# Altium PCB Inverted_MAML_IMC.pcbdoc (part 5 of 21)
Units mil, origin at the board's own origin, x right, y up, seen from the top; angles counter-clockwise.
Board outline 7677.1 x 6771.6 mil, 6 copper layers (Top Layer, Inner1, Inner2, Inner3, Inner4, Bottom Layer), stack 60.7 mil thick; 2730 components, 1566 nets, 7761 pads, 3719 vias.

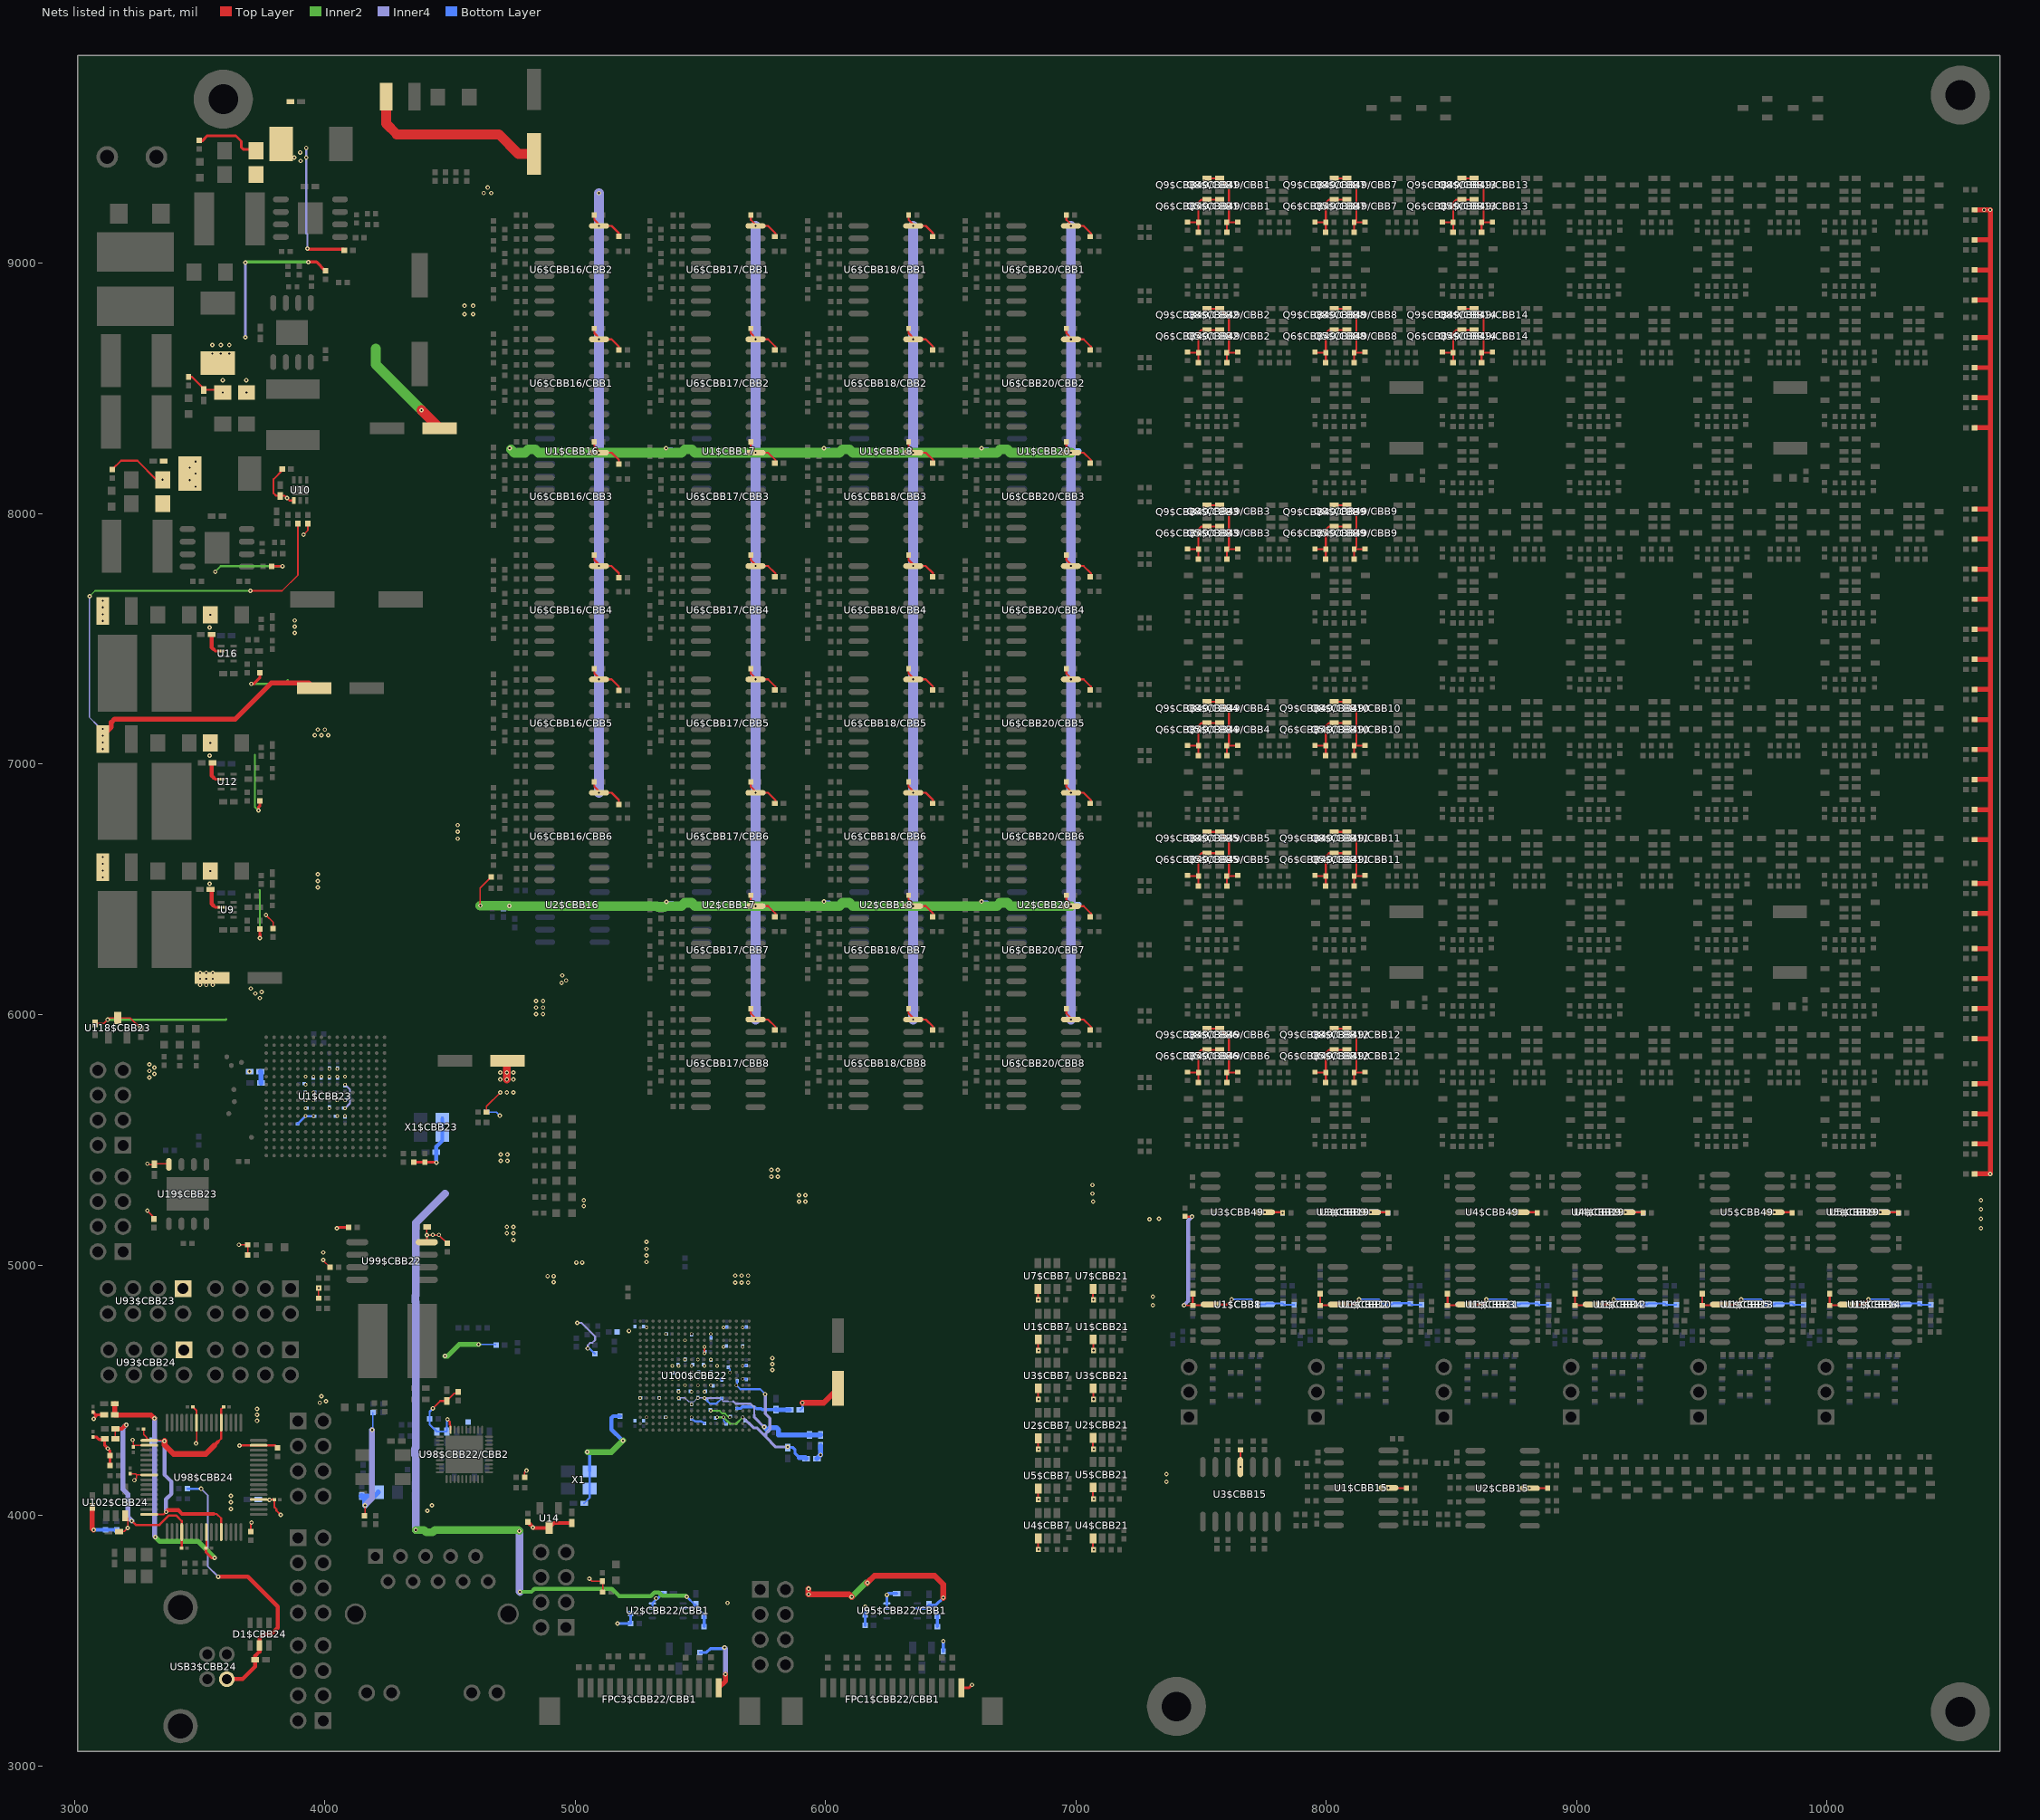
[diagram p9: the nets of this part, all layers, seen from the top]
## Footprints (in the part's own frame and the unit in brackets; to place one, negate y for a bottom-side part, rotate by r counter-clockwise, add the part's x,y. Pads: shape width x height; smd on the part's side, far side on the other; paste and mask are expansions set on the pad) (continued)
USB-B-TH_USB-B10-BRW [mil]
  round 63 hole 39.4: 1(49.2,92.8) 2(-49.2,92.8) 3(-49.2,14) 4(49.2,14)
  round 137.8 hole 98.4: 5(-237,-92.7) 6(237,-92.7)
  silkscreen extent -239,-504 239,138
VSSOP-8_L2.4-W2.1-P0.50-LS3.2-BR#1 [mil]
  oval 29.5x9.8 smd: 1(61,-29.5) 2(61,-9.8) 3(61,9.9) 4(61,29.6) 5(-61,29.6) 6(-61,9.9) 7(-61,-9.8) 8(-61,-29.5)
  silkscreen extent -35,-40 36,39
VSSOP-8_L2.4-W2.1-P0.50-LS3.2-BR#2 [mil]
  oval 29.5x9.8 smd: 1(61,-29.6) 2(61,-9.9) 3(61,9.8) 4(61,29.5) 5(-61,29.5) 6(-61,9.8) 7(-61,-9.9) 8(-61,-29.6)
  silkscreen extent -35,-40 35,39
WQFN-40_L5.0-W5.0-P0.4-BL-EP [mil]
  oval 7.9x31.5 smd paste-3937 mask+2: 1(-70.9,-98.4) 2(-55.1,-98.4) 3(-39.4,-98.4) 4(-23.6,-98.4) 5(-7.9,-98.4) 6(7.9,-98.4) 7(23.6,-98.4) 8(39.4,-98.4) 9(55.1,-98.4) 10(70.9,-98.4) 21(70.9,98.4) 22(55.1,98.4) 23(39.4,98.4) 24(23.6,98.4) 25(7.9,98.4) 26(-7.9,98.4) 27(-23.6,98.4) 28(-39.4,98.4) 29(-55.1,98.4) 30(-70.9,98.4)
  oval 31.5x7.9 smd paste-3937 mask+2: 11(98.4,-70.9) 12(98.4,-55.1) 13(98.4,-39.4) 14(98.4,-23.6) 15(98.4,-7.9) 16(98.4,7.9) 17(98.4,23.6) 18(98.4,39.4) 19(98.4,55.1) 20(98.4,70.9) 31(-98.4,70.9) 32(-98.4,55.1) 33(-98.4,39.4) 34(-98.4,23.6) 35(-98.4,7.9) 36(-98.4,-7.9) 37(-98.4,-23.6) 38(-98.4,-39.4) 39(-98.4,-55.1) 40(-98.4,-70.9)
  rect 149.6x149.6 smd paste-3937 mask+2: 41(0,0)
  silkscreen extent -106,-132 106,106
WSON-8_L6.0-W5.0-P1.27-BL-EP [mil]
  oval 22.9x50.2 smd: 1(-75,-118.6) 2(-25,-118.6) 3(25,-118.6) 4(75,-118.6) 5(75,118.6) 6(25,118.6) 7(-25,118.6) 8(-75,118.6)
  rect 169.3x133.9 smd: 9(0,0)
  silkscreen extent -102,-159 101,121

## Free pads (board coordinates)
  round 236.2 hole 118.1: 1(3595.2,9656.1) 1(7402.1,3236.9) 1(10532.6,3215.7) 1(10532.6,9672.4)

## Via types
v1: diameter 17.7, hole 7.9, Top Layer to Bottom Layer, 3387 vias
v2: diameter 13.8, hole 7.9, Top Layer to Bottom Layer, 287 vias
v3: diameter 23.6, hole 11.8, Top Layer to Bottom Layer, 45 vias

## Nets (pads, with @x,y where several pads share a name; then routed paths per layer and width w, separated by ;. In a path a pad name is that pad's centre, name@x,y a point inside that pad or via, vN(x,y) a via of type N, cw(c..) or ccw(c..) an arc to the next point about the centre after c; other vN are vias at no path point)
1.2V: C3$CBB23.1 C5.1 C8$CBB23.1 C9$CBB23.1 C10$CBB23.1 C11$CBB23.1 C12$CBB23.1 C14.1 C15.1 C16.1 C17.1 C18.1 C19.1 C20.1 C22$CBB22/CBB4.1 C23$CBB22/CBB4.1 C24$CBB22/CBB4.1 C25$CBB22/CBB4.1 C26.1 C28.1 C78.1 C80.1 C248.1 C250.1 C258.1 C313.1 C314.1 L10$CBB22/CBB4.1 L11$CBB22/CBB4.1 L11$CBB23.1 R146.1 U1$CBB23.E9 U1$CBB23.F8 U1$CBB23.F9 U1$CBB23.J6 U1$CBB23.J7 U1$CBB23.K9 U100$CBB22.G8 U100$CBB22.G10 U100$CBB22.G12 U100$CBB22.H7 U100$CBB22.H9 U100$CBB22.H11 U100$CBB22.J2 U100$CBB22.J8 U100$CBB22.J10 U100$CBB22.J12 U100$CBB22.K4 U100$CBB22.K7 U100$CBB22.K9 U100$CBB22.K11 U100$CBB22.L2 U100$CBB22.L6 U100$CBB22.L8 U100$CBB22.L10 U100$CBB22.L12 U100$CBB22.M7 U100$CBB22.M9 U100$CBB22.M11 U100$CBB22.P2 U100$CBB22.P5 U100$CBB22.T7 U100$CBB22.U2 U100$CBB22.U5 | length 154.4
  Bottom Layer w5.5: C18.1@5611.1,4591.4 5618.6,4583.9 v2(5618.6,4571)
  Bottom Layer w5.9: v2(5541.9,4724.5) 5542.8,4723.6 C23$CBB22/CBB4.1@5542.8,4709.4 ; v2(5593,4750.1) 5605.1,4750.1 C26.1@5607,4752.1 ; v2(5669.8,4750.1) 5681.4,4750.1 C25$CBB22/CBB4.1@5683.3,4752.1
  Bottom Layer w7.9: v2(5669.8,4545.4) 5680.7,4545.4 C78.1@5683.3,4542.8 ; v2(5669.8,4596.6) 5680.4,4596.6 C15.1@5683.3,4599.5
  Bottom Layer w19.7: L10$CBB22/CBB4.1@5965.8,4226.8 v1(5980.5,4241.5) L11$CBB22/CBB4.1@5980.5,4277.6
  other v1: 5639.2,4929.5 5665.3,4929.5 5691.4,4929.5 4914.3,4931.5 4890.2,4955.6 4914.3,4955.6 5639.2,4957.6 5665.3,4957.6 5691.4,4957.6 3700.2,5772.8 4844.1,6001.7 4872.2,6001.7 4844.1,6027.8 4872.2,6027.8 4844.1,6053.9 4872.2,6053.9 3502.8,6118.2 3526.9,6118.2 3553,6118.2 3502.8,6142.3 3526.9,6142.3 3553,6142.3 3502.8,6166.4 3526.9,6166.4 3553,6166.4 3113.3,7571.9 3113.3,7598 3113.3,7626.1 3113.3,7652.2
  other v2: 5413.9,4494.2 5465.1,4494.2 5516.3,4494.2 5439.5,4519.8 5490.7,4519.8 5541.9,4519.8 5413.9,4545.4 5465.1,4545.4 5516.3,4545.4 5439.5,4571 5490.7,4571 5541.9,4571 5413.9,4596.6 5465.1,4596.6 5516.3,4596.6 5567.4,4596.6 5439.5,4622.2 5490.7,4622.2 5541.9,4622.2 5593,4673.3 5669.8,4673.3 4018.6,5625.9 3924.1,5657.4 3955.6,5657.4 3987.1,5751.9 4018.6,5751.9 4018.6,5783.4
1.2VA1: C5$CBB23.1 C6$CBB23.1 C7$CBB23.1 C147$CBB23.2 L11$CBB23.2 U1$CBB23.F7 U1$CBB23.G11 U1$CBB23.K11 | length 157.6
  Inner4 w7.9: v2(4081.6,5625.9) 4101.1,5645.5 4101.1,5700.9 v2(4081.6,5720.4)
  Bottom Layer w19.7: L11$CBB23.2@3743.1,5772.8 3745.1,5770.8 C147$CBB23.2@3745.1,5726.7
  other v2: 3955.6,5751.9
1.2VA_MIPI_T1: C10.1 C11.1 C12.1 C13.1 C142$CBB22/CBB4.2 L10$CBB22/CBB4.2 U100$CBB22.C2 U100$CBB22.C5 U100$CBB22.C6 U100$CBB22.H3 | length 836.6
  Inner2 w7.9: v2(5567.4,4391.9) v2(5593,4391.9) 5619.6,4365.3 5643.3,4365.3 v2(5669.8,4391.9)
  Inner4 w11.8: v2(5669.8,4391.9) 5712.4,4349.3 5725.5,4349.3 5761.5,4313.3 ; v1(5759.6,4483.8) 5759.6,4405.5 5777.7,4387.4 5777.7,4343.2 5761.5,4327 5761.5,4313.3 ; v1(5850,4273) 5801.8,4273 5761.5,4313.3
  Bottom Layer w4.7: v2(5593,4391.9) 5593,4376.6 C11.1@5604.3,4365.3 ; v2(5669.8,4391.9) 5679.3,4382.3 C12.1@5679.3,4378.1
  Bottom Layer w7.9: C13.1@5647.2,4537.2 5647.2,4522.8 v2(5644.2,4519.8) 5660.2,4503.9 5739.6,4503.9 v1(5759.6,4483.8)
  Bottom Layer w11.8: C142$CBB22/CBB4.2@5850,4270.3 5850.9,4271.3 5869.8,4271.3 5878.1,4262.9 5878.1,4248.9 5896.2,4230.8
  Bottom Layer w19.7: 5896.2,4230.8 5918.9,4230.8 L10$CBB22/CBB4.2@5922.9,4226.8
1.2VA_PLL_T1: C21.1 C22.1 C23.1 C24.1 C25.1 C27.1 C147$CBB22/CBB4.2 L11$CBB22/CBB4.2 U100$CBB22.F8 U100$CBB22.F9 U100$CBB22.F12 U100$CBB22.N8 U100$CBB22.P8 | length 817.1
  Top Layer w7.9: v2(5516.3,4647.8) v2(5516.3,4673.3)
  Inner4 w3.9: 5452.3,4455.8 5476.7,4455.8 5489.5,4468.6 v2(5490.7,4468.6) ; 5611.9,4455.8 5631,4455.8
  Inner4 w5.5: v2(5413.9,4468.6) 5439.5,4468.6 5452.3,4455.8 ; v2(5490.7,4468.6) v2(5516.3,4468.6)
  Inner4 w5.9: v2(5516.3,4468.6) 5578,4468.6 5590.8,4455.8 5611.9,4455.8
  Inner4 w7.9: 5631,4455.8 5641.2,4445.6 5701.4,4445.6 5716,4431 5716,4400.9
  Inner4 w11.8: 5716,4400.9 5716,4390.9 5753.6,4353.3 v1(5755.7,4353.3)
  Bottom Layer w5.5: v1@5759,4350 5778.8,4350
  Bottom Layer w5.9: v2(5516.3,4468.6) 5521,4468.6 C24.1@5526,4463.7
  Bottom Layer w7.9: C24.1@5526.7,4457.7 5538.8,4445.6 5564.1,4445.6 C21.1@5586.2,4467.7
  Bottom Layer w19.7: v1(5755.7,4353.3) 5759,4350 5770.6,4338.5 5770.6,4341.8 5778.8,4350 5779.2,4350.5 5804.3,4350.5 5813,4341.8 5813,4320.5 C147$CBB22/CBB4.2@5936.3,4320.5 L11$CBB22/CBB4.2@5980.5,4320.5
1.8V: C1.2 C59$CBB22/CBB1.2 C79.1 R60.2 R97$CBB22/CBB1.2 R128$CBB22/CBB1.2 R129$CBB22/CBB1.2 R130$CBB22/CBB1.2 R132.1 U2$CBB22/CBB1.2 U95$CBB22/CBB1.2 | length 6410.3
  Top Layer w5.9: v1(3703.6,7692.4) 3830.1,7692.4 3892.9,7755.2 R60.2@3892.9,7961.1
  Top Layer w19.7: v1(3113.3,7114.3) 3147.4,7148.4 3147.4,7166.3 3161.3,7180.2 3643.2,7180.2 3787.9,7324.9 3935.8,7324.9 C79.1@3957.9,7302.8
  Top Layer w23.6: v1(5932.3,3706.7) v1(5932.3,3684.6) 6095,3684.6 v1(6105,3674.6) ; v1(6167.2,3730.8) 6195.4,3758.9 6436.3,3758.9 6470.4,3724.8 v1(6470.4,3670.6)
  Inner2 w5.9: v1(3061.1,7670.3) 3083.1,7692.4 v1(3703.6,7692.4)
  Inner2 w15.7: v1(4779.8,3694.7) 4826,3694.7 4838,3706.7 4844.8,3706.7 4845.1,3706.4 4883.5,3706.4 4883.9,3706.7 4944.8,3706.7 4945.1,3706.4 4983.5,3706.4 4983.9,3706.7 5147.2,3706.7 5176.4,3677.6 5302.2,3677.6 5316.9,3692.3 5334.9,3692.3 5347.7,3679.6 5441.4,3679.6 v1(5446.4,3674.6)
  Inner2 w23.6: v1(6105,3674.6) 6161.2,3730.8 v1(6167.2,3730.8)
  Inner2 w31.5: v1(4364.2,3941.7) 4396.6,3941.7 4406.1,3932.1 4430.6,3932.1 4440.2,3941.7 4773.8,3941.7 v1(4777.8,3937.6)
  Inner4 w5.9: v1(3061.1,7670.3) 3061.1,7186.4 3093.2,7154.3
  Inner4 w31.5: v1(4364.2,3941.7) 4364.2,4239.1 4360.7,4242.6 4360.7,4267.1 4364.2,4270.6 4364.2,4851.5 4362.7,4853 4362.7,4877.5 4364.2,4879 4364.2,5168.5 4480.6,5284.9 ; v1(4777.8,3937.6) 4777.8,3696.7 v1(4779.8,3694.7)
  Bottom Layer w7.9: U2$CBB22/CBB1.2@5431.4,3629.3 5468.8,3629.3 C1.2@5480.2,3640.8 ; v1(5446.4,3674.6) C1.2@5478.1,3643 ; R128$CBB22/CBB1.2@5515.5,3596.2 5515.5,3605.5 C1.2@5480.2,3640.8 ; C1.2@5478.1,3643 C1.2@5482.4,3643 C1.2@5480.2,3640.8 ; C1.2@5478.1,3643 C1.2@5480.2,3640.8
  Bottom Layer w11.8: R97$CBB22/CBB1.2@5515.5,3556 R128$CBB22/CBB1.2@5515.5,3596.2 ; U95$CBB22/CBB1.2@6367.1,3628.7 6400.3,3628.7 C59$CBB22/CBB1.2@6414.1,3642.5 ; R130$CBB22/CBB1.2@6447.3,3556.1 R129$CBB22/CBB1.2@6447.3,3596.3 6447.3,3609.3 C59$CBB22/CBB1.2@6414.1,3642.5 ; v1(6470.4,3670.6) 6442.3,3642.5 C59$CBB22/CBB1.2@6414.1,3642.5
  other v1: 5609.1,3650.5 4530.8,6702.5 4530.8,6730.6 4530.8,6756.7 3113.3,7060.1 3113.3,7086.2 3113.3,7140.4
1.8V_FT: C217$CBB24.2 C218$CBB24.1 C219$CBB24.1 U98$CBB24.12 U98$CBB24.37 U98$CBB24.49 U98$CBB24.64 | length 1248.5
  Top Layer w4.7: C218$CBB24.1@3276.7,4345.2 3276.7,4322.1 U98$CBB24.49@3299.4,4299.4 3357.9,4299.4 v1(3360.2,4297)
  Top Layer w7.9: U98$CBB24.64@3299.4,4004.1 3356.8,4004.1 v1(3366.4,4013.7) ; 3557,4005.9 3569.1,4005.9 3586.8,3988.2 U98$CBB24.12@3586.8,3933.3 ; 3573.1,4293 3586.8,4306.7 U98$CBB24.37@3586.8,4370.3 3586.8,4424 C219$CBB24.1@3596.4,4433.6
  Top Layer w15.7: v1(3366.4,4013.7) 3373.7,4021 3415.5,4021 3430.5,4005.9 3557,4005.9 ; 3558,4278 3573.1,4293
  Top Layer w23.6: v1(3360.2,4297) 3360.2,4281 3396.4,4244.8 3524.9,4244.8 3558,4278
  Inner4 w15.7: v1(3360.2,4297) 3360.2,4162.5 3388.3,4134.4 3388.3,4086.2 3366.4,4064.3 v1(3366.4,4013.7)
  Bottom Layer w7.9: C217$CBB24.2@3310,4296.4 3359.6,4296.4 v1(3360.2,4297)
2.5V: C77.1 L9$CBB22/CBB4.1 R58.1 | length 198.1
  Top Layer w23.6: v1(5908.2,4449.6) 5993.3,4449.6 C77.1@6050.8,4507.2
  Bottom Layer w7.9: L9$CBB22/CBB4.1@5899.6,4421.5 5908.2,4430.2 v1(5908.2,4449.6)
  other v1: 5034.8,5234.7 5894.2,5252.8 5920.3,5252.8 5034.8,5258.8 5894.2,5278.9 5920.3,5278.9 4946.3,6126.2 4964.5,6136.3 4948.5,6156.3 3113.3,6548.3 3113.3,6574.4 3113.3,6602.5 3113.3,6628.6
2.5VA_MIPI_T1: C8.1 C9.1 C52.1 C138$CBB22/CBB4.2 L9$CBB22/CBB4.2 U100$CBB22.C4 U100$CBB22.D7 | length 306.5
  Inner2 w7.9: v2(5541.9,4417.4) 5577,4417.4 5587.8,4406.6 5599.1,4406.6 5613.9,4391.9 v2(5618.6,4391.9)
  Bottom Layer w11.8: C9.1@5645.2,4426.8 5660.5,4426.8 5667.3,4433.6 5717.5,4433.6 5725.5,4425.6 5743.6,4425.6 5747,4422.2 C138$CBB22/CBB4.2@5801.8,4422.2
  Bottom Layer w19.7: C138$CBB22/CBB4.2@5801.8,4422.2 5802.4,4421.5 L9$CBB22/CBB4.2@5856.6,4421.5
3.3V: C1$CBB7.2 C1$CBB16.2 C1$CBB17.2 C1$CBB18.2 C1$CBB20.2 C1$CBB21.2 C2$CBB7.2 C2$CBB15.2 C2$CBB21.2 C3$CBB7.2 C3$CBB21.2 C4$CBB7.2 C4$CBB21.2 C7$CBB7.2 C7$CBB21.2 C37.2 C67.2 C71.2 C75.1 C145$CBB15.2 C146$CBB15.2 C193$CBB1.2 C193$CBB2.2 C193$CBB3.2 C193$CBB4.2 C193$CBB5.2 C193$CBB6.2 C193$CBB7.2 C193$CBB8.2 C193$CBB10.2 C193$CBB11.2 C193$CBB12.2 C193$CBB13.2 C193$CBB14.2 C193$CBB16.2 C193$CBB16/CBB1.2 C193$CBB16/CBB2.2 C193$CBB16/CBB3.2 C193$CBB16/CBB4.2 C193$CBB16/CBB5.2 C193$CBB16/CBB6.2 C193$CBB17.2 C193$CBB17/CBB1.2 C193$CBB17/CBB2.2 C193$CBB17/CBB3.2 C193$CBB17/CBB4.2 C193$CBB17/CBB5.2 C193$CBB17/CBB6.2 C193$CBB17/CBB7.2 C193$CBB17/CBB8.2 C193$CBB18.2 C193$CBB18/CBB1.2 C193$CBB18/CBB2.2 C193$CBB18/CBB3.2 C193$CBB18/CBB4.2 C193$CBB18/CBB5.2 C193$CBB18/CBB6.2 C193$CBB18/CBB7.2 C193$CBB18/CBB8.2 C193$CBB20.2 C193$CBB20/CBB1.2 C193$CBB20/CBB2.2 C193$CBB20/CBB3.2 C193$CBB20/CBB4.2 C193$CBB20/CBB5.2 C193$CBB20/CBB6.2 C193$CBB20/CBB7.2 C193$CBB20/CBB8.2 C193$CBB21.2 C194$CBB9.2 C194$CBB19.2 C195$CBB9.2 C195$CBB19.2 C195$CBB49.2 C196$CBB9.2 C196$CBB19.2 C196$CBB49.2 C197$CBB9.2 C197$CBB19.2 C197$CBB49.2 L6.2 R2.1 R4$CBB1.2 R4$CBB2.2 R4$CBB3.2 R4$CBB4.2 R4$CBB5.2 R4$CBB6.2 R4$CBB8.2 R4$CBB10.2 R4$CBB11.2 R4$CBB12.2 R4$CBB13.2 R4$CBB14.2 R5.1 R8.1 R11.1 R14.1 R16$CBB17.2 R16$CBB18.2 R16$CBB20.2 R17.1 R20.1 R23.1 R26.1 R29.1 R32$CBB16.2 R32.1 R35.1 R38.1 R41.1 R44.1 R48$CBB17.2 R48$CBB18.2 R48$CBB20.2 R61.2 R64$CBB16.2 R74.1 R80$CBB17.2 R80$CBB18.2 R80$CBB20.2 R81.1 R84.1 R87.1 R90.1 R93.1 R96$CBB16.2 R97.1 R98$CBB16.2 R100$CBB16.2 R100.1 R102$CBB16.2 R103.1 R104$CBB16.2 R106$CBB16.2 R106.1 R109.1 R112$CBB17.2 R112$CBB18.2 R112$CBB20.2 R112.1 R115.1 R118.1 R121.1 R129$CBB17.2 R129$CBB18.2 R129$CBB20.2 R131$CBB17.2 R131$CBB18.2 R131$CBB20.2 R133$CBB17.2 R133$CBB18.2 R133$CBB20.2 R135$CBB17.2 R135$CBB18.2 R135$CBB20.2 R137.1 U1$CBB1.4 U1$CBB2.4 U1$CBB3.4 U1$CBB4.4 U1$CBB5.4 U1$CBB6.4 U1$CBB7.1 U1$CBB8.4 U1$CBB10.4 U1$CBB11.4 U1$CBB12.4 U1$CBB13.4 U1$CBB14.4 U1$CBB15.11 U1$CBB16.4 U1$CBB17.4 U1$CBB18.4 U1$CBB20.4 U1$CBB21.1 U2$CBB7.1 U2$CBB15.11 U2$CBB16.4 U2$CBB17.4 U2$CBB18.4 U2$CBB20.4 U2$CBB21.1 U3$CBB7.1 U3$CBB9.11 U3$CBB15.11 U3$CBB19.11 U3$CBB21.1 U3$CBB49.11 U4$CBB7.1 U4$CBB9.11 U4$CBB19.11 U4$CBB21.1 U4$CBB49.11 U5$CBB7.1 U5$CBB9.11 U5$CBB19.11 U5$CBB21.1 U5$CBB49.11 U6$CBB16/CBB1.16 U6$CBB16/CBB2.16 U6$CBB16/CBB3.16 U6$CBB16/CBB4.16 U6$CBB16/CBB5.16 U6$CBB16/CBB6.16 U6$CBB17/CBB1.16 U6$CBB17/CBB2.16 U6$CBB17/CBB3.16 U6$CBB17/CBB4.16 U6$CBB17/CBB5.16 U6$CBB17/CBB6.16 U6$CBB17/CBB7.16 U6$CBB17/CBB8.16 U6$CBB18/CBB1.16 U6$CBB18/CBB2.16 U6$CBB18/CBB3.16 U6$CBB18/CBB4.16 U6$CBB18/CBB5.16 U6$CBB18/CBB6.16 U6$CBB18/CBB7.16 U6$CBB18/CBB8.16 U6$CBB20/CBB1.16 U6$CBB20/CBB2.16 U6$CBB20/CBB3.16 U6$CBB20/CBB4.16 U6$CBB20/CBB5.16 U6$CBB20/CBB6.16 U6$CBB20/CBB7.16 U6$CBB20/CBB8.16 U7$CBB7.1 U7$CBB21.1 | length 33377.3
  Top Layer w4.7: v1(4621.2,6434.7) 4621.2,6505.3 R96$CBB16.2@4665.1,6549.2
  Top Layer w5.9: v1(7432.2,4839.2) 7432.7,4838.7 C193$CBB1.2@7467.1,4838.7
  Top Layer w7.9: R61.2@3456.6,8546.4 3470,8546.4 3516.8,8499.5 C67.2@3516.8,8494.9 3582,8494.9 C37.2@3592.9,8484 ; C193$CBB16/CBB6.2@5077.2,6929.1 5077.2,6909.8 5095.7,6891.4 v1(5095.7,6885.8) 5146.3,6885.8 5175.1,6857 R106$CBB16.2@5175.1,6845 ; C193$CBB16/CBB5.2@5077.2,7381.8 5077.2,7362.6 5095.7,7344.2 v1(5095.7,7338.6) 5146.3,7338.6 5175.1,7309.8 R104$CBB16.2@5175.1,7297.7 ; C193$CBB16/CBB4.2@5077.2,7834.5 5077.2,7815.3 5095.7,7796.9 v1(5095.7,7791.3) 5146.3,7791.3 5175.1,7762.5 R102$CBB16.2@5175.1,7750.5 ; C193$CBB16/CBB3.2@5077.2,8287.3 5077.2,8268.1 5095.7,8249.7 v1(5095.7,8244.1) 5146.3,8244.1 5175.1,8215.3 R100$CBB16.2@5175.1,8203.2 ; C193$CBB16/CBB1.2@5077.2,8740.1 5077.2,8720.9 5095.7,8702.4 v1(5095.7,8696.8) 5146.3,8696.8 5175.1,8668 R98$CBB16.2@5175.1,8656 ; C193$CBB16/CBB2.2@5077.2,9192.8 5077.2,9173.6 5095.7,9155.2 v1(5095.7,9149.6) 5146.3,9149.6 5175.1,9120.8 R32$CBB16.2@5175.1,9108.7 ; C193$CBB17/CBB8.2@5702.2,6023.5 5702.2,6004.3 5720.7,5985.9 v1(5720.7,5980.3) 5771.3,5980.3 5800.1,5951.5 R135$CBB17.2@5800.1,5939.4 ; C193$CBB17/CBB7.2@5702.2,6476.3 5702.2,6457.1 5720.7,6438.6 v1(5720.7,6433.1) 5771.3,6433.1 5800.1,6404.2 R133$CBB17.2@5800.1,6392.2 ; C193$CBB17/CBB6.2@5702.2,6929 5702.2,6909.8 5720.7,6891.4 v1(5720.7,6885.8) 5771.3,6885.8 5800.1,6857 R131$CBB17.2@5800.1,6845 ; C193$CBB17/CBB5.2@5702.2,7381.8 5702.2,7362.6 5720.7,7344.2 v1(5720.7,7338.6) 5771.3,7338.6 5800.1,7309.8 R129$CBB17.2@5800.1,7297.7 ; C193$CBB17/CBB4.2@5702.2,7834.6 5702.2,7815.3 5720.7,7796.9 v1(5720.7,7791.3) 5771.3,7791.3 5800.1,7762.5 R112$CBB17.2@5800.1,7750.5 ; C193$CBB17/CBB3.2@5702.2,8287.3 5702.2,8268.1 5720.7,8249.7 v1(5720.7,8244.1) 5771.3,8244.1 5800.1,8215.3 R80$CBB17.2@5800.1,8203.2 ; C193$CBB17/CBB2.2@5702.2,8740.1 5702.2,8720.9 5720.7,8702.4 v1(5720.7,8696.8) 5771.3,8696.8 5800.1,8668 R48$CBB17.2@5800.1,8656 ; C193$CBB17/CBB1.2@5702.2,9192.8 5702.2,9173.6 5720.7,9155.2 v1(5720.7,9149.6) 5771.3,9149.6 5800.1,9120.8 R16$CBB17.2@5800.1,9108.7 ; C193$CBB18/CBB8.2@6332.2,6023.5 6332.2,6004.3 6350.6,5985.9 v1(6350.6,5980.3) 6401.2,5980.3 6430,5951.5 R135$CBB18.2@6430,5939.4 ; C193$CBB18/CBB7.2@6332.2,6476.3 6332.2,6457.1 6350.6,6438.6 v1(6350.6,6433.1) 6401.2,6433.1 6430,6404.2 R133$CBB18.2@6430,6392.2 ; C193$CBB18/CBB6.2@6332.2,6929 6332.2,6909.8 6350.6,6891.4 v1(6350.6,6885.8) 6401.2,6885.8 6430,6857 R131$CBB18.2@6430,6845 ; C193$CBB18/CBB5.2@6332.2,7381.8 6332.2,7362.6 6350.6,7344.2 v1(6350.6,7338.6) 6401.2,7338.6 6430,7309.7 R129$CBB18.2@6430,7297.7 ; C193$CBB18/CBB4.2@6332.2,7834.6 6332.2,7815.3 6350.6,7796.9 v1(6350.6,7791.3) 6401.2,7791.3 6430,7762.5 R112$CBB18.2@6430,7750.5 ; C193$CBB18/CBB3.2@6332.2,8287.3 6332.2,8268.1 6350.6,8249.7 v1(6350.6,8244.1) 6401.2,8244.1 6430,8215.3 R80$CBB18.2@6430,8203.2 ; C193$CBB18/CBB2.2@6332.2,8740.1 6332.2,8720.9 6350.6,8702.4 v1(6350.6,8696.8) 6401.2,8696.8 6430,8668 R48$CBB18.2@6430,8656 ; C193$CBB18/CBB1.2@6332.2,9192.8 6332.2,9173.6 6350.6,9155.2 v1(6350.6,9149.6) 6401.2,9149.6 6430,9120.8 R16$CBB18.2@6430,9108.7 ; U7$CBB7.1@6849.2,4904.5 6849.2,4861.5 v1(6850,4860.7) ; U4$CBB7.1@6849.7,3907.5 6849.7,3864.6 v1(6850.6,3863.7) ; U5$CBB7.1@6849.7,4107.5 6849.7,4064.6 v1(6850.6,4063.7) ; U2$CBB7.1@6849.7,4307.5 6849.7,4264.6 v1(6850.6,4263.7) ; U3$CBB7.1@6849.7,4507.5 6849.7,4464.6 v1(6850.6,4463.7) ; U1$CBB7.1@6849.7,4702.5 6849.7,4659.6 v1(6850.6,4658.7) ; C193$CBB20/CBB8.2@6962.1,6023.5 6962.1,6004.3 6980.5,5985.9 v1(6980.5,5980.3) 7031.1,5980.3 7059.9,5951.5 R135$CBB20.2@7059.9,5939.4 ; C193$CBB20/CBB7.2@6962.1,6476.3 6962.1,6457.1 6980.5,6438.6 v1(6980.5,6433.1) 7031.1,6433.1 7059.9,6404.2 R133$CBB20.2@7059.9,6392.2 ; C193$CBB20/CBB6.2@6962.1,6929 6962.1,6909.8 6980.5,6891.4 v1(6980.5,6885.8) 7031.1,6885.8 7059.9,6857 R131$CBB20.2@7059.9,6845 ; C193$CBB20/CBB5.2@6962.1,7381.8 6962.1,7362.6 6980.5,7344.2 v1(6980.5,7338.6) 7031.1,7338.6 7059.9,7309.7 R129$CBB20.2@7059.9,7297.7 ; C193$CBB20/CBB4.2@6962.1,7834.6 6962.1,7815.3 6980.5,7796.9 v1(6980.5,7791.3) 7031.1,7791.3 7059.9,7762.5 R112$CBB20.2@7059.9,7750.5 ; C193$CBB20/CBB3.2@6962.1,8287.3 6962.1,8268.1 6980.5,8249.7 v1(6980.5,8244.1) 7031.1,8244.1 7059.9,8215.3 R80$CBB20.2@7059.9,8203.2 ; C193$CBB20/CBB2.2@6962.1,8740.1 6962.1,8720.9 6980.5,8702.4 v1(6980.5,8696.8) 7031.1,8696.8 7059.9,8668 R48$CBB20.2@7059.9,8656 ; C193$CBB20/CBB1.2@6962.1,9192.8 6962.1,9173.6 6980.5,9155.2 v1(6980.5,9149.6) 7031.1,9149.6 7059.9,9120.8 R16$CBB20.2@7059.9,9108.7 ; U4$CBB21.1@7068.5,3908.3 7068.5,3865.3 v1(7071.4,3862.5) ; U5$CBB21.1@7068.5,4111.5 7068.5,4068.6 v1(7071.4,4065.7) ; U2$CBB21.1@7068.5,4309.8 7068.5,4266.8 v1(7071.4,4263.9) ; U7$CBB21.1@7068.5,4904.5 7068.5,4861.5 v1(7069.4,4860.7) ; U3$CBB21.1@7069.7,4507.5 7069.7,4464.6 v1(7070.6,4463.7) ; U1$CBB21.1@7069.7,4702.5 7069.7,4659.6 v1(7070.6,4658.7) ; C195$CBB9.2@7434,5194.2 7435.3,5192.9 v1(7464.1,5192.9) ; R4$CBB1.2@7467.1,4885.1 C193$CBB1.2@7467.1,4838.7 7534.6,4838.7 U1$CBB1.4@7538.1,4842.2 7602.1,4842.2 v1(7622.1,4862.2) ; U3$CBB15.11@7657,4192.9 v1(7657.4,4193.3) C146$CBB15.2@7657.4,4261.9 ; v1(7755.6,5210.6) 7823.4,5210.6 v1(7825.6,5208.4) ; R4$CBB2.2@7975.8,4885.1 C193$CBB2.2@7975.8,4838.7 8043.3,4838.7 U1$CBB2.4@8046.8,4842.2 8110.8,4842.2 v1(8130.8,4862.2) ; v1(8178.6,5210.6) 8246.4,5210.6 C194$CBB9.2@8248.6,5208.4 ; v1(8248.4,4109.7) 8248.8,4109.2 C145$CBB15.2@8319.5,4109.2 ; R4$CBB3.2@8484.5,4885.1 C193$CBB3.2@8484.5,4838.7 8552,4838.7 U1$CBB3.4@8555.5,4842.2 8619.5,4842.2 v1(8639.5,4862.2) ; U4$CBB49.11@8773,5210.6 8840.8,5210.6 C196$CBB49.2@8843,5208.4 ; v1(8813.4,4108.3) 8883.6,4108.3 C2$CBB15.2@8884.5,4109.2 ; R4$CBB4.2@8993.2,4885.1 C193$CBB4.2@8993.2,4838.7 9060.8,4838.7 U1$CBB4.4@9064.2,4842.2 9128.2,4842.2 v1(9148.2,4862.2) ; v1(9196,5210.6) 9263.8,5210.6 C197$CBB9.2@9266,5208.4 ; R4$CBB5.2@9501.9,4885.1 C193$CBB5.2@9501.9,4838.7 9569.5,4838.7 U1$CBB5.4@9572.9,4842.2 9636.9,4842.2 v1(9656.9,4862.2) ; v1(9790.4,5210.6) 9858.2,5210.6 C197$CBB49.2@9860.4,5208.4 ; R4$CBB6.2@10010.6,4885.1 C193$CBB6.2@10010.6,4838.7 10078.2,4838.7 U1$CBB6.4@10081.6,4842.2 10145.6,4842.2 v1(10165.6,4862.2) ; v1(10213.4,5210.6) 10281.2,5210.6 C196$CBB9.2@10283.4,5208.4
  Top Layer w11.8: v1(3934.5,9005.5) 3967.6,9005.5 R137.1@4002.8,8970.3
  Top Layer w19.7: R112.1@10589.2,5363.7 v1(10652.1,5363.7) 10652.1,5483.7 ; R29.1@10589.2,6523.7 10651.8,6523.7 ; R20.1@10589.2,6938.7 10651.8,6938.7 ; R74.1@10589.2,7298.7 10651.8,7298.7 ; R14.1@10589.2,7658.7 10651.8,7658.7 ; R118.1@10589.2,7898.7 10651.8,7898.7 ; R11.1@10589.2,8703.7 10651.8,8703.7 ; R81.1@10589.2,8853.7 10651.8,8853.7 ; R84.1@10589.2,8973.7 10651.8,8973.7 ; R5.1@10589.2,9213.7 v1(10627.2,9213.7) v1(10652.1,9213.7) 10652.1,9093.7 ; R115.1@10589.5,5483.7 10652.1,5483.7 ; R32.1@10589.5,5603.7 10652.1,5603.7 ; R35.1@10589.5,5723.7 10652.1,5723.7 ; R38.1@10589.5,5903.7 10652.1,5903.7 ; R41.1@10589.5,6023.7 10652.1,6023.7 ; R106.1@10589.5,6143.7 10652.1,6143.7 ; R109.1@10589.5,6263.7 10652.1,6263.7 ; R26.1@10589.5,6403.7 10652.1,6403.7 ; R100.1@10589.5,6698.7 10652.1,6698.7 ; R103.1@10589.5,6818.7 10652.1,6818.7 ; R23.1@10589.5,7058.7 10652.1,7058.7 ; R44.1@10589.5,7178.7 10652.1,7178.7 ; R93.1@10589.5,7418.7 10652.1,7418.7 ; R97.1@10589.5,7538.7 10652.1,7538.7 ; R17.1@10589.5,7778.7 10652.1,7778.7 ; R121.1@10589.5,8018.7 10652.1,8018.7 ; R87.1@10589.5,8343.7 10652.1,8343.7 ; R90.1@10589.5,8463.7 10652.1,8463.7 ; R8.1@10589.5,8583.7 10652.1,8583.7 ; R2.1@10589.5,9093.7 10652.1,9093.7 ; 10652.1,5483.7 10652.1,5603.7 ; 10652.1,5603.7 10652.1,5723.7 ; 10652.1,5723.7 10652.1,5903.7 ; 10652.1,5903.7 10652.1,6023.7 ; 10652.1,6023.7 10652.1,6143.7 ; 10652.1,6143.7 10652.1,6263.7 ; 10652.1,6263.7 10652.1,6403.7 ; 10652.1,6403.7 10652.1,6698.7 ; 10652.1,6698.7 10652.1,6818.7 ; 10652.1,6818.7 10652.1,7058.7 ; 10652.1,7058.7 10652.1,7178.7 ; 10652.1,7178.7 10652.1,7418.7 ; 10652.1,7418.7 10652.1,7538.7 ; 10652.1,7538.7 10652.1,7778.7 ; 10652.1,7778.7 10652.1,8018.7 ; 10652.1,8018.7 10652.1,8343.7 ; 10652.1,8343.7 10652.1,8463.7 ; 10652.1,8463.7 10652.1,8583.7 ; 10652.1,8583.7 10652.1,9093.7
  Top Layer w39.4: v1(4386.3,8413.2) 4387,8413.2 C75.1@4459.3,8340.9
  Inner2 w7.9: v3(5032.1,6433.7) v3@5032.8,6433.1
  Inner2 w11.8: v1(3683.5,9003.5) 3685.5,9005.5 v1(3934.5,9005.5)
  Inner2 w39.4: 4203.5,8660.2 4203.5,8595.9 v1(4386.3,8413.2) ; v1(4621.2,6434.7) 4737.3,6434.7 v1(4738,6434) 4739,6433.1 5032.8,6433.1 5327,6433.1 5330.5,6429.6 5358.3,6429.6 5361.8,6433.1 5425,6433.1 5438.2,6446.3 5466,6446.3 5479.2,6433.1 v1(5720.7,6433.1) 6055,6433.1 6068.2,6446.3 6095.9,6446.3 6109.1,6433.1 v1(6350.6,6433.1) 6684.9,6433.1 6698.1,6446.2 6725.9,6446.2 6739,6433.1 v1(6980.5,6433.1) ; v1@4743.7,8257.4 4757,8244.1 4800,8244.1 4813.2,8257.3 4841,8257.3 4854.2,8244.1 v1(5095.7,8244.1) 5425,8244.1 5438.2,8257.3 5466,8257.3 5479.2,8244.1 v1(5720.7,8244.1) 6055,8244.1 6068.2,8257.3 6095.9,8257.3 6109.1,8244.1 v1(6350.6,8244.1) 6684.9,8244.1 6698.1,8257.3 6725.9,8257.3 6739,8244.1 v1(6980.5,8244.1)
  Inner4 w11.8: v1(3683.4,8705.2) 3683.5,8705.4 v1(3683.5,9003.5)
  Inner4 w15.7: v1(7432.2,4839.2) 7448.3,4855.2 7448.3,5177.1 v1(7464.1,5192.9)
  Inner4 w39.4: v1(5095.7,6885.8) v1(5095.7,7338.6) v1(5095.7,7791.3) v1(5095.7,8244.1) v1(5095.7,8696.8) 5095.3,8697.2 5095.3,9149.3 v1(5095.7,9149.6) v1(5095.7,9280.6) ; v1(5720.7,5980.3) v1(5720.7,6433.1) v1(5720.7,6885.8) v1(5720.7,7338.6) v1(5720.7,7791.3) v1(5720.7,8244.1) v1(5720.7,8696.8) v1(5720.7,9149.6) ; v1(6350.6,5980.3) v1(6350.6,6433.1) v1(6350.6,6885.8) v1(6350.6,7338.6) v1(6350.6,7791.3) v1(6350.6,8244.1) v1(6350.6,8696.8) v1(6350.6,9149.6) ; v1(6980.5,5980.3) v1(6980.5,6433.1) v1(6980.5,6885.8) v1(6980.5,7338.6) v1(6980.5,7791.3) v1(6980.5,8244.1) v1(6980.5,8696.8) v1(6980.5,9149.6)
  Bottom Layer w4.7: R64$CBB16.2@4714.6,6423.7 4724.9,6434 v1(4738,6434)
  Bottom Layer w7.9: v1(4738,6434) 4772.4,6434 C1$CBB16.2@4772.9,6434.4 ; v1(4738.7,8262.3) 4762,8262.3 C193$CBB16.2@4775.6,8248.7 ; v3(5032.1,6433.7) 5037.5,6439.1 U2$CBB16.4@5098.4,6439.1 ; v1(5363.7,8262.3) 5387,8262.3 C193$CBB17.2@5400.6,8248.7 ; v1(5364.9,6450.1) 5388.2,6450.1 C1$CBB17.2@5400.6,6437.7 ; v1(5993.7,6451.3) 6016.9,6451.3 C1$CBB18.2@6030.5,6437.7 ; v1(5993.7,8262.3) 6016.9,8262.3 C193$CBB18.2@6030.5,8248.7 ; v1(6623.6,6451.3) 6646.8,6451.3 C1$CBB20.2@6660.4,6437.7 ; v1(6623.6,8262.3) 6646.8,8262.3 C193$CBB20.2@6660.4,8248.7 ; v1(7622.1,4862.2) 7702.1,4862.2 7721.7,4842.6 U1$CBB8.4@7756,4842.6 ; U1$CBB8.4@7755.9,4842.6 7759.4,4846.1 C193$CBB8.2@7826.9,4846.1 7832.4,4840.6 R4$CBB8.2@7871.9,4840.6 ; v1(8130.8,4862.2) 8210.8,4862.2 8230.4,4842.6 U1$CBB10.4@8264.7,4842.6 ; v1(8178.6,5210.6) 8242.2,5210.6 C194$CBB19.2@8245.6,5207.2 ; U1$CBB10.4@8264.6,4842.6 8269.2,4847.2 8334.6,4847.2 8341.1,4840.6 R4$CBB10.2@8380.6,4840.6 ; v1(8639.5,4862.2) 8719.5,4862.2 8739.1,4842.6 U1$CBB11.4@8773.4,4842.6 ; U1$CBB11.4@8773.3,4842.6 8776.8,4846.1 C193$CBB11.2@8844.3,4846.1 8849.8,4840.6 R4$CBB11.2@8889.3,4840.6 ; v1(9148.2,4862.2) 9228.2,4862.2 9247.8,4842.6 U1$CBB12.4@9282.1,4842.6 ; v1(9196,5210.6) 9259.5,5210.6 C195$CBB19.2@9263,5207.2 ; U1$CBB12.4@9282,4842.6 9285.5,4846.1 C193$CBB12.2@9353,4846.1 9358.5,4840.6 R4$CBB12.2@9398,4840.6 ; v1(9656.9,4862.2) 9736.9,4862.2 9756.5,4842.6 U1$CBB13.4@9790.8,4842.6 9794.2,4846.1 C193$CBB13.2@9861.7,4846.1 9867.2,4840.6 R4$CBB13.2@9906.7,4840.6 ; v1(10165.6,4862.2) 10245.6,4862.2 10265.2,4842.6 U1$CBB14.4@10299.5,4842.6 10302.9,4846.1 C193$CBB14.2@10370.4,4846.1 10375.9,4840.6 R4$CBB14.2@10415.4,4840.6 ; v1(10213.4,5210.6) 10276.9,5210.6 C196$CBB19.2@10280.4,5207.2
  other v1: 7361.9,4134.4 7361.9,4164.5 7307.7,4839.2 7307.7,4873.3 10614.7,5146.4 7293.7,5182.5 7331.8,5184.5 10614.7,5184.5 8759.3,5210.6 10614.7,5222.7 7068.8,5252.8 10614.7,5258.8 7066.8,5284.9 7066.8,5319.1 3592.8,8483.9 3687.8,8483.9 3593.1,8533.7 3687.5,8533.7 3551,8640.1 3585.1,8640.1 3619.3,8640.1 3551,8674.2 3585.1,8674.2 3619.3,8674.2 4558.9,8796.7 4593.1,8796.7 4558.9,8830.8 4593.1,8830.8 4635.2,9280.6 4665.4,9280.6 4651.3,9302.7
3.3V_PHY_JTAG: C214$CBB24.1 C215$CBB24.2 U98$CBB24.4 U104$CBB24.2 | length 844.1
  Top Layer w4.7: U104$CBB24.2@3164.3,4305.1 3164.3,4345.5 C215$CBB24.2@3164.3,4345.6
  Top Layer w7.9: C214$CBB24.1@3427.7,3869.4 3429.3,3870.9 U98$CBB24.4@3429.3,3933.3
  Top Layer w8.7: v1(3229.7,3977.8) 3245.8,3961.7 3340.2,3961.7 3378.3,3999.9 3406.4,3999.9 3429.3,3977 U98$CBB24.4@3429.3,3933.3
  Top Layer w15.7: C215$CBB24.2@3164.3,4345.6 3189.9,4345.6 3205.5,4361.2 v1(3207.6,4361.2)
  Inner2 w4.7: 3207.6,4351.3 v1(3207.6,4361.2)
  Inner4 w19.7: v1(3207.6,4361.2) 3193.7,4347.2 3193.7,4104.2 3213.4,4084.5 3213.4,3994.1 v1(3229.7,3977.8)
3.3V_PLL_JTAG: C188$CBB24.1 C212$CBB24.2 U98$CBB24.9 U103$CBB24.2 | length 1078.9
  Top Layer w7.9: C188$CBB24.1@3526.1,3869.4 3527.7,3871 U98$CBB24.9@3527.7,3933.3
  Top Layer w11.8: C188$CBB24.1@3526.1,3869.4 3526.1,3852.1 3548,3830.2 v1(3560,3830.2)
  Top Layer w19.7: C212$CBB24.2@3162.3,4445.9 3162.3,4401.6 U103$CBB24.2@3162.2,4401.5 3306,4401.5 v1(3320.1,4387.4)
  Inner2 w19.7: v1(3324.1,3913.5) 3342.2,3895.5 3494.8,3895.5 v1(3560,3830.2)
  Inner4 w19.7: v1(3320.1,4387.4) 3320.1,3917.6 v1(3324.1,3913.5)
3.3VD: C1$CBB23.1 C2$CBB23.1 C4$CBB23.1 C13$CBB23.1 C14$CBB23.1 C15$CBB23.1 C16$CBB23.1 C17$CBB23.1 C18$CBB23.1 C19$CBB23.1 C20$CBB23.1 C21$CBB23.1 C22$CBB23.1 C23$CBB23.1 C38.2 C42.1 C43$CBB22/CBB1.2 C50.2 C51.2 C57$CBB22.1 C58$CBB22/CBB1.2 C63.1 C76.1 C122$CBB22/CBB2.1 C123$CBB22/CBB2.1 C125$CBB22/CBB2.1 C136$CBB22/CBB2.1 C168.2 C169.2 C170.2 C171.2 C172.2 C173.2 C174.2 C175.2 C176.2 C177.2 C178.2 C179.2 C180.2 C181.2 C183$CBB24.2 C186$CBB24.1 C213$CBB24.1 C220$CBB24.2 C221$CBB24.1 C222$CBB24.1 C223$CBB24.1 C224$CBB24.1 C225$CBB23.1 C227$CBB22.1 FPC1$CBB22/CBB1.15 FPC3$CBB22/CBB1.15 L3.2 L13.1 R1$CBB23.2 R2$CBB23.2 R3$CBB23.2 R4$CBB23.2 R5$CBB23.2 R6$CBB23.2 R7$CBB23.2 R11$CBB23.2 R19$CBB23.2 R49.2 R50.2 R54.2 R66.2 R67.2 R68.2 R69.2 R70.2 R71.2 R74$CBB22/CBB1.1 R75.1 R76.1 R84$CBB22/CBB1.1 R130.1 R131$CBB22/CBB1.2 R132$CBB22/CBB1.2 R133$CBB22/CBB1.2 R134$CBB22/CBB1.2 R139.2 R174$CBB22/CBB2.2 R176$CBB22/CBB2.1 R179$CBB22/CBB2.1 R180$CBB22/CBB2.1 R211$CBB24.2 R213$CBB24.2 R214$CBB24.2 R218$CBB24.1 R220$CBB24.1 R222$CBB24.1 R252$CBB22.2 R253$CBB22.2 R260$CBB22.2 U1$CBB23.E10 U1$CBB23.F6 U1$CBB23.F10 U1$CBB23.F11 U1$CBB23.G6 U1$CBB23.H6 U1$CBB23.H7 U1$CBB23.J10 U1$CBB23.J11 U1$CBB23.K6 U1$CBB23.L6 U1$CBB23.L7 U1$CBB23.L10 U1$CBB23.L11 U2$CBB22/CBB1.7 U2$CBB22/CBB1.8 U14.3 U19$CBB23.8 U93$CBB23.1 U93$CBB24.1 U95$CBB22/CBB1.7 U95$CBB22/CBB1.8 U98$CBB22/CBB2.29 U98$CBB24.20 U98$CBB24.31 U98$CBB24.42 U98$CBB24.50 U98$CBB24.56 U99$CBB22.8 U100$CBB22.C10 U100$CBB22.C14 U100$CBB22.C17 U100$CBB22.E10 U100$CBB22.F15 U100$CBB22.F18 U100$CBB22.J6 U100$CBB22.J13 U100$CBB22.K13 U100$CBB22.L13 U100$CBB22.R11 U100$CBB22.T10 U100$CBB22.T14 U100$CBB22.U17 U102$CBB24.6 U103$CBB24.1 U104$CBB24.1 U118$CBB23.3 X1$CBB23.1 X1$CBB23.4 X1.1 X1.4 | length 6620.8
  Top Layer w4.7: C225$CBB23.1@3083.1,5965 3118.7,5965 v1(3133.1,5979.4) 3140.6,5986.9 U118$CBB23.3@3173.5,5986.9 3223.5,5986.9 R1$CBB23.2@3265.9,5944.5 ; C42.1@3178.9,3935.6 3199.6,3935.6 v1(3213.7,3949.7) 3213.7,3970.9 3213.5,3971.1 3213.5,3984.5 3213.7,3984.7 3213.7,3988.6 U102$CBB24.6@3203.1,3999.2 ; C223$CBB24.1@3223.7,4165.8 3244.5,4165.8 3248.7,4161.6 ; v1(3233.7,4301.1) 3235.7,4299.1 C221$CBB24.1@3235.7,4273.7 3241.8,4279.7 U98$CBB24.50@3299.4,4279.7 ; v1(3239.8,4140.4) 3248.7,4149.4 3248.7,4161.6 ; v1(3292.1,5216.7) 3318.1,5190.7 R5$CBB23.2@3318.1,5183.5 ; v1(3292.1,5404.1) 3294.8,5401.4 3318.7,5401.4 C2$CBB23.1@3320.1,5402.8 3320.6,5403.3 3376.2,5403.5 U19$CBB23.8@3377.9,5401.8 ; U98$CBB24.56@3299.4,4161.6 3248.7,4161.6 ; v1(3486.7,4287) 3488.3,4288.6 U98$CBB24.42@3488.3,4370.3 ; v1(3657.4,5080.6) R11$CBB23.2@3692.7,5080.6 R19$CBB23.2@3692.7,5040.5 ; R49.2@4159.4,3998.9 4161.4,4000.9 v1(4161.4,4040) ; C227$CBB22.1@4409.2,5151.6 4407.9,5150.4 v1(4407.9,5119.3) 4457.2,5119.3 R66.2@4490.1,5086.4 ; C125$CBB22/CBB2.1@4487.9,4456.7 4487.9,4456.9 4517.7,4486.8 R71.2@4528.8,4486.8 ; R180$CBB22/CBB2.1@4798.9,4152.5 4798.9,4171.5 v1(4805.9,4178.6) ; v1(5056.9,3746.9) 5066.7,3737.1 R253$CBB22.2@5109,3737.1 5110.1,3736 R260$CBB22.2@5110.1,3693.9
  Top Layer w5.9: v1(3765.8,6397.3) 3793.9,6369.2 R2$CBB23.2@3793.9,6344 ; R76.1@3975.7,4867.3 v1(3975.7,4907.4) ; v1(3994.7,5019.9) 3994.7,5017.6 R67.2@4021.3,4991 ; R6$CBB23.2@4646.3,5610.2 4646.3,5633.3 v1(4701.5,5688.5)
  Top Layer w7.9: R54.2@3151.4,8176.9 3186.8,8212.4 3251.8,8212.4 3328.6,8135.6 C50.2@3351.4,8135.6 ; C222$CBB24.1@3473.4,4433.6 3488.3,4418.7 U98$CBB24.42@3488.3,4370.3 ; v1(3659.4,4279) 3660.2,4279.7 U98$CBB24.31@3736.4,4279.7 3802.2,4279.7 R222$CBB24.1@3812,4269.9 ; R218$CBB24.1@3705.6,3934.6 3705.6,3969.8 v1(3707.6,3971.8) ; U98$CBB24.20@3736.4,4063.2 3798.1,4063.2 C224$CBB24.1@3799.2,4062.1 3799.2,4032.7 3807.2,4024.6 3807.2,4018.7 v1(3824.1,4001.9) ; R130.1@3787.8,7790.6 v1(3832.1,7790.6) ; U99$CBB22.8@4407.9,5090.8 v1(4407.9,5119.3) ; v1(4432.4,4427.6) 4461.6,4456.7 C125$CBB22/CBB2.1@4487.9,4456.7 ; v1(4490.7,4383) 4499.7,4374 4499.7,4362.4 4502.8,4359.2 U98$CBB22/CBB2.29@4502.8,4341.6
  Top Layer w11.8: C213$CBB24.1@3074.6,4312.7 3089.6,4312.7 3099.2,4303.1 3119.3,4303.1 U104$CBB24.1@3121.3,4305.1 3121.3,4278.9 v1(3133.3,4266.9) 3142.4,4257.9 R220$CBB24.1@3142.4,4238.8 R211$CBB24.2@3142.4,4198.7 ; C186$CBB24.1@3074.6,4413.1 3086.2,4401.5 ; v1(3077.1,4385.4) 3086.2,4394.5 3086.2,4401.5 ; U103$CBB24.1@3119.3,4401.5 3086.2,4401.5 ; v1(4049.1,5146.4) 4053.1,5150.4 R68.2@4096.1,5150.4 ; R3$CBB23.2@4356.1,5410.4 R4$CBB23.2@4400.3,5410.4 4444.8,5410.4 v1(4445.9,5409.4) ; FPC1$CBB22/CBB1.15@6543.2,3311.3 6572.9,3311.3 v1(6584.9,3323.2)
  Top Layer w15.7: R139.2@4810.9,3973.8 4834.9,3949.8 U14.3@4896.7,3949.8 4916.4,3969.4 C63.1@4987.6,3969.4
  Top Layer w19.7: C183$CBB24.2@3071.7,4034.1 3071.7,3947.1 v1(3077.1,3941.7) ; FPC3$CBB22/CBB1.15@5573.4,3311.3 5601,3338.8 v1(5601,3365.4)
  Top Layer w31.5: v1(4727.6,5740.7) v1(4727.6,5768.8) 4727.6,5812.3 C76.1@4730.3,5815
  Inner2 w7.9: v1(3133.1,5979.4) 3604.9,5979.4 3607.2,5981.7 ; v1(3563,7768.7) 3584.9,7790.6 v1(3832.1,7790.6)
  Inner2 w19.7: v1(4480.6,4636.4) 4490.7,4636.4 4536.9,4682.6 v1(4615,4682.6)
  Inner2 w23.6: v1(5048.9,4252.9) 5145.2,4252.9 v1(5191.4,4299.1)
  Inner4 w7.9: v1(5008.7,4768.9) 5025.8,4768.9 5080,4714.7 5080,4700 5069.6,4689.6 5060.9,4689.6 5050.9,4679.5 v1(5050.9,4666.5)
  Inner4 w19.7: v1(5597,3471.8) 5601,3467.8 v1(5601,3365.4)
  Inner4 w23.6: v1(4161.4,4040) 4189.5,4068.1 v1(4189.5,4341.2)
  Bottom Layer w4.7: v1(4189.5,4341.2) 4192.6,4344.4 R50.2@4192.6,4411.1 ; v1(4615,4682.6) 4682.4,4682.6 R252$CBB22.2@4684.5,4680.6
  Bottom Layer w5.9: C220$CBB24.2@3735.1,4064.1 3777.9,4064.1 v1(3779.9,4062.1) ; R7$CBB23.2@4646.3,5610.2 4685.4,5610.2 v1(4699.5,5596.1)
  Bottom Layer w7.9: v1(4432.4,4427.6) 4419.4,4414.5 R179$CBB22/CBB2.1@4419.4,4385.4 4419.4,4363.1 C123$CBB22/CBB2.1@4447.9,4334.6 C122$CBB22/CBB2.1@4487.9,4334.6 4487.9,4380.2 v1(4490.7,4383) ; C57$CBB22.1@5036.2,4048.1 5058.5,4070.4 X1.1@5058.5,4107.5 X1.4@5058.5,4176.4 ; v1@5044.8,4666.5 5057.6,4666.5 5064.6,4659.4 5065,4659.4 R69.2@5079,4645.4 ; C173.2@5464.5,4386.2 5470.8,4379.9 5474.2,4379.9 5478.7,4375.4 5504.5,4375.4 5507,4372.8 5510.4,4372.8 C168.2@5516.7,4366.6 ; v2(5567.4,4545.4) 5582.3,4545.4 C172.2@5587,4540.8
  Bottom Layer w9.8: C17$CBB23.1@3891.1,5564 3893.7,5564 v2(3924.1,5594.5) v2(3955.6,5594.5) ; U2$CBB22/CBB1.7@5309.4,3629.3 U2$CBB22/CBB1.8@5309.4,3649 5323.9,3663.5 v1(5323.9,3668.6)
  Bottom Layer w11.8: v1(5048.9,4252.9) 5058.5,4243.3 X1.4@5058.5,4176.4 ; v1(5169.3,3568) R132$CBB22/CBB1.2@5222.4,3568 R131$CBB22/CBB1.2@5222.4,3608.2 ; v1(5323.9,3668.6) 5330.6,3668.6 C43$CBB22/CBB1.2@5350.5,3688.5 ; R74$CBB22/CBB1.1@5498.6,3452.7 5525.7,3452.7 5540.8,3467.8 5593,3467.8 v1(5597,3471.8) ; R134$CBB22/CBB1.2@6158.2,3560.2 R133$CBB22/CBB1.2@6158.2,3602.3 6158.2,3633.5 v1(6159.2,3634.4) ; U95$CBB22/CBB1.7@6245.1,3628.7 U95$CBB22/CBB1.8@6245.1,3648.4 6245.1,3682.2 v1(6245.6,3682.6) 6251,3688 C58$CBB22/CBB1.2@6284.2,3688 ; R84$CBB22/CBB1.1@6470.4,3456.7 v1(6470.4,3497.9)
  Bottom Layer w15.7: v1(3077.1,3941.7) 3077.7,3942.2 R214$CBB24.2@3124.2,3942.2 R213$CBB24.2@3169.2,3942.2 ; v1(4445.9,5409.4) C1$CBB23.1@4445.9,5449.6 4445.9,5473 4469.6,5496.7 X1$CBB23.1@4469.6,5515.8 X1$CBB23.4@4469.6,5584.7 ; R176$CBB22/CBB2.1@5179.4,4396.4 5152.2,4396.4 5145.2,4389.4 5145.2,4343.2 5189.4,4299.1 v1(5191.4,4299.1)
  Bottom Layer w19.7: C136$CBB22/CBB2.1@4147.9,4076.7 4198.4,4076.7 L13.1@4214.8,4093.2
  Bottom Layer w23.6: C136$CBB22/CBB2.1@4147.9,4076.7 4161.4,4063.2 v1(4161.4,4040)
  other v1: 4832,3951.7 4410.4,4018 3625.3,4026 4428.4,4040 3625.3,4052.1 3625.3,4078.2 3729.7,4377.4 3729.7,4401.5 3729.7,4425.6 3980.7,4449.6 4004.8,4455.7 3986.7,4475.7 5787.8,4580.2 5787.8,4604.3 5787.8,4628.3 5215.5,4736.8 5004.7,5009.8 5028.8,5009.8 5285.8,5011.9 5285.8,5038 3994.7,5050 5285.8,5064.1 5285.8,5092.2 4753.7,5100.2 4432.4,5120.3 4456.5,5120.3 4727.6,5126.3 4753.7,5126.3 4727.6,5152.4 4753.7,5152.4 5783.7,5353.2 5809.8,5353.2 5783.7,5379.3 5809.8,5379.3 4703.5,5415.4 4729.6,5415.4 4703.5,5441.5 4729.6,5441.5 4727.6,5688.5 4753.7,5688.5 4701.5,5740.7 4753.7,5740.7 3300,5748.7 3320.1,5762.8 4701.5,5768.8 4753.7,5768.8 3300,5774.8 3320.1,5788.9 3300,5800.9 3741.7,6066 3723.7,6084.1 3747.8,6090.1 3705.6,6104.1 3484.7,8108 3460.6,8134.1 3352.2,8136.1 3484.7,8160.2 3461.2,8184.4 3484.7,8208.4
  other v2: 5285.9,4391.9 5362.7,4391.9 5465.1,4391.9 5465.1,4443 5260.4,4468.6 5337.1,4468.6 5388.3,4545.4 5388.3,4571 5388.3,4596.6 5439.5,4698.9 5362.7,4724.5 5465.1,4724.5 5285.9,4750.1 4050.1,5594.5 4081.6,5594.5 3924.1,5625.9 4050.1,5657.4 4081.6,5657.4 3924.1,5688.9 3955.6,5688.9 3924.1,5720.4 3924.1,5751.9 4050.1,5751.9 4081.6,5751.9 4050.1,5783.4
5.0V: C6.2 C29.2 C30.2 C31.2 C32.2 C43.1 C44.2 C47.1 C60.1 C61.2 C82.1 L2.2 R51.2 R53.2 R58$CBB23.1 R124.2 R125.1 R126.2 R128.2 R140.2 U9.2 U10.1 U12.2 U16.2 | length 2831.9
  Top Layer w5.9: v1(3915.6,7916) 3932.9,7933.3 R126.2@3932.9,7961.1
  Top Layer w7.9: R124.2@3830.8,8178.2 3830.8,8173 3795.9,8138.1 3795.9,8081.9 3806.1,8071.7 C47.1@3822.9,8071.7 3840.2,8071.7 v1(3849.4,8062.6) 3859.2,8052.8 U10.1@3877.1,8052.8
  Top Layer w11: 3555.7,6435.1 3562.6,6428.2 U9.2@3585.9,6428.2 ; 3555.7,6947 3562.6,6940 U12.2@3585.9,6940 ; 3555.7,7458.8 3562.6,7451.8 U16.2@3585.9,7451.8
  Top Layer w11.8: R51.2@3498.6,9490.8 3512.2,9490.8 3530.9,9509.5 3645.4,9509.5 3667.1,9487.7 3667.1,9463.6 3675.5,9455.3 3720.4,9455.3 C29.2@3725.7,9449.9 ; v1(3707.3,7320.9) 3717.6,7320.9 3741.1,7344.4 R140.2@3741.1,7364.9 ; v1(3735.7,6815.1) 3735.7,6827.2 3741.1,6832.6 R128.2@3741.1,6853.1 ; R53.2@3741.1,6341.3 3741.1,6320.8 3741.7,6320.2 v1(3741.7,6305.3) ; v1(3930.5,9059.3) 3933.4,9056.4 4074.6,9056.4 R125.1@4078.5,9052.4
  Top Layer w15.7: C31.2@3548.3,6494.1 3548.3,6442.5 3555.7,6435.1 ; C43.1@3548.3,7005.9 3548.3,6954.3 3555.7,6947 ; C60.1@3548.3,7517.7 3548.3,7466.1 3555.7,7458.8
  Top Layer w39.4: R58$CBB23.1@4245.2,9666.1 4245.2,9558.2 4287.9,9515.5 4695.5,9515.5 4773.9,9437.1 C82.1@4836,9437.1
  Inner2 w7.9: v1(3707.3,7320.9) 3838.1,7320.9 3852.2,7335 ; 3721.5,7038 3721.5,6829.4 v1(3735.7,6815.1) ; 3739.7,6497.7 3741.7,6495.7 v1(3741.7,6305.3)
  Inner4 w7.9: v1(3926.5,9461.3) v1(3926.5,9422.9) 3926.5,9120 3930.5,9115.9 v1(3930.5,9059.3)
  other v1: 3972.6,6507.7 3540.4,6522.5 3972.6,6533.8 3972.6,6559.9 3543.4,6573.3 3540.4,7034.3 3543.4,7085.2 3960.6,7116.1 3986.7,7116.1 4014.8,7116.1 3972.6,7138.2 4000.8,7138.2 3880.3,7523.7 3540.4,7546.1 3880.3,7549.8 3880.3,7573.9 3543.4,7597 3904.4,9409.1 3878.3,9423.1 3902.4,9443.2
5_VBUS: C226$CBB24.2 D1$CBB24.5 R179$CBB24.2 USB3$CBB24.1 | length 1149.7
  Top Layer w15.7: v1(3575.1,3754.9) 3693.5,3754.9 3812.5,3636 3812.5,3550.6 3787.9,3526 3757.8,3526 3739.7,3508 D1$CBB24.5@3739.7,3480.8 3739.7,3455.7 3722.3,3438.3 C226$CBB24.2@3722.3,3423.6 3722.3,3396.1 3672.4,3346.3 USB3$CBB24.1@3609.6,3346.3
  Inner4 w7.9: v1(3506.8,4106.3) 3532.9,4080.2 3532.9,3797.1 v1(3575.1,3754.9)
  Bottom Layer w7.9: R179$CBB24.2@3451.6,4106.2 v1@3506.8,4106.2
$1I15\$1I2\$2N1: C1$CBB49/CBB1.2 C2$CBB49/CBB1.2 Q5$CBB49/CBB1.1 Q6$CBB49/CBB1.2 R1$CBB49/CBB1.2 | length 252
  Top Layer w7.9: C2$CBB49/CBB1.2@7446.2,9165.3 7447.7,9163.7 C1$CBB49/CBB1.2@7489.6,9163.7 ; R1$CBB49/CBB1.2@7489.1,9123.7 7489.6,9124.2 C1$CBB49/CBB1.2@7489.6,9163.7 ; Q5$CBB49/CBB1.1@7573.8,9254.3 Q6$CBB49/CBB1.2@7523.6,9254.3 7501.8,9254.3 7489.6,9242.2 C1$CBB49/CBB1.2@7489.6,9163.7
$1I15\$1I2\$2N14: C3$CBB49/CBB1.2 C4$CBB49/CBB1.2 Q8$CBB49/CBB1.1 Q9$CBB49/CBB1.2 R2$CBB49/CBB1.2 | length 329.2
  Top Layer w7.9: Q9$CBB49/CBB1.2@7523.6,9339.3 Q8$CBB49/CBB1.1@7573.8,9339.3 7611.2,9301.9 7611.2,9172.2 C3$CBB49/CBB1.2@7602.7,9163.7 ; R2$CBB49/CBB1.2@7603.2,9123.7 7603.2,9163.2 C3$CBB49/CBB1.2@7602.7,9163.7 ; C4$CBB49/CBB1.2@7646.2,9165.3 7644.6,9163.7 C3$CBB49/CBB1.2@7602.7,9163.7
$1I15\$1I3\$2N1: C1$CBB49/CBB2.2 C2$CBB49/CBB2.2 Q5$CBB49/CBB2.1 Q6$CBB49/CBB2.2 R1$CBB49/CBB2.2 | length 252
  Top Layer w7.9: C2$CBB49/CBB2.2@7446.2,8645.3 7447.7,8643.7 C1$CBB49/CBB2.2@7489.6,8643.7 ; R1$CBB49/CBB2.2@7489.1,8603.7 7489.6,8604.2 C1$CBB49/CBB2.2@7489.6,8643.7 ; Q5$CBB49/CBB2.1@7573.8,8734.3 Q6$CBB49/CBB2.2@7523.6,8734.3 7501.8,8734.3 7489.6,8722.2 C1$CBB49/CBB2.2@7489.6,8643.7
$1I15\$1I3\$2N14: C3$CBB49/CBB2.2 C4$CBB49/CBB2.2 Q8$CBB49/CBB2.1 Q9$CBB49/CBB2.2 R2$CBB49/CBB2.2 | length 329.2
  Top Layer w7.9: Q9$CBB49/CBB2.2@7523.6,8819.3 Q8$CBB49/CBB2.1@7573.8,8819.3 7611.2,8781.9 7611.2,8652.2 C3$CBB49/CBB2.2@7602.7,8643.7 ; R2$CBB49/CBB2.2@7603.2,8603.7 7603.2,8643.2 C3$CBB49/CBB2.2@7602.7,8643.7 ; C4$CBB49/CBB2.2@7646.2,8645.3 7644.6,8643.7 C3$CBB49/CBB2.2@7602.7,8643.7
$1I15\$1I4\$2N1: C1$CBB49/CBB3.2 C2$CBB49/CBB3.2 Q5$CBB49/CBB3.1 Q6$CBB49/CBB3.2 R1$CBB49/CBB3.2 | length 252
  Top Layer w7.9: C2$CBB49/CBB3.2@7446.2,7860.3 7447.7,7858.7 C1$CBB49/CBB3.2@7489.6,7858.7 ; R1$CBB49/CBB3.2@7489.1,7818.7 7489.6,7819.2 C1$CBB49/CBB3.2@7489.6,7858.7 ; Q5$CBB49/CBB3.1@7573.8,7949.3 Q6$CBB49/CBB3.2@7523.6,7949.3 7501.8,7949.3 7489.6,7937.2 C1$CBB49/CBB3.2@7489.6,7858.7
$1I15\$1I4\$2N14: C3$CBB49/CBB3.2 C4$CBB49/CBB3.2 Q8$CBB49/CBB3.1 Q9$CBB49/CBB3.2 R2$CBB49/CBB3.2 | length 329.2
  Top Layer w7.9: Q9$CBB49/CBB3.2@7523.6,8034.3 Q8$CBB49/CBB3.1@7573.8,8034.3 7611.2,7996.9 7611.2,7867.2 C3$CBB49/CBB3.2@7602.7,7858.7 ; R2$CBB49/CBB3.2@7603.2,7818.7 7603.2,7858.2 C3$CBB49/CBB3.2@7602.7,7858.7 ; C4$CBB49/CBB3.2@7646.2,7860.3 7644.6,7858.7 C3$CBB49/CBB3.2@7602.7,7858.7
$1I15\$1I5\$2N1: C1$CBB49/CBB4.2 C2$CBB49/CBB4.2 Q5$CBB49/CBB4.1 Q6$CBB49/CBB4.2 R1$CBB49/CBB4.2 | length 252
  Top Layer w7.9: C2$CBB49/CBB4.2@7446.2,7075.3 7447.7,7073.7 C1$CBB49/CBB4.2@7489.6,7073.7 ; R1$CBB49/CBB4.2@7489.1,7033.7 7489.6,7034.2 C1$CBB49/CBB4.2@7489.6,7073.7 ; Q5$CBB49/CBB4.1@7573.8,7164.3 Q6$CBB49/CBB4.2@7523.6,7164.3 7501.8,7164.3 7489.6,7152.2 C1$CBB49/CBB4.2@7489.6,7073.7
$1I15\$1I5\$2N14: C3$CBB49/CBB4.2 C4$CBB49/CBB4.2 Q8$CBB49/CBB4.1 Q9$CBB49/CBB4.2 R2$CBB49/CBB4.2 | length 329.2
  Top Layer w7.9: Q9$CBB49/CBB4.2@7523.6,7249.3 Q8$CBB49/CBB4.1@7573.8,7249.3 7611.2,7211.9 7611.2,7082.2 C3$CBB49/CBB4.2@7602.7,7073.7 ; R2$CBB49/CBB4.2@7603.2,7033.7 7603.2,7073.2 C3$CBB49/CBB4.2@7602.7,7073.7 ; C4$CBB49/CBB4.2@7646.2,7075.3 7644.6,7073.7 C3$CBB49/CBB4.2@7602.7,7073.7
$1I15\$1I6\$2N1: C1$CBB49/CBB5.2 C2$CBB49/CBB5.2 Q5$CBB49/CBB5.1 Q6$CBB49/CBB5.2 R1$CBB49/CBB5.2 | length 252
  Top Layer w7.9: C2$CBB49/CBB5.2@7446.2,6555.3 7447.7,6553.7 C1$CBB49/CBB5.2@7489.6,6553.7 ; R1$CBB49/CBB5.2@7489.1,6513.7 7489.6,6514.2 C1$CBB49/CBB5.2@7489.6,6553.7 ; Q5$CBB49/CBB5.1@7573.8,6644.3 Q6$CBB49/CBB5.2@7523.6,6644.3 7501.8,6644.3 7489.6,6632.2 C1$CBB49/CBB5.2@7489.6,6553.7
$1I15\$1I6\$2N14: C3$CBB49/CBB5.2 C4$CBB49/CBB5.2 Q8$CBB49/CBB5.1 Q9$CBB49/CBB5.2 R2$CBB49/CBB5.2 | length 329.2
  Top Layer w7.9: Q9$CBB49/CBB5.2@7523.6,6729.3 Q8$CBB49/CBB5.1@7573.8,6729.3 7611.2,6691.9 7611.2,6562.2 C3$CBB49/CBB5.2@7602.7,6553.7 ; R2$CBB49/CBB5.2@7603.2,6513.7 7603.2,6553.2 C3$CBB49/CBB5.2@7602.7,6553.7 ; C4$CBB49/CBB5.2@7646.2,6555.3 7644.6,6553.7 C3$CBB49/CBB5.2@7602.7,6553.7
$1I15\$1I7\$2N1: C1$CBB49/CBB6.2 C2$CBB49/CBB6.2 Q5$CBB49/CBB6.1 Q6$CBB49/CBB6.2 R1$CBB49/CBB6.2 | length 252
  Top Layer w7.9: C2$CBB49/CBB6.2@7446.2,5770.3 7447.7,5768.7 C1$CBB49/CBB6.2@7489.6,5768.7 ; R1$CBB49/CBB6.2@7489.1,5728.7 7489.6,5729.2 C1$CBB49/CBB6.2@7489.6,5768.7 ; Q5$CBB49/CBB6.1@7573.8,5859.3 Q6$CBB49/CBB6.2@7523.6,5859.3 7501.8,5859.3 7489.6,5847.2 C1$CBB49/CBB6.2@7489.6,5768.7
$1I15\$1I7\$2N14: C3$CBB49/CBB6.2 C4$CBB49/CBB6.2 Q8$CBB49/CBB6.1 Q9$CBB49/CBB6.2 R2$CBB49/CBB6.2 | length 329.2
  Top Layer w7.9: Q9$CBB49/CBB6.2@7523.6,5944.3 Q8$CBB49/CBB6.1@7573.8,5944.3 7611.2,5906.9 7611.2,5777.2 C3$CBB49/CBB6.2@7602.7,5768.7 ; R2$CBB49/CBB6.2@7603.2,5728.7 7603.2,5768.2 C3$CBB49/CBB6.2@7602.7,5768.7 ; C4$CBB49/CBB6.2@7646.2,5770.3 7644.6,5768.7 C3$CBB49/CBB6.2@7602.7,5768.7
$1I15\$1I8\$2N1: C1$CBB49/CBB7.2 C2$CBB49/CBB7.2 Q5$CBB49/CBB7.1 Q6$CBB49/CBB7.2 R1$CBB49/CBB7.2 | length 252
  Top Layer w7.9: C2$CBB49/CBB7.2@7954.9,9165.3 7956.4,9163.7 C1$CBB49/CBB7.2@7998.3,9163.7 ; R1$CBB49/CBB7.2@7997.8,9123.7 7998.3,9124.2 C1$CBB49/CBB7.2@7998.3,9163.7 ; Q5$CBB49/CBB7.1@8082.5,9254.3 Q6$CBB49/CBB7.2@8032.3,9254.3 8010.5,9254.3 7998.3,9242.2 C1$CBB49/CBB7.2@7998.3,9163.7
$1I15\$1I8\$2N14: C3$CBB49/CBB7.2 C4$CBB49/CBB7.2 Q8$CBB49/CBB7.1 Q9$CBB49/CBB7.2 R2$CBB49/CBB7.2 | length 329.2
  Top Layer w7.9: Q9$CBB49/CBB7.2@8032.3,9339.3 Q8$CBB49/CBB7.1@8082.5,9339.3 8119.9,9301.9 8119.9,9172.2 C3$CBB49/CBB7.2@8111.4,9163.7 ; R2$CBB49/CBB7.2@8111.9,9123.7 8111.9,9163.2 C3$CBB49/CBB7.2@8111.4,9163.7 ; C4$CBB49/CBB7.2@8154.9,9165.3 8153.3,9163.7 C3$CBB49/CBB7.2@8111.4,9163.7
$1I15\$1I9\$2N1: C1$CBB49/CBB8.2 C2$CBB49/CBB8.2 Q5$CBB49/CBB8.1 Q6$CBB49/CBB8.2 R1$CBB49/CBB8.2 | length 252
  Top Layer w7.9: C2$CBB49/CBB8.2@7954.9,8645.3 7956.4,8643.7 C1$CBB49/CBB8.2@7998.3,8643.7 ; R1$CBB49/CBB8.2@7997.8,8603.7 7998.3,8604.2 C1$CBB49/CBB8.2@7998.3,8643.7 ; Q5$CBB49/CBB8.1@8082.5,8734.3 Q6$CBB49/CBB8.2@8032.3,8734.3 8010.5,8734.3 7998.3,8722.2 C1$CBB49/CBB8.2@7998.3,8643.7
$1I15\$1I9\$2N14: C3$CBB49/CBB8.2 C4$CBB49/CBB8.2 Q8$CBB49/CBB8.1 Q9$CBB49/CBB8.2 R2$CBB49/CBB8.2 | length 329.2
  Top Layer w7.9: Q9$CBB49/CBB8.2@8032.3,8819.3 Q8$CBB49/CBB8.1@8082.5,8819.3 8119.9,8781.9 8119.9,8652.2 C3$CBB49/CBB8.2@8111.4,8643.7 ; R2$CBB49/CBB8.2@8111.9,8603.7 8111.9,8643.2 C3$CBB49/CBB8.2@8111.4,8643.7 ; C4$CBB49/CBB8.2@8154.9,8645.3 8153.3,8643.7 C3$CBB49/CBB8.2@8111.4,8643.7
$1I15\$1I10\$2N1: C1$CBB49/CBB9.2 C2$CBB49/CBB9.2 Q5$CBB49/CBB9.1 Q6$CBB49/CBB9.2 R1$CBB49/CBB9.2 | length 252
  Top Layer w7.9: C2$CBB49/CBB9.2@7954.9,7860.3 7956.4,7858.7 C1$CBB49/CBB9.2@7998.3,7858.7 ; R1$CBB49/CBB9.2@7997.8,7818.7 7998.3,7819.2 C1$CBB49/CBB9.2@7998.3,7858.7 ; Q5$CBB49/CBB9.1@8082.5,7949.3 Q6$CBB49/CBB9.2@8032.3,7949.3 8010.5,7949.3 7998.3,7937.2 C1$CBB49/CBB9.2@7998.3,7858.7
$1I15\$1I10\$2N14: C3$CBB49/CBB9.2 C4$CBB49/CBB9.2 Q8$CBB49/CBB9.1 Q9$CBB49/CBB9.2 R2$CBB49/CBB9.2 | length 329.2
  Top Layer w7.9: Q9$CBB49/CBB9.2@8032.3,8034.3 Q8$CBB49/CBB9.1@8082.5,8034.3 8119.9,7996.9 8119.9,7867.2 C3$CBB49/CBB9.2@8111.4,7858.7 ; R2$CBB49/CBB9.2@8111.9,7818.7 8111.9,7858.2 C3$CBB49/CBB9.2@8111.4,7858.7 ; C4$CBB49/CBB9.2@8154.9,7860.3 8153.3,7858.7 C3$CBB49/CBB9.2@8111.4,7858.7
$1I15\$1I11\$2N1: C1$CBB49/CBB10.2 C2$CBB49/CBB10.2 Q5$CBB49/CBB10.1 Q6$CBB49/CBB10.2 R1$CBB49/CBB10.2 | length 252
  Top Layer w7.9: C2$CBB49/CBB10.2@7954.9,7075.3 7956.4,7073.7 C1$CBB49/CBB10.2@7998.3,7073.7 ; R1$CBB49/CBB10.2@7997.8,7033.7 7998.3,7034.2 C1$CBB49/CBB10.2@7998.3,7073.7 ; Q5$CBB49/CBB10.1@8082.5,7164.3 Q6$CBB49/CBB10.2@8032.3,7164.3 8010.5,7164.3 7998.3,7152.2 C1$CBB49/CBB10.2@7998.3,7073.7
$1I15\$1I11\$2N14: C3$CBB49/CBB10.2 C4$CBB49/CBB10.2 Q8$CBB49/CBB10.1 Q9$CBB49/CBB10.2 R2$CBB49/CBB10.2 | length 329.2
  Top Layer w7.9: Q9$CBB49/CBB10.2@8032.3,7249.3 Q8$CBB49/CBB10.1@8082.5,7249.3 8119.9,7211.9 8119.9,7082.2 C3$CBB49/CBB10.2@8111.4,7073.7 ; R2$CBB49/CBB10.2@8111.9,7033.7 8111.9,7073.2 C3$CBB49/CBB10.2@8111.4,7073.7 ; C4$CBB49/CBB10.2@8154.9,7075.3 8153.3,7073.7 C3$CBB49/CBB10.2@8111.4,7073.7
$1I15\$1I12\$2N1: C1$CBB49/CBB11.2 C2$CBB49/CBB11.2 Q5$CBB49/CBB11.1 Q6$CBB49/CBB11.2 R1$CBB49/CBB11.2 | length 252
  Top Layer w7.9: C2$CBB49/CBB11.2@7954.9,6555.3 7956.4,6553.7 C1$CBB49/CBB11.2@7998.3,6553.7 ; R1$CBB49/CBB11.2@7997.8,6513.7 7998.3,6514.2 C1$CBB49/CBB11.2@7998.3,6553.7 ; Q5$CBB49/CBB11.1@8082.5,6644.3 Q6$CBB49/CBB11.2@8032.3,6644.3 8010.5,6644.3 7998.3,6632.2 C1$CBB49/CBB11.2@7998.3,6553.7
$1I15\$1I12\$2N14: C3$CBB49/CBB11.2 C4$CBB49/CBB11.2 Q8$CBB49/CBB11.1 Q9$CBB49/CBB11.2 R2$CBB49/CBB11.2 | length 329.2
  Top Layer w7.9: Q9$CBB49/CBB11.2@8032.3,6729.3 Q8$CBB49/CBB11.1@8082.5,6729.3 8119.9,6691.9 8119.9,6562.2 C3$CBB49/CBB11.2@8111.4,6553.7 ; R2$CBB49/CBB11.2@8111.9,6513.7 8111.9,6553.2 C3$CBB49/CBB11.2@8111.4,6553.7 ; C4$CBB49/CBB11.2@8154.9,6555.3 8153.3,6553.7 C3$CBB49/CBB11.2@8111.4,6553.7
$1I15\$1I13\$2N1: C1$CBB49/CBB12.2 C2$CBB49/CBB12.2 Q5$CBB49/CBB12.1 Q6$CBB49/CBB12.2 R1$CBB49/CBB12.2 | length 252
  Top Layer w7.9: C2$CBB49/CBB12.2@7954.9,5770.3 7956.4,5768.7 C1$CBB49/CBB12.2@7998.3,5768.7 ; R1$CBB49/CBB12.2@7997.8,5728.7 7998.3,5729.2 C1$CBB49/CBB12.2@7998.3,5768.7 ; Q5$CBB49/CBB12.1@8082.5,5859.3 Q6$CBB49/CBB12.2@8032.3,5859.3 8010.5,5859.3 7998.3,5847.2 C1$CBB49/CBB12.2@7998.3,5768.7
$1I15\$1I13\$2N14: C3$CBB49/CBB12.2 C4$CBB49/CBB12.2 Q8$CBB49/CBB12.1 Q9$CBB49/CBB12.2 R2$CBB49/CBB12.2 | length 329.2
  Top Layer w7.9: Q9$CBB49/CBB12.2@8032.3,5944.3 Q8$CBB49/CBB12.1@8082.5,5944.3 8119.9,5906.9 8119.9,5777.2 C3$CBB49/CBB12.2@8111.4,5768.7 ; R2$CBB49/CBB12.2@8111.9,5728.7 8111.9,5768.2 C3$CBB49/CBB12.2@8111.4,5768.7 ; C4$CBB49/CBB12.2@8154.9,5770.3 8153.3,5768.7 C3$CBB49/CBB12.2@8111.4,5768.7
$1I15\$1I14\$2N1: C1$CBB49/CBB13.2 C2$CBB49/CBB13.2 Q5$CBB49/CBB13.1 Q6$CBB49/CBB13.2 R1$CBB49/CBB13.2 | length 251.9
  Top Layer w7.9: C2$CBB49/CBB13.2@8463.6,9165.2 8465.1,9163.7 C1$CBB49/CBB13.2@8507,9163.7 ; R1$CBB49/CBB13.2@8506.5,9123.7 8507,9124.2 C1$CBB49/CBB13.2@8507,9163.7 ; Q5$CBB49/CBB13.1@8591.2,9254.3 Q6$CBB49/CBB13.2@8541,9254.3 8519.2,9254.3 8507,9242.2 C1$CBB49/CBB13.2@8507,9163.7
$1I15\$1I14\$2N14: C3$CBB49/CBB13.2 C4$CBB49/CBB13.2 Q8$CBB49/CBB13.1 Q9$CBB49/CBB13.2 R2$CBB49/CBB13.2 | length 329.1
  Top Layer w7.9: Q9$CBB49/CBB13.2@8541,9339.3 Q8$CBB49/CBB13.1@8591.2,9339.3 8628.6,9301.9 8628.6,9172.2 C3$CBB49/CBB13.2@8620.1,9163.7 ; R2$CBB49/CBB13.2@8620.6,9123.7 8620.6,9163.2 C3$CBB49/CBB13.2@8620.1,9163.7 ; C4$CBB49/CBB13.2@8663.6,9165.2 8662,9163.7 C3$CBB49/CBB13.2@8620.1,9163.7
$1I15\$1I15\$2N1: C1$CBB49/CBB14.2 C2$CBB49/CBB14.2 Q5$CBB49/CBB14.1 Q6$CBB49/CBB14.2 R1$CBB49/CBB14.2 | length 251.9
  Top Layer w7.9: C2$CBB49/CBB14.2@8463.6,8645.2 8465.1,8643.7 C1$CBB49/CBB14.2@8507,8643.7 ; R1$CBB49/CBB14.2@8506.5,8603.7 8507,8604.2 C1$CBB49/CBB14.2@8507,8643.7 ; Q5$CBB49/CBB14.1@8591.2,8734.3 Q6$CBB49/CBB14.2@8541,8734.3 8519.2,8734.3 8507,8722.2 C1$CBB49/CBB14.2@8507,8643.7
$1I15\$1I15\$2N14: C3$CBB49/CBB14.2 C4$CBB49/CBB14.2 Q8$CBB49/CBB14.1 Q9$CBB49/CBB14.2 R2$CBB49/CBB14.2 | length 329.1
  Top Layer w7.9: Q9$CBB49/CBB14.2@8541,8819.3 Q8$CBB49/CBB14.1@8591.2,8819.3 8628.6,8781.9 8628.6,8652.2 C3$CBB49/CBB14.2@8620.1,8643.7 ; R2$CBB49/CBB14.2@8620.6,8603.7 8620.6,8643.2 C3$CBB49/CBB14.2@8620.1,8643.7 ; C4$CBB49/CBB14.2@8663.6,8645.2 8662,8643.7 C3$CBB49/CBB14.2@8620.1,8643.7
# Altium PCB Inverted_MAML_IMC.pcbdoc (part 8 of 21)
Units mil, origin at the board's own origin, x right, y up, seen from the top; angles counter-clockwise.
Board outline 7677.1 x 6771.6 mil, 6 copper layers (Top Layer, Inner1, Inner2, Inner3, Inner4, Bottom Layer), stack 60.7 mil thick; 2730 components, 1566 nets, 7761 pads, 3719 vias.

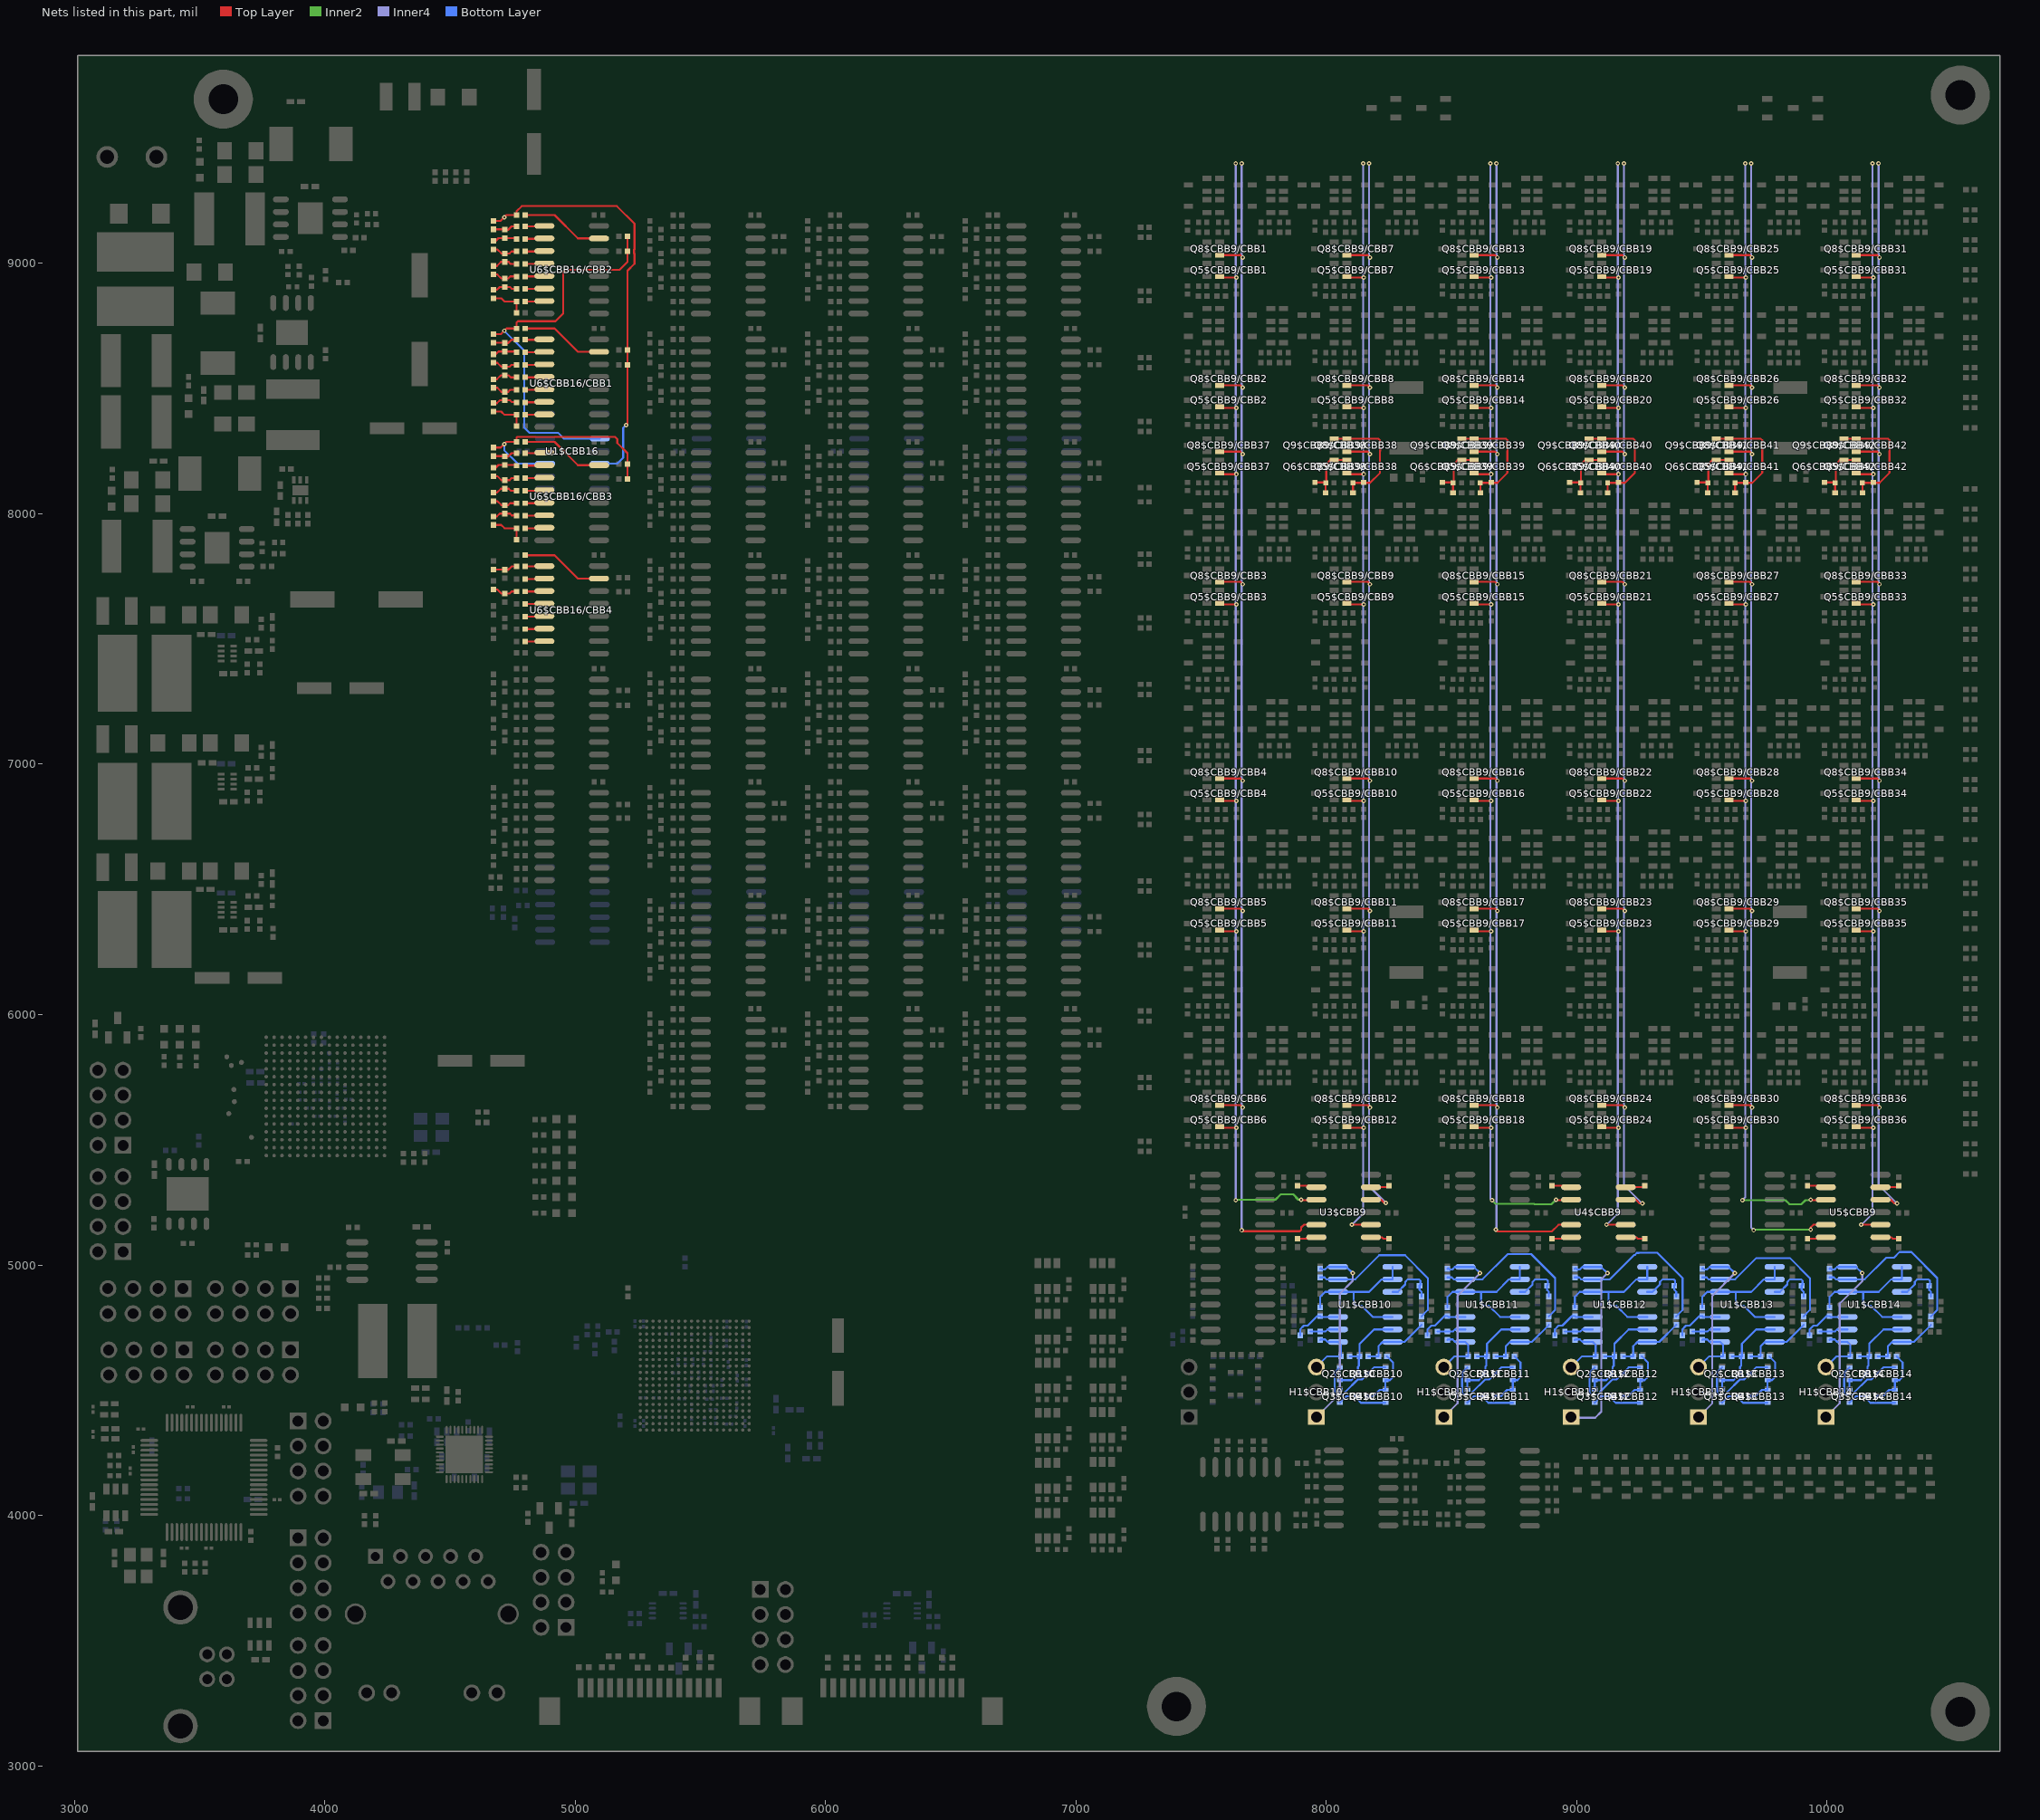
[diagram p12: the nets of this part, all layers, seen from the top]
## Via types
v1: diameter 17.7, hole 7.9, Top Layer to Bottom Layer, 3387 vias
v2: diameter 13.8, hole 7.9, Top Layer to Bottom Layer, 287 vias
v3: diameter 23.6, hole 11.8, Top Layer to Bottom Layer, 45 vias

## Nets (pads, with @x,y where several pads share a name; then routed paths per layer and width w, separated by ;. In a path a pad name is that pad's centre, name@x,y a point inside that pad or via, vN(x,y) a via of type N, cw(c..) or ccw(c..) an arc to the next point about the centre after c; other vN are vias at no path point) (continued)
$1I25\$1I39\$2N1: C1$CBB9/CBB38.2 C2$CBB9/CBB38.2 Q5$CBB9/CBB38.1 Q6$CBB9/CBB38.2 R1$CBB9/CBB38.2 | length 249
  Top Layer w7.9: C2$CBB9/CBB38.2@7954.9,8125.3 7996.8,8125.3 C1$CBB9/CBB38.2@7998.3,8123.7 ; R1$CBB9/CBB38.2@7997.8,8083.7 7997.8,8123.2 C1$CBB9/CBB38.2@7998.3,8123.7 ; Q5$CBB9/CBB38.1@8082.5,8214.3 Q6$CBB9/CBB38.2@8032.3,8214.3 8015.5,8214.3 7999.9,8198.7 7999.9,8125.3 C1$CBB9/CBB38.2@7998.3,8123.7
$1I25\$1I39\$2N14: C3$CBB9/CBB38.2 C4$CBB9/CBB38.2 Q8$CBB9/CBB38.1 Q9$CBB9/CBB38.2 R2$CBB9/CBB38.2 | length 481.8
  Top Layer w7.9: Q9$CBB9/CBB38.2@8032.3,8299.3 Q8$CBB9/CBB38.1@8082.5,8299.3 8209.3,8299.3 8214.9,8293.7 8214.9,8266.4 8215.2,8266.1 8215.2,8251.4 8214.9,8251.1 8214.9,8163.7 8174.9,8123.7 8151.4,8123.7 C4$CBB9/CBB38.2@8149.9,8125.3 8148.3,8123.7 C3$CBB9/CBB38.2@8106.4,8123.7 8106.9,8123.2 R2$CBB9/CBB38.2@8106.9,8083.7
$1I25\$1I40\$2N1: C1$CBB9/CBB39.2 C2$CBB9/CBB39.2 Q5$CBB9/CBB39.1 Q6$CBB9/CBB39.2 R1$CBB9/CBB39.2 | length 249
  Top Layer w7.9: C2$CBB9/CBB39.2@8463.6,8125.2 8505.5,8125.2 C1$CBB9/CBB39.2@8507,8123.7 ; R1$CBB9/CBB39.2@8506.5,8083.7 8506.5,8123.2 C1$CBB9/CBB39.2@8507,8123.7 ; Q5$CBB9/CBB39.1@8591.2,8214.3 Q6$CBB9/CBB39.2@8541,8214.3 8524.2,8214.3 8508.6,8198.7 8508.6,8125.2 C1$CBB9/CBB39.2@8507,8123.7
$1I25\$1I40\$2N14: C3$CBB9/CBB39.2 C4$CBB9/CBB39.2 Q8$CBB9/CBB39.1 Q9$CBB9/CBB39.2 R2$CBB9/CBB39.2 | length 481.7
  Top Layer w7.9: Q9$CBB9/CBB39.2@8541,8299.3 Q8$CBB9/CBB39.1@8591.2,8299.3 8718,8299.3 8723.6,8293.7 8723.6,8266.3 8723.9,8266.1 8723.9,8251.3 8723.6,8251 8723.6,8163.7 8683.6,8123.7 8660.1,8123.7 8658.6,8125.2 8657,8123.7 C3$CBB9/CBB39.2@8615.1,8123.7 8615.6,8123.2 R2$CBB9/CBB39.2@8615.6,8083.7
$1I25\$1I41\$2N1: C1$CBB9/CBB40.2 C2$CBB9/CBB40.2 Q5$CBB9/CBB40.1 Q6$CBB9/CBB40.2 R1$CBB9/CBB40.2 | length 249
  Top Layer w7.9: C2$CBB9/CBB40.2@8972.3,8125.3 9014.2,8125.3 C1$CBB9/CBB40.2@9015.7,8123.7 ; R1$CBB9/CBB40.2@9015.2,8083.7 9015.2,8123.2 C1$CBB9/CBB40.2@9015.7,8123.7 ; Q5$CBB9/CBB40.1@9099.9,8214.3 Q6$CBB9/CBB40.2@9049.7,8214.3 9032.9,8214.3 9017.3,8198.7 9017.3,8125.3 C1$CBB9/CBB40.2@9015.7,8123.7
$1I25\$1I41\$2N14: C3$CBB9/CBB40.2 C4$CBB9/CBB40.2 Q8$CBB9/CBB40.1 Q9$CBB9/CBB40.2 R2$CBB9/CBB40.2 | length 481.8
  Top Layer w7.9: Q9$CBB9/CBB40.2@9049.7,8299.3 Q8$CBB9/CBB40.1@9099.9,8299.3 9226.7,8299.3 9232.3,8293.7 9232.3,8266.4 9232.6,8266.1 9232.6,8251.4 9232.3,8251.1 9232.3,8163.7 9192.3,8123.7 9168.8,8123.7 C4$CBB9/CBB40.2@9167.3,8125.3 9165.7,8123.7 C3$CBB9/CBB40.2@9123.8,8123.7 9124.3,8123.2 R2$CBB9/CBB40.2@9124.3,8083.7
$1I25\$1I42\$2N1: C1$CBB9/CBB41.2 C2$CBB9/CBB41.2 Q5$CBB9/CBB41.1 Q6$CBB9/CBB41.2 R1$CBB9/CBB41.2 | length 249
  Top Layer w7.9: C2$CBB9/CBB41.2@9481,8125.3 9522.9,8125.3 C1$CBB9/CBB41.2@9524.4,8123.7 ; R1$CBB9/CBB41.2@9523.9,8083.7 9523.9,8123.2 C1$CBB9/CBB41.2@9524.4,8123.7 ; Q5$CBB9/CBB41.1@9608.6,8214.3 Q6$CBB9/CBB41.2@9558.4,8214.3 9541.6,8214.3 9526,8198.7 9526,8125.3 C1$CBB9/CBB41.2@9524.4,8123.7
$1I25\$1I42\$2N14: C3$CBB9/CBB41.2 C4$CBB9/CBB41.2 Q8$CBB9/CBB41.1 Q9$CBB9/CBB41.2 R2$CBB9/CBB41.2 | length 481.8
  Top Layer w7.9: Q9$CBB9/CBB41.2@9558.4,8299.3 Q8$CBB9/CBB41.1@9608.6,8299.3 9735.4,8299.3 9741,8293.7 9741,8266.4 9741.3,8266.1 9741.3,8251.4 9741,8251.1 9741,8163.7 9701,8123.7 9677.5,8123.7 C4$CBB9/CBB41.2@9676,8125.3 9674.4,8123.7 C3$CBB9/CBB41.2@9632.5,8123.7 9633,8123.2 R2$CBB9/CBB41.2@9633,8083.7
$1I25\$1I43\$2N1: C1$CBB9/CBB42.2 C2$CBB9/CBB42.2 Q5$CBB9/CBB42.1 Q6$CBB9/CBB42.2 R1$CBB9/CBB42.2 | length 249
  Top Layer w7.9: C2$CBB9/CBB42.2@9989.7,8125.3 10031.6,8125.3 C1$CBB9/CBB42.2@10033.1,8123.7 ; R1$CBB9/CBB42.2@10032.6,8083.7 10032.6,8123.2 C1$CBB9/CBB42.2@10033.1,8123.7 ; Q5$CBB9/CBB42.1@10117.3,8214.3 Q6$CBB9/CBB42.2@10067.1,8214.3 10050.3,8214.3 10034.7,8198.7 10034.7,8125.3 C1$CBB9/CBB42.2@10033.1,8123.7
$1I25\$1I43\$2N14: C3$CBB9/CBB42.2 C4$CBB9/CBB42.2 Q8$CBB9/CBB42.1 Q9$CBB9/CBB42.2 R2$CBB9/CBB42.2 | length 481.8
  Top Layer w7.9: Q9$CBB9/CBB42.2@10067.1,8299.3 Q8$CBB9/CBB42.1@10117.3,8299.3 10244.1,8299.3 10249.7,8293.7 10249.7,8266.4 10250,8266.1 10250,8251.4 10249.7,8251.1 10249.7,8163.7 10209.7,8123.7 10186.2,8123.7 C4$CBB9/CBB42.2@10184.7,8125.3 10183.1,8123.7 C3$CBB9/CBB42.2@10141.2,8123.7 10141.7,8123.2 R2$CBB9/CBB42.2@10141.7,8083.7
$1I25\$1N247: R3$CBB9.2 U3$CBB9.2 | length 74.6
  Top Layer w7.9: R3$CBB9.2@7888.3,5316.3 7954.8,5316.3 U3$CBB9.2@7960.6,5310.6
$1I25\$1N248: R4$CBB9.2 U3$CBB9.6 | length 74.5
  Top Layer w7.9: R4$CBB9.2@7888.3,5105.4 7955.4,5105.4 U3$CBB9.6@7960.6,5110.6
$1I25\$1N249: R5$CBB9.2 U3$CBB9.9 | length 76.9
  Top Layer w7.9: U3$CBB9.9@8178.6,5110.6 8221.7,5110.6 8226.9,5105.4 R5$CBB9.2@8253.3,5105.4
$1I25\$1N250: R6$CBB9.2 U3$CBB9.13 | length 80
  Top Layer w7.9: U3$CBB9.13@8178.6,5310.6 8247.5,5310.6 8253.3,5316.3 R6$CBB9.2@8250.3,5316.3
$1I25\$1N251: R9$CBB9.2 U4$CBB9.9 | length 76.9
  Top Layer w7.9: U4$CBB9.9@9196,5110.6 9239.1,5110.6 9244.3,5105.4 R9$CBB9.2@9270.7,5105.4
$1I25\$1N252: R8$CBB9.2 U4$CBB9.6 | length 74.5
  Top Layer w7.9: R8$CBB9.2@8905.7,5105.4 8972.8,5105.4 U4$CBB9.6@8978,5110.6
$1I25\$1N253: R7$CBB9.2 U4$CBB9.2 | length 74.6
  Top Layer w7.9: R7$CBB9.2@8905.7,5316.3 8972.2,5316.3 U4$CBB9.2@8978,5310.6
$1I25\$1N254: R10$CBB9.2 U4$CBB9.13 | length 80
  Top Layer w7.9: U4$CBB9.13@9196,5310.6 9264.9,5310.6 9270.7,5316.3 R10$CBB9.2@9267.7,5316.3
$1I25\$1N255: R13$CBB9.2 U5$CBB9.9 | length 76.9
  Top Layer w7.9: U5$CBB9.9@10213.4,5110.6 10256.5,5110.6 10261.7,5105.4 R13$CBB9.2@10288.1,5105.4
$1I25\$1N256: R12$CBB9.2 U5$CBB9.6 | length 74.5
  Top Layer w7.9: R12$CBB9.2@9923.1,5105.4 9990.2,5105.4 U5$CBB9.6@9995.4,5110.6
$1I25\$1N257: R11$CBB9.2 U5$CBB9.2 | length 74.6
  Top Layer w7.9: R11$CBB9.2@9923.1,5316.3 9989.6,5316.3 U5$CBB9.2@9995.4,5310.6
$1I25\$1N258: R14$CBB9.2 U5$CBB9.13 | length 80
  Top Layer w7.9: U5$CBB9.13@10213.4,5310.6 10282.3,5310.6 10288.1,5316.3 R14$CBB9.2@10285.1,5316.3
$1I25\M8_COL+1: Q5$CBB9/CBB1.2 Q5$CBB9/CBB2.2 Q5$CBB9/CBB3.2 Q5$CBB9/CBB4.2 Q5$CBB9/CBB5.2 Q5$CBB9/CBB6.2 Q5$CBB9/CBB37.2 U3$CBB9.3 | length 5007.7
  Top Layer w7.9: Q5$CBB9/CBB6.2@7573.8,5553.2 7578.8,5548.2 v1(7641.2,5548.2) ; Q5$CBB9/CBB5.2@7573.8,6338.2 7578.8,6333.2 v1(7641.2,6333.2) ; Q5$CBB9/CBB4.2@7573.8,6858.2 7578.8,6853.2 v1(7641.2,6853.2) ; Q5$CBB9/CBB3.2@7573.8,7643.2 7578.8,7638.2 v1(7641.2,7638.2) ; Q5$CBB9/CBB37.2@7573.8,8163.2 7578.8,8158.2 v1(7641.2,8158.2) ; Q5$CBB9/CBB2.2@7573.8,8428.2 7578.8,8423.2 v1(7641.2,8423.2) ; Q5$CBB9/CBB1.2@7573.8,8948.2 7578.8,8943.2 v1(7641.2,8943.2) ; v1(7900.1,5260.6) 7901.7,5259 7959,5259 U3$CBB9.3@7960.6,5260.6
  Inner2 w7.9: v1(7638.6,5258.7) 7640.4,5260.6 7797,5260.6 7818.8,5282.5 7867,5282.5 7888.9,5260.6 v1(7900.1,5260.6)
  Inner4 w7.9: v1(7638.6,5258.7) v1@7638.6,5552.7 ; v1(7638.6,9398.7) v1@7638.6,8947.7 ; v1(7641.2,5548.2) 7641.2,5550.1 v1@7638.6,5552.7 ; v1(7641.2,6333.2) 7641.2,6335.1 v1@7638.6,6337.7 ; v1(7641.2,6853.2) 7641.2,6855.1 v1@7638.6,6857.7 ; v1(7641.2,7638.2) 7641.2,7640.1 v1@7638.6,7642.7 ; v1(7641.2,8158.2) 7641.2,8160.1 v1@7638.6,8162.7 ; v1(7641.2,8423.2) 7641.2,8425.1 v1@7638.6,8427.7 ; v1(7641.2,8943.2) 7641.2,8945.1 v1@7638.6,8947.7 ; v1@7638.6,5552.7 v1@7638.6,6337.7 ; v1@7638.6,6337.7 v1@7638.6,6857.7 ; v1@7638.6,6857.7 v1@7638.6,7642.7 ; v1@7638.6,7642.7 v1@7638.6,8162.7 ; v1@7638.6,8162.7 v1@7638.6,8427.7 ; v1@7638.6,8427.7 v1@7638.6,8947.7
$1I25\M8_COL+2: Q5$CBB9/CBB7.2 Q5$CBB9/CBB8.2 Q5$CBB9/CBB9.2 Q5$CBB9/CBB10.2 Q5$CBB9/CBB11.2 Q5$CBB9/CBB12.2 Q5$CBB9/CBB38.2 U3$CBB9.10 | length 4858.7
  Top Layer w7.9: Q5$CBB9/CBB12.2@8082.5,5553.2 8087.5,5548.2 v1(8149.9,5548.2) ; Q5$CBB9/CBB11.2@8082.5,6338.2 8087.5,6333.2 v1(8149.9,6333.2) ; Q5$CBB9/CBB10.2@8082.5,6858.2 8087.5,6853.2 v1(8149.9,6853.2) ; Q5$CBB9/CBB9.2@8082.5,7643.2 8087.5,7638.2 v1(8149.9,7638.2) ; Q5$CBB9/CBB38.2@8082.5,8163.2 8087.5,8158.2 v1(8149.9,8158.2) ; Q5$CBB9/CBB8.2@8082.5,8428.2 8087.5,8423.2 v1(8149.9,8423.2) ; Q5$CBB9/CBB7.2@8082.5,8948.2 8087.5,8943.2 v1(8149.9,8943.2) ; v1(8102.1,5160.6) U3$CBB9.10@8178.6,5160.6
  Inner4 w7.9: v1(8102.1,5160.6) 8147.3,5205.7 v1@8147.3,5552.7 ; v1(8147.3,9398.7) v1@8147.3,8947.7 ; v1(8149.9,5548.2) 8149.9,5550.1 v1@8147.3,5552.7 ; v1(8149.9,6333.2) 8149.9,6335.1 v1@8147.3,6337.7 ; v1(8149.9,6853.2) 8149.9,6855.1 v1@8147.3,6857.7 ; v1(8149.9,7638.2) 8149.9,7640.1 v1@8147.3,7642.7 ; v1(8149.9,8158.2) 8149.9,8160.1 v1@8147.3,8162.7 ; v1(8149.9,8423.2) 8149.9,8425.1 v1@8147.3,8427.7 ; v1(8149.9,8943.2) 8149.9,8945.1 v1@8147.3,8947.7 ; v1@8147.3,5552.7 v1@8147.3,6337.7 ; v1@8147.3,6337.7 v1@8147.3,6857.7 ; v1@8147.3,6857.7 v1@8147.3,7642.7 ; v1@8147.3,7642.7 v1@8147.3,8162.7 ; v1@8147.3,8162.7 v1@8147.3,8427.7 ; v1@8147.3,8427.7 v1@8147.3,8947.7
$1I25\M8_COL+3: Q5$CBB9/CBB13.2 Q5$CBB9/CBB14.2 Q5$CBB9/CBB15.2 Q5$CBB9/CBB16.2 Q5$CBB9/CBB17.2 Q5$CBB9/CBB18.2 Q5$CBB9/CBB39.2 U4$CBB9.3 | length 4999
  Top Layer w7.9: Q5$CBB9/CBB18.2@8591.2,5553.1 8596.2,5548.1 v1(8658.6,5548.1) ; Q5$CBB9/CBB17.2@8591.2,6338.1 8596.2,6333.1 v1(8658.6,6333.1) ; Q5$CBB9/CBB16.2@8591.2,6858.1 8596.2,6853.1 v1(8658.6,6853.1) ; Q5$CBB9/CBB15.2@8591.2,7643.1 8596.2,7638.1 v1(8658.6,7638.1) ; Q5$CBB9/CBB39.2@8591.2,8163.1 8596.2,8158.1 v1(8658.6,8158.1) ; Q5$CBB9/CBB14.2@8591.2,8428.1 8596.2,8423.1 v1(8658.6,8423.1) ; Q5$CBB9/CBB13.2@8591.2,8948.1 8596.2,8943.1 v1(8658.6,8943.1) ; v1(8917.5,5260.6) 8919.1,5259 8976.4,5259 U4$CBB9.3@8978,5260.6
  Inner2 w7.9: v1(8662.1,5258.7) 8677.1,5243.7 8831.2,5243.7 8832.1,5242.8 8899.7,5242.8 v1(8917.5,5260.6)
  Inner4 w7.9: v1(8656,9398.7) v1@8656,8947.6 ; v1(8658.6,5548.1) 8658.6,5550 v1@8656,5552.6 ; v1(8658.6,6333.1) 8658.6,6335 v1@8656,6337.6 ; v1(8658.6,6853.1) 8658.6,6855 v1@8656,6857.6 ; v1(8658.6,7638.1) 8658.6,7640 v1@8656,7642.6 ; v1(8658.6,8158.1) 8658.6,8160 v1@8656,8162.6 ; v1(8658.6,8423.1) 8658.6,8425 v1@8656,8427.6 ; v1(8658.6,8943.1) 8658.6,8945 v1@8656,8947.6 ; v1(8662.1,5258.7) 8656,5264.9 v1@8656,5552.6 ; v1@8656,5552.6 v1@8656,6337.6 ; v1@8656,6337.6 v1@8656,6857.6 ; v1@8656,6857.6 v1@8656,7642.6 ; v1@8656,7642.6 v1@8656,8162.6 ; v1@8656,8162.6 v1@8656,8427.6 ; v1@8656,8427.6 v1@8656,8947.6
$1I25\M8_COL+4: Q5$CBB9/CBB19.2 Q5$CBB9/CBB20.2 Q5$CBB9/CBB21.2 Q5$CBB9/CBB22.2 Q5$CBB9/CBB23.2 Q5$CBB9/CBB24.2 Q5$CBB9/CBB40.2 U4$CBB9.10 | length 4858.7
  Top Layer w7.9: Q5$CBB9/CBB24.2@9099.9,5553.2 9104.9,5548.2 v1(9167.3,5548.2) ; Q5$CBB9/CBB23.2@9099.9,6338.2 9104.9,6333.2 v1(9167.3,6333.2) ; Q5$CBB9/CBB22.2@9099.9,6858.2 9104.9,6853.2 v1(9167.3,6853.2) ; Q5$CBB9/CBB21.2@9099.9,7643.2 9104.9,7638.2 v1(9167.3,7638.2) ; Q5$CBB9/CBB40.2@9099.9,8163.2 9104.9,8158.2 v1(9167.3,8158.2) ; Q5$CBB9/CBB20.2@9099.9,8428.2 9104.9,8423.2 v1(9167.3,8423.2) ; Q5$CBB9/CBB19.2@9099.9,8948.2 9104.9,8943.2 v1(9167.3,8943.2) ; v1(9119.5,5160.6) U4$CBB9.10@9196,5160.6
  Inner4 w7.9: v1(9119.5,5160.6) 9164.7,5205.8 v1@9164.7,5552.7 ; v1(9164.7,9398.7) v1@9164.7,8947.7 ; v1(9167.3,5548.2) 9167.3,5550.1 v1@9164.7,5552.7 ; v1(9167.3,6333.2) 9167.3,6335.1 v1@9164.7,6337.7 ; v1(9167.3,6853.2) 9167.3,6855.1 v1@9164.7,6857.7 ; v1(9167.3,7638.2) 9167.3,7640.1 v1@9164.7,7642.7 ; v1(9167.3,8158.2) 9167.3,8160.1 v1@9164.7,8162.7 ; v1(9167.3,8423.2) 9167.3,8425.1 v1@9164.7,8427.7 ; v1(9167.3,8943.2) 9167.3,8945.1 v1@9164.7,8947.7 ; v1@9164.7,5552.7 v1@9164.7,6337.7 ; v1@9164.7,6337.7 v1@9164.7,6857.7 ; v1@9164.7,6857.7 v1@9164.7,7642.7 ; v1@9164.7,7642.7 v1@9164.7,8162.7 ; v1@9164.7,8162.7 v1@9164.7,8427.7 ; v1@9164.7,8427.7 v1@9164.7,8947.7
$1I25\M8_COL+5: Q5$CBB9/CBB25.2 Q5$CBB9/CBB26.2 Q5$CBB9/CBB27.2 Q5$CBB9/CBB28.2 Q5$CBB9/CBB29.2 Q5$CBB9/CBB30.2 Q5$CBB9/CBB41.2 U5$CBB9.3 | length 5018.6
  Top Layer w7.9: Q5$CBB9/CBB30.2@9608.6,5553.2 9613.6,5548.2 v1(9676,5548.2) ; Q5$CBB9/CBB29.2@9608.6,6338.2 9613.6,6333.2 v1(9676,6333.2) ; Q5$CBB9/CBB28.2@9608.6,6858.2 9613.6,6853.2 v1(9676,6853.2) ; Q5$CBB9/CBB27.2@9608.6,7643.2 9613.6,7638.2 v1(9676,7638.2) ; Q5$CBB9/CBB41.2@9608.6,8163.2 9613.6,8158.2 v1(9676,8158.2) ; Q5$CBB9/CBB26.2@9608.6,8428.2 9613.6,8423.2 v1(9676,8423.2) ; Q5$CBB9/CBB25.2@9608.6,8948.2 9613.6,8943.2 v1(9676,8943.2) ; v1(9934.9,5260.6) 9936.5,5259 9993.8,5259 U5$CBB9.3@9995.4,5260.6
  Inner2 w7.9: v1(9662.1,5258.7) 9833.6,5258.7 9849.5,5242.8 9897.7,5242.8 9913.7,5258.7 9933.1,5258.7 v1(9934.9,5260.6)
  Inner4 w7.9: v1(9662.1,5258.7) 9673.4,5270 v1@9673.4,5552.7 ; v1(9673.4,9398.7) v1@9673.4,8947.7 ; v1(9676,5548.2) 9676,5550.1 v1@9673.4,5552.7 ; v1(9676,6333.2) 9676,6335.1 v1@9673.4,6337.7 ; v1(9676,6853.2) 9676,6855.1 v1@9673.4,6857.7 ; v1(9676,7638.2) 9676,7640.1 v1@9673.4,7642.7 ; v1(9676,8158.2) 9676,8160.1 v1@9673.4,8162.7 ; v1(9676,8423.2) 9676,8425.1 v1@9673.4,8427.7 ; v1(9676,8943.2) 9676,8945.1 v1@9673.4,8947.7 ; v1@9673.4,5552.7 v1@9673.4,6337.7 ; v1@9673.4,6337.7 v1@9673.4,6857.7 ; v1@9673.4,6857.7 v1@9673.4,7642.7 ; v1@9673.4,7642.7 v1@9673.4,8162.7 ; v1@9673.4,8162.7 v1@9673.4,8427.7 ; v1@9673.4,8427.7 v1@9673.4,8947.7
$1I25\M8_COL+6: Q5$CBB9/CBB31.2 Q5$CBB9/CBB32.2 Q5$CBB9/CBB33.2 Q5$CBB9/CBB34.2 Q5$CBB9/CBB35.2 Q5$CBB9/CBB36.2 Q5$CBB9/CBB42.2 U5$CBB9.10 | length 4858.7
  Top Layer w7.9: Q5$CBB9/CBB36.2@10117.3,5553.2 10122.3,5548.2 v1(10184.7,5548.2) ; Q5$CBB9/CBB35.2@10117.3,6338.2 10122.3,6333.2 v1(10184.7,6333.2) ; Q5$CBB9/CBB34.2@10117.3,6858.2 10122.3,6853.2 v1(10184.7,6853.2) ; Q5$CBB9/CBB33.2@10117.3,7643.2 10122.3,7638.2 v1(10184.7,7638.2) ; Q5$CBB9/CBB42.2@10117.3,8163.2 10122.3,8158.2 v1(10184.7,8158.2) ; Q5$CBB9/CBB32.2@10117.3,8428.2 10122.3,8423.2 v1(10184.7,8423.2) ; Q5$CBB9/CBB31.2@10117.3,8948.2 10122.3,8943.2 v1(10184.7,8943.2) ; v1(10136.9,5160.6) U5$CBB9.10@10213.4,5160.6
  Inner4 w7.9: v1(10136.9,5160.6) 10182.1,5205.8 v1@10182.1,5552.7 ; v1(10182.1,9398.7) v1@10182.1,8947.7 ; v1(10184.7,5548.2) 10184.7,5550.1 v1@10182.1,5552.7 ; v1(10184.7,6333.2) 10184.7,6335.1 v1@10182.1,6337.7 ; v1(10184.7,6853.2) 10184.7,6855.1 v1@10182.1,6857.7 ; v1(10184.7,7638.2) 10184.7,7640.1 v1@10182.1,7642.7 ; v1(10184.7,8158.2) 10184.7,8160.1 v1@10182.1,8162.7 ; v1(10184.7,8423.2) 10184.7,8425.1 v1@10182.1,8427.7 ; v1(10184.7,8943.2) 10184.7,8945.1 v1@10182.1,8947.7 ; v1@10182.1,5552.7 v1@10182.1,6337.7 ; v1@10182.1,6337.7 v1@10182.1,6857.7 ; v1@10182.1,6857.7 v1@10182.1,7642.7 ; v1@10182.1,7642.7 v1@10182.1,8162.7 ; v1@10182.1,8162.7 v1@10182.1,8427.7 ; v1@10182.1,8427.7 v1@10182.1,8947.7
$1I25\M8_COL-1: Q8$CBB9/CBB1.2 Q8$CBB9/CBB2.2 Q8$CBB9/CBB3.2 Q8$CBB9/CBB4.2 Q8$CBB9/CBB5.2 Q8$CBB9/CBB6.2 Q8$CBB9/CBB37.2 U3$CBB9.5 | length 5250.6
  Top Layer w7.9: Q8$CBB9/CBB6.2@7573.8,5638.2 7656.8,5638.2 v1(7666.2,5628.7) ; Q8$CBB9/CBB5.2@7573.8,6423.2 7656.8,6423.2 v1(7666.2,6413.7) ; Q8$CBB9/CBB4.2@7573.8,6943.2 7656.8,6943.2 v1(7666.2,6933.7) ; Q8$CBB9/CBB3.2@7573.8,7728.2 7656.8,7728.2 v1(7666.2,7718.7) ; Q8$CBB9/CBB37.2@7573.8,8248.2 7656.8,8248.2 v1(7666.2,8238.7) ; Q8$CBB9/CBB2.2@7573.8,8513.2 7656.8,8513.2 v1(7666.2,8503.7) ; Q8$CBB9/CBB1.2@7573.8,9033.2 7656.8,9033.2 v1(7666.2,9023.7) ; v1(7662.3,5138.7) 7666,5135 7894.6,5135 7900.1,5140.6 7900.1,5150.2 7910.6,5160.6 U3$CBB9.5@7960.6,5160.6
  Inner4 w7.9: v1(7662.3,5138.7) v1(7662.3,9398.7)
$1I25\M8_COL-2: Q8$CBB9/CBB7.2 Q8$CBB9/CBB8.2 Q8$CBB9/CBB9.2 Q8$CBB9/CBB10.2 Q8$CBB9/CBB11.2 Q8$CBB9/CBB12.2 Q8$CBB9/CBB38.2 U3$CBB9.12 | length 4917.8
  Top Layer w7.9: Q8$CBB9/CBB12.2@8082.5,5638.2 8165.5,5638.2 v1(8174.9,5628.7) ; Q8$CBB9/CBB11.2@8082.5,6423.2 8165.5,6423.2 v1(8174.9,6413.7) ; Q8$CBB9/CBB10.2@8082.5,6943.2 8165.5,6943.2 v1(8174.9,6933.7) ; Q8$CBB9/CBB9.2@8082.5,7728.2 8165.5,7728.2 v1(8174.9,7718.7) ; Q8$CBB9/CBB38.2@8082.5,8248.2 8165.5,8248.2 v1(8174.9,8238.7) ; Q8$CBB9/CBB8.2@8082.5,8513.2 8165.5,8513.2 v1(8174.9,8503.7) ; Q8$CBB9/CBB7.2@8082.5,9033.2 8165.5,9033.2 v1(8174.9,9023.7) ; U3$CBB9.12@8178.6,5260.6 8219,5260.6 8231.8,5247.8 v1(8237.9,5247.8)
  Inner4 w7.9: v1(8171,9398.7) 8171,5314.7 v1(8237.9,5247.8)
$1I25\M8_COL-3: Q8$CBB9/CBB13.2 Q8$CBB9/CBB14.2 Q8$CBB9/CBB15.2 Q8$CBB9/CBB16.2 Q8$CBB9/CBB17.2 Q8$CBB9/CBB18.2 Q8$CBB9/CBB39.2 U4$CBB9.5 | length 5248.7
  Top Layer w7.9: Q8$CBB9/CBB18.2@8591.2,5638.1 8674.2,5638.1 v1(8683.6,5628.7) ; Q8$CBB9/CBB17.2@8591.2,6423.1 8674.2,6423.1 v1(8683.6,6413.7) ; Q8$CBB9/CBB16.2@8591.2,6943.1 8674.2,6943.1 v1(8683.6,6933.7) ; Q8$CBB9/CBB15.2@8591.2,7728.1 8674.2,7728.1 v1(8683.6,7718.7) ; Q8$CBB9/CBB39.2@8591.2,8248.1 8674.2,8248.1 v1(8683.6,8238.7) ; Q8$CBB9/CBB14.2@8591.2,8513.1 8674.2,8513.1 v1(8683.6,8503.7) ; Q8$CBB9/CBB13.2@8591.2,9033.1 8674.2,9033.1 v1(8683.6,9023.7) ; v1(8677.5,5140.6) 8684.4,5133.7 8901.1,5133.7 8927.9,5160.6 U4$CBB9.5@8978,5160.6
  Inner4 w7.9: v1@8679.7,5138.7 8679.7,5251.1 8679.9,5251.4 8679.9,5266.1 8679.7,5266.3 v1(8679.7,9398.7)
$1I25\M8_COL-4: Q8$CBB9/CBB19.2 Q8$CBB9/CBB20.2 Q8$CBB9/CBB21.2 Q8$CBB9/CBB22.2 Q8$CBB9/CBB23.2 Q8$CBB9/CBB24.2 Q8$CBB9/CBB40.2 U4$CBB9.12 | length 4931.1
  Top Layer w7.9: Q8$CBB9/CBB24.2@9099.9,5638.2 9182.9,5638.2 v1(9192.3,5628.7) ; Q8$CBB9/CBB23.2@9099.9,6423.2 9182.9,6423.2 v1(9192.3,6413.7) ; Q8$CBB9/CBB22.2@9099.9,6943.2 9182.9,6943.2 v1(9192.3,6933.7) ; Q8$CBB9/CBB21.2@9099.9,7728.2 9182.9,7728.2 v1(9192.3,7718.7) ; Q8$CBB9/CBB40.2@9099.9,8248.2 9182.9,8248.2 v1(9192.3,8238.7) ; Q8$CBB9/CBB20.2@9099.9,8513.2 9182.9,8513.2 v1(9192.3,8503.7) ; Q8$CBB9/CBB19.2@9099.9,9033.2 9182.9,9033.2 v1(9192.3,9023.7) ; U4$CBB9.12@9196,5260.6 9236.4,5260.6 9251.4,5245.6 v1(9262.5,5245.6)
  Inner4 w7.9: v1(9188.4,9398.7) 9188.4,5319.7 v1(9262.5,5245.6)
$1I25\M8_COL-5: Q8$CBB9/CBB25.2 Q8$CBB9/CBB26.2 Q8$CBB9/CBB27.2 Q8$CBB9/CBB28.2 Q8$CBB9/CBB29.2 Q8$CBB9/CBB30.2 Q8$CBB9/CBB41.2 U5$CBB9.5 | length 5241.7
  Top Layer w7.9: Q8$CBB9/CBB30.2@9608.6,5638.2 9691.6,5638.2 v1(9701,5628.7) ; Q8$CBB9/CBB29.2@9608.6,6423.2 9691.6,6423.2 v1(9701,6413.7) ; Q8$CBB9/CBB28.2@9608.6,6943.2 9691.6,6943.2 v1(9701,6933.7) ; Q8$CBB9/CBB27.2@9608.6,7728.2 9691.6,7728.2 v1(9701,7718.7) ; Q8$CBB9/CBB41.2@9608.6,8248.2 9691.6,8248.2 v1(9701,8238.7) ; Q8$CBB9/CBB26.2@9608.6,8513.2 9691.6,8513.2 v1(9701,8503.7) ; Q8$CBB9/CBB25.2@9608.6,9033.2 9691.6,9033.2 v1(9701,9023.7) ; v1(9934.9,5140.6) 9934.9,5150.2 9945.3,5160.6 U5$CBB9.5@9995.4,5160.6
  Inner2 w7.9: v1(9707.1,5138.7) 9709,5140.6 v1(9934.9,5140.6)
  Inner4 w7.9: v1(9697.1,9398.7) 9697.1,5148.8 v1(9707.1,5138.7)
$1I25\M8_COL-6: Q8$CBB9/CBB31.2 Q8$CBB9/CBB32.2 Q8$CBB9/CBB33.2 Q8$CBB9/CBB34.2 Q8$CBB9/CBB35.2 Q8$CBB9/CBB36.2 Q8$CBB9/CBB42.2 U5$CBB9.12 | length 4931.1
  Top Layer w7.9: Q8$CBB9/CBB36.2@10117.3,5638.2 10200.3,5638.2 v1(10209.7,5628.7) ; Q8$CBB9/CBB35.2@10117.3,6423.2 10200.3,6423.2 v1(10209.7,6413.7) ; Q8$CBB9/CBB34.2@10117.3,6943.2 10200.3,6943.2 v1(10209.7,6933.7) ; Q8$CBB9/CBB33.2@10117.3,7728.2 10200.3,7728.2 v1(10209.7,7718.7) ; Q8$CBB9/CBB42.2@10117.3,8248.2 10200.3,8248.2 v1(10209.7,8238.7) ; Q8$CBB9/CBB32.2@10117.3,8513.2 10200.3,8513.2 v1(10209.7,8503.7) ; Q8$CBB9/CBB31.2@10117.3,9033.2 10200.3,9033.2 v1(10209.7,9023.7) ; U5$CBB9.12@10213.4,5260.6 10253.8,5260.6 10268.8,5245.6 v1(10279.9,5245.6)
  Inner4 w7.9: v1(10205.8,9398.7) 10205.8,5319.7 v1(10279.9,5245.6)
$1I26\$1N1: Q3$CBB10.1 Q3$CBB10.3 Q4$CBB10.2 | length 210.9
  Bottom Layer w7.9: Q3$CBB10.1@8054.8,4449.8 8080.4,4475.4 Q3$CBB10.3@8126.5,4475.4 8126.5,4461.8 8138.5,4449.8 Q4$CBB10.2@8236.5,4449.8
$1I26\$1N2: Q1$CBB10.2 Q4$CBB10.1 Q4$CBB10.3 R10$CBB10.2 | length 249.9
  Bottom Layer w7.9: Q4$CBB10.3@8164.8,4475.4 8188.4,4475.4 8214,4501 Q4$CBB10.1@8236.5,4501 Q1$CBB10.2@8236.5,4539.8 8254.3,4539.8 8267.1,4552.6 8267.1,4610.9 R10$CBB10.2@8242.7,4635.4
$1I26\$1N3: Q2$CBB10.1 Q2$CBB10.3 Q3$CBB10.2 R2$CBB10.1 R9$CBB10.1 U1$CBB10.6 | length 439.8
  Bottom Layer w7.9: Q3$CBB10.2@8054.8,4501 Q2$CBB10.1@8054.8,4539.8 8100.9,4539.8 Q2$CBB10.3@8126.5,4565.4 8126.5,4593.5 8130.6,4597.6 8130.6,4632.4 R2$CBB10.1@8133.6,4635.4 ; R9$CBB10.1@8092.7,4635.4 R2$CBB10.1@8133.6,4635.4 ; U1$CBB10.6@8264.6,4742.6 8190.6,4742.6 8133.6,4685.6 R2$CBB10.1@8133.6,4635.4
$1I26\$1N4: Q1$CBB10.1 Q1$CBB10.3 Q2$CBB10.2 | length 362.2
  Bottom Layer w7.9: Q2$CBB10.2@8054.8,4591 8035.6,4571.8 8035.6,4552.9 8034.1,4551.4 8034.1,4489.4 8039.3,4484.2 8049.1,4484.2 8050.6,4482.6 8068.8,4482.6 8075.6,4489.4 8075.6,4492.6 8125.6,4542.6 8142.1,4542.6 Q1$CBB10.3@8164.8,4565.4 8190.4,4591 Q1$CBB10.1@8236.5,4591
$1I26\$1N9: R8$CBB10.2 U1$CBB10.1 U1$CBB10.2 U1$CBB10.5 U1$CBB10.12 | length 633.7
  Bottom Layer w7.9: R8$CBB10.2@7975.6,4829.7 7975.6,4872.6 7995.6,4892.6 U1$CBB10.12@8046.6,4892.6 8110.8,4892.6 ; U1$CBB10.2@8264.6,4942.6 U1$CBB10.1@8264.6,4992.6 ; U1$CBB10.5@8264.7,4792.6 8185.4,4792.6 8140.8,4837.2 8120.8,4837.2 8109.9,4848.1 8109.9,4891.7 8110.8,4892.6 ; U1$CBB10.2@8264.7,4942.6 8221.3,4942.6 8171.3,4892.6 8110.8,4892.6
$1I26\$1N10: R2$CBB10.2 R10$CBB10.1 R15$CBB10.1 U1$CBB10.7 | length 288.3
  Bottom Layer w7.9: R2$CBB10.2@8167.7,4635.4 R10$CBB10.1@8208.6,4635.4 8208.6,4675.6 8225.6,4692.6 8264.6,4692.6 8312.7,4692.6 R15$CBB10.1@8380.6,4760.6
$1I26\$1N13: R4$CBB10.1 R5$CBB10.2 U1$CBB10.3 | length 207.5
  Bottom Layer w7.9: U1$CBB10.3@8264.6,4892.6 8285.6,4892.6 8315.6,4922.6 8315.6,4932.6 8325.6,4942.6 8370.6,4942.6 8376.2,4937.1 8376.2,4921.2 R5$CBB10.2@8372.7,4917.6 8372.7,4900.6 8380.6,4892.6 R4$CBB10.1@8380.6,4874.7
$1I26\$1N15: R3$CBB10.1 R6$CBB10.1 U1$CBB10.9 | length 114.3
  Bottom Layer w7.9: R6$CBB10.1@7935.6,4734.7 R3$CBB10.1@7975.6,4734.7 7997.7,4734.7 8005.6,4742.6 U1$CBB10.9@8046.6,4742.6
$1I26\$1N16: R7$CBB10.1 R8$CBB10.1 U1$CBB10.10 | length 197.4
  Bottom Layer w7.9: R7$CBB10.1@7895.8,4719.2 7895.8,4742.6 7910.8,4757.6 7925.6,4757.6 7963.6,4795.6 R8$CBB10.1@7975.6,4795.6 7978.6,4792.6 U1$CBB10.10@8046.6,4792.6
$1I26\$1N22: R13$CBB10.1 R15$CBB10.2 U1$CBB10.13 | length 674.1
  Bottom Layer w7.9: R13$CBB10.1@7975.6,4950.6 7992.7,4950.6 8000.6,4942.6 U1$CBB10.13@8046.6,4942.6 8115.6,4942.6 8211.7,5038.7 8314.5,5038.7 8405.6,4947.6 8405.6,4819.7 R15$CBB10.2@8380.6,4794.7
$1I26\SIGM: H1$CBB10.1 R13$CBB10.2 U1$CBB10.14 | length 829
  Inner4 w7.9: H1$CBB10.1@7960.8,4392.2 8054.6,4486 8054.6,4885.4 8105.8,4936.5 v1(8105.8,4967.2)
  Bottom Layer w7.9: U1$CBB10.14@8046.6,4992.6 8005.6,4992.6 8005.1,4992.2 ; v1(8105.8,4967.2) 8080.8,4992.2 8005.1,4992.2 ; R13$CBB10.2@7978.6,4987.6 R13$CBB10.2@7975.6,4984.7 R13$CBB10.2@7978.6,4987.6 ; R13$CBB10.2@7978.6,4987.6 7984.1,4982.2 7995.1,4982.2 8005.1,4992.2
$1I26\SIGM_BYPAS: H1$CBB10.3 R3$CBB10.2 R9$CBB10.2 U1$CBB10.8 | length 253.8
  Bottom Layer w7.9: H1$CBB10.3@7960.8,4592.2 8004.1,4635.4 R9$CBB10.2@8058.6,4635.4 8058.6,4680.7 U1$CBB10.8@8046.6,4692.6 8005.6,4692.6 7995.6,4702.6 7977.7,4702.6 R3$CBB10.2@7975.6,4700.6
$1I27\$1N1: Q3$CBB11.1 Q3$CBB11.3 Q4$CBB11.2 | length 210.9
  Bottom Layer w7.9: Q3$CBB11.1@8563.5,4449.8 8589.1,4475.4 Q3$CBB11.3@8635.2,4475.4 8635.2,4461.8 8647.2,4449.8 Q4$CBB11.2@8745.2,4449.8
$1I27\$1N2: Q1$CBB11.2 Q4$CBB11.1 Q4$CBB11.3 R10$CBB11.2 | length 249.9
  Bottom Layer w7.9: Q4$CBB11.3@8673.5,4475.4 8697.1,4475.4 8722.7,4501 Q4$CBB11.1@8745.2,4501 Q1$CBB11.2@8745.2,4539.8 8763,4539.8 8775.8,4552.6 8775.8,4610.9 R10$CBB11.2@8751.4,4635.4
$1I27\$1N3: Q2$CBB11.1 Q2$CBB11.3 Q3$CBB11.2 R2$CBB11.1 R9$CBB11.1 U1$CBB11.6 | length 439.8
  Bottom Layer w7.9: Q3$CBB11.2@8563.5,4501 Q2$CBB11.1@8563.5,4539.8 8609.6,4539.8 Q2$CBB11.3@8635.2,4565.4 8635.2,4593.5 8639.3,4597.6 8639.3,4632.4 R2$CBB11.1@8642.3,4635.4 ; R9$CBB11.1@8601.4,4635.4 R2$CBB11.1@8642.3,4635.4 ; U1$CBB11.6@8773.3,4742.6 8699.3,4742.6 8642.3,4685.6 R2$CBB11.1@8642.3,4635.4
$1I27\$1N4: Q1$CBB11.1 Q1$CBB11.3 Q2$CBB11.2 | length 362.2
  Bottom Layer w7.9: Q2$CBB11.2@8563.5,4591 8544.3,4571.8 8544.3,4552.9 8542.8,4551.4 8542.8,4489.4 8548,4484.2 8557.8,4484.2 8559.3,4482.6 8577.5,4482.6 8584.3,4489.4 8584.3,4492.6 8634.3,4542.6 8650.8,4542.6 Q1$CBB11.3@8673.5,4565.4 8699.1,4591 Q1$CBB11.1@8745.2,4591
$1I27\$1N9: R8$CBB11.2 U1$CBB11.1 U1$CBB11.2 U1$CBB11.5 U1$CBB11.12 | length 633.7
  Bottom Layer w7.9: R8$CBB11.2@8484.3,4829.7 8484.3,4872.6 8504.3,4892.6 U1$CBB11.12@8555.3,4892.6 8619.5,4892.6 ; U1$CBB11.2@8773.3,4942.6 U1$CBB11.1@8773.3,4992.6 ; U1$CBB11.5@8773.4,4792.6 8694.1,4792.6 8649.5,4837.2 8629.5,4837.2 8618.6,4848.1 8618.6,4891.7 8619.5,4892.6 ; U1$CBB11.2@8773.4,4942.6 8730,4942.6 8680,4892.6 8619.5,4892.6
$1I27\$1N10: R2$CBB11.2 R10$CBB11.1 R15$CBB11.1 U1$CBB11.7 | length 288.3
  Bottom Layer w7.9: R2$CBB11.2@8676.4,4635.4 R10$CBB11.1@8717.3,4635.4 8717.3,4675.6 8734.3,4692.6 8773.3,4692.6 8821.4,4692.6 R15$CBB11.1@8889.3,4760.6
$1I27\$1N13: R4$CBB11.1 R5$CBB11.2 U1$CBB11.3 | length 207.5
  Bottom Layer w7.9: U1$CBB11.3@8773.3,4892.6 8794.3,4892.6 8824.3,4922.6 8824.3,4932.6 8834.3,4942.6 8879.3,4942.6 8884.9,4937.1 8884.9,4921.2 R5$CBB11.2@8881.4,4917.6 8881.4,4900.6 8889.3,4892.6 R4$CBB11.1@8889.3,4874.7
$1I27\$1N15: R3$CBB11.1 R6$CBB11.1 U1$CBB11.9 | length 114.3
  Bottom Layer w7.9: R6$CBB11.1@8444.3,4734.7 R3$CBB11.1@8484.3,4734.7 8506.4,4734.7 8514.3,4742.6 U1$CBB11.9@8555.3,4742.6
$1I27\$1N16: R7$CBB11.1 R8$CBB11.1 U1$CBB11.10 | length 197.4
  Bottom Layer w7.9: R7$CBB11.1@8404.5,4719.2 8404.5,4742.6 8419.5,4757.6 8434.3,4757.6 8472.3,4795.6 R8$CBB11.1@8484.3,4795.6 8487.3,4792.6 U1$CBB11.10@8555.3,4792.6
$1I27\$1N22: R13$CBB11.1 R15$CBB11.2 U1$CBB11.13 | length 678.3
  Bottom Layer w7.9: R13$CBB11.1@8484.3,4950.6 8501.4,4950.6 8509.3,4942.6 U1$CBB11.13@8555.3,4942.6 8624.3,4942.6 8725.4,5043.7 8818.2,5043.7 8914.3,4947.6 8914.3,4819.7 R15$CBB11.2@8889.3,4794.7
$1I27\SIGM: H1$CBB11.1 R13$CBB11.2 U1$CBB11.14 | length 829
  Inner4 w7.9: H1$CBB11.1@8469.5,4392.2 8524.5,4447.2 8524.5,4877.2 v1(8614.5,4967.2)
  Bottom Layer w7.9: U1$CBB11.14@8555.3,4992.6 8514.3,4992.6 8513.8,4992.2 ; v1(8614.5,4967.2) 8589.5,4992.2 8513.8,4992.2 ; R13$CBB11.2@8487.3,4987.6 R13$CBB11.2@8484.3,4984.7 R13$CBB11.2@8487.3,4987.6 ; R13$CBB11.2@8487.3,4987.6 8492.8,4982.2 8503.8,4982.2 8513.8,4992.2
$1I27\SIGM_BYPAS: H1$CBB11.3 R3$CBB11.2 R9$CBB11.2 U1$CBB11.8 | length 253.8
  Bottom Layer w7.9: H1$CBB11.3@8469.5,4592.2 8512.8,4635.4 R9$CBB11.2@8567.3,4635.4 8567.3,4680.7 U1$CBB11.8@8555.3,4692.6 8514.3,4692.6 8504.3,4702.6 8486.4,4702.6 R3$CBB11.2@8484.3,4700.6
$1I28\$1N1: Q3$CBB12.1 Q3$CBB12.3 Q4$CBB12.2 | length 210.9
  Bottom Layer w7.9: Q3$CBB12.1@9072.2,4449.8 9097.8,4475.4 Q3$CBB12.3@9143.9,4475.4 9143.9,4461.8 9155.9,4449.8 Q4$CBB12.2@9253.9,4449.8
$1I28\$1N2: Q1$CBB12.2 Q4$CBB12.1 Q4$CBB12.3 R10$CBB12.2 | length 249.9
  Bottom Layer w7.9: Q4$CBB12.3@9182.2,4475.4 9205.8,4475.4 9231.4,4501 Q4$CBB12.1@9253.9,4501 Q1$CBB12.2@9253.9,4539.8 9271.7,4539.8 9284.5,4552.6 9284.5,4610.9 R10$CBB12.2@9260.1,4635.4
$1I28\$1N3: Q2$CBB12.1 Q2$CBB12.3 Q3$CBB12.2 R2$CBB12.1 R9$CBB12.1 U1$CBB12.6 | length 439.8
  Bottom Layer w7.9: Q3$CBB12.2@9072.2,4501 Q2$CBB12.1@9072.2,4539.8 9118.3,4539.8 Q2$CBB12.3@9143.9,4565.4 9143.9,4593.5 9148,4597.6 9148,4632.4 R2$CBB12.1@9151,4635.4 ; R9$CBB12.1@9110.1,4635.4 R2$CBB12.1@9151,4635.4 ; U1$CBB12.6@9282,4742.6 9208,4742.6 9151,4685.6 R2$CBB12.1@9151,4635.4
$1I28\$1N4: Q1$CBB12.1 Q1$CBB12.3 Q2$CBB12.2 | length 362.2
  Bottom Layer w7.9: Q2$CBB12.2@9072.2,4591 9053,4571.8 9053,4552.9 9051.5,4551.4 9051.5,4489.4 9056.7,4484.2 9066.5,4484.2 9068,4482.6 9086.2,4482.6 9093,4489.4 9093,4492.6 9143,4542.6 9159.5,4542.6 Q1$CBB12.3@9182.2,4565.4 9207.8,4591 Q1$CBB12.1@9253.9,4591
$1I28\$1N9: R8$CBB12.2 U1$CBB12.1 U1$CBB12.2 U1$CBB12.5 U1$CBB12.12 | length 633.7
  Bottom Layer w7.9: R8$CBB12.2@8993,4829.7 8993,4872.6 9013,4892.6 U1$CBB12.12@9064,4892.6 9128.2,4892.6 ; U1$CBB12.2@9282,4942.6 U1$CBB12.1@9282,4992.6 ; U1$CBB12.5@9282.1,4792.6 9202.8,4792.6 9158.2,4837.2 9138.2,4837.2 9127.3,4848.1 9127.3,4891.7 9128.2,4892.6 ; U1$CBB12.2@9282.1,4942.6 9238.7,4942.6 9188.7,4892.6 9128.2,4892.6
$1I28\$1N10: R2$CBB12.2 R10$CBB12.1 R15$CBB12.1 U1$CBB12.7 | length 288.3
  Bottom Layer w7.9: R2$CBB12.2@9185.1,4635.4 R10$CBB12.1@9226,4635.4 9226,4675.6 9243,4692.6 9282,4692.6 9330.1,4692.6 R15$CBB12.1@9398,4760.6
$1I28\$1N13: R4$CBB12.1 R5$CBB12.2 U1$CBB12.3 | length 207.5
  Bottom Layer w7.9: U1$CBB12.3@9282,4892.6 9303,4892.6 9333,4922.6 9333,4932.6 9343,4942.6 9388,4942.6 9393.6,4937.1 9393.6,4921.2 R5$CBB12.2@9390.1,4917.6 9390.1,4900.6 9398,4892.6 R4$CBB12.1@9398,4874.7
$1I28\$1N15: R3$CBB12.1 R6$CBB12.1 U1$CBB12.9 | length 114.3
  Bottom Layer w7.9: R6$CBB12.1@8953,4734.7 R3$CBB12.1@8993,4734.7 9015.1,4734.7 9023,4742.6 U1$CBB12.9@9064,4742.6
$1I28\$1N16: R7$CBB12.1 R8$CBB12.1 U1$CBB12.10 | length 197.4
  Bottom Layer w7.9: R7$CBB12.1@8913.2,4719.2 8913.2,4742.6 8928.2,4757.6 8943,4757.6 8981,4795.6 R8$CBB12.1@8993,4795.6 8996,4792.6 U1$CBB12.10@9064,4792.6
$1I28\$1N22: R13$CBB12.1 R15$CBB12.2 U1$CBB12.13 | length 682.4
  Bottom Layer w7.9: R13$CBB12.1@8993,4950.6 9010.1,4950.6 9018,4942.6 U1$CBB12.13@9064,4942.6 9133,4942.6 9230.7,5040.4 9233.3,5040.4 9240.7,5047.7 9248.3,5047.7 9249.3,5048.7 9321.9,5048.7 9423,4947.6 9423,4819.7 R15$CBB12.2@9398,4794.7
$1I28\SIGM: H1$CBB12.1 R13$CBB12.2 U1$CBB12.14 | length 889
  Inner4 w7.9: H1$CBB12.1@8978.2,4392.2 8978.2,4391.5 8980,4389.7 9074,4389.7 9098.7,4414.4 9098.7,4942.7 v1(9123.2,4967.2)
  Bottom Layer w7.9: U1$CBB12.14@9064,4992.6 9023,4992.6 9022.5,4992.2 ; v1(9123.2,4967.2) 9098.2,4992.2 9022.5,4992.2 ; R13$CBB12.2@8996,4987.6 R13$CBB12.2@8993,4984.7 R13$CBB12.2@8996,4987.6 ; R13$CBB12.2@8996,4987.6 9001.5,4982.2 9012.5,4982.2 9022.5,4992.2
$1I28\SIGM_BYPAS: H1$CBB12.3 R3$CBB12.2 R9$CBB12.2 U1$CBB12.8 | length 253.8
  Bottom Layer w7.9: H1$CBB12.3@8978.2,4592.2 9021.5,4635.4 R9$CBB12.2@9076,4635.4 9076,4680.7 U1$CBB12.8@9064,4692.6 9023,4692.6 9013,4702.6 8995.1,4702.6 R3$CBB12.2@8993,4700.6
$1I29\$1N1: Q3$CBB13.1 Q3$CBB13.3 Q4$CBB13.2 | length 210.9
  Bottom Layer w7.9: Q3$CBB13.1@9580.9,4449.8 9606.5,4475.4 Q3$CBB13.3@9652.6,4475.4 9652.6,4461.8 9664.6,4449.8 Q4$CBB13.2@9762.6,4449.8
$1I29\$1N2: Q1$CBB13.2 Q4$CBB13.1 Q4$CBB13.3 R10$CBB13.2 | length 250
  Bottom Layer w7.9: Q4$CBB13.3@9690.9,4475.4 9714.5,4475.4 9740.1,4501 Q4$CBB13.1@9762.6,4501 Q1$CBB13.2@9762.6,4539.8 9780.4,4539.8 9793.3,4552.6 9793.3,4610.9 R10$CBB13.2@9768.8,4635.4
$1I29\$1N3: Q2$CBB13.1 Q2$CBB13.3 Q3$CBB13.2 R2$CBB13.1 R9$CBB13.1 U1$CBB13.6 | length 439.9
  Bottom Layer w7.9: Q3$CBB13.2@9580.9,4501 Q2$CBB13.1@9580.9,4539.8 9627,4539.8 Q2$CBB13.3@9652.6,4565.4 9652.6,4593.5 9656.7,4597.6 9656.7,4632.4 R2$CBB13.1@9659.7,4635.4 ; R9$CBB13.1@9618.8,4635.4 R2$CBB13.1@9659.7,4635.4 ; U1$CBB13.6@9790.8,4742.6 9716.7,4742.6 9659.7,4685.6 R2$CBB13.1@9659.7,4635.4
$1I29\$1N4: Q1$CBB13.1 Q1$CBB13.3 Q2$CBB13.2 | length 362.2
  Bottom Layer w7.9: Q2$CBB13.2@9580.9,4591 9561.7,4571.8 9561.7,4552.9 9560.2,4551.4 9560.2,4489.4 9565.4,4484.2 9575.2,4484.2 9576.7,4482.6 9594.9,4482.6 9601.7,4489.4 9601.7,4492.6 9651.7,4542.6 9668.2,4542.6 Q1$CBB13.3@9690.9,4565.4 9716.5,4591 Q1$CBB13.1@9762.6,4591
$1I29\$1N9: R8$CBB13.2 U1$CBB13.1 U1$CBB13.2 U1$CBB13.5 U1$CBB13.12 | length 633.7
  Bottom Layer w7.9: R8$CBB13.2@9501.7,4829.7 9501.7,4872.6 9521.7,4892.6 U1$CBB13.12@9572.7,4892.6 9636.9,4892.6 ; U1$CBB13.5@9790.8,4792.6 9711.5,4792.6 9666.9,4837.2 9646.9,4837.2 9636,4848.1 9636,4891.7 9636.9,4892.6 ; U1$CBB13.1@9790.8,4992.6 U1$CBB13.2@9790.8,4942.6 9747.4,4942.6 9697.4,4892.6 9636.9,4892.6
$1I29\$1N10: R2$CBB13.2 R10$CBB13.1 R15$CBB13.1 U1$CBB13.7 | length 288.3
  Bottom Layer w7.9: R2$CBB13.2@9693.8,4635.4 R10$CBB13.1@9734.7,4635.4 9734.7,4675.6 9751.7,4692.6 U1$CBB13.7@9790.8,4692.6 9838.8,4692.6 R15$CBB13.1@9906.7,4760.6
$1I29\$1N13: R4$CBB13.1 R5$CBB13.2 U1$CBB13.3 | length 207.4
  Bottom Layer w7.9: U1$CBB13.3@9790.8,4892.6 9811.7,4892.6 9841.7,4922.6 9841.7,4932.6 9851.7,4942.6 9896.7,4942.6 9902.3,4937.1 9902.3,4921.2 R5$CBB13.2@9898.8,4917.6 9898.8,4900.6 9906.7,4892.6 R4$CBB13.1@9906.7,4874.7
$1I29\$1N15: R3$CBB13.1 R6$CBB13.1 U1$CBB13.9 | length 114.3
  Bottom Layer w7.9: R6$CBB13.1@9461.7,4734.7 R3$CBB13.1@9501.7,4734.7 9523.8,4734.7 9531.7,4742.6 U1$CBB13.9@9572.7,4742.6
$1I29\$1N16: R7$CBB13.1 R8$CBB13.1 U1$CBB13.10 | length 197.4
  Bottom Layer w7.9: R7$CBB13.1@9421.9,4719.2 9421.9,4742.6 9436.9,4757.6 9451.7,4757.6 9489.7,4795.6 R8$CBB13.1@9501.7,4795.6 9504.7,4792.6 U1$CBB13.10@9572.7,4792.6
$1I29\$1N22: R13$CBB13.1 R15$CBB13.2 U1$CBB13.13 | length 664.9
  Bottom Layer w7.9: R13$CBB13.1@9501.7,4950.6 9518.8,4950.6 9526.7,4942.6 U1$CBB13.13@9572.7,4942.6 9632.6,4942.6 9717.6,5027.6 9851.7,5027.6 9931.7,4947.6 9931.7,4819.7 R15$CBB13.2@9906.7,4794.7
$1I29\SIGM: H1$CBB13.1 R13$CBB13.2 U1$CBB13.14 | length 828.9
  Inner4 w7.9: H1$CBB13.1@9486.9,4392.2 9541.9,4447.2 9541.9,4877.2 v1(9631.9,4967.2)
  Bottom Layer w7.9: U1$CBB13.14@9572.7,4992.6 9531.7,4992.6 9531.3,4992.2 ; v1(9631.9,4967.2) 9606.9,4992.2 9531.3,4992.2 ; R13$CBB13.2@9504.7,4987.6 R13$CBB13.2@9501.7,4984.7 R13$CBB13.2@9504.7,4987.6 ; R13$CBB13.2@9504.7,4987.6 9510.2,4982.2 9521.3,4982.2 9531.3,4992.2
$1I29\SIGM_BYPAS: H1$CBB13.3 R3$CBB13.2 R9$CBB13.2 U1$CBB13.8 | length 253.8
  Bottom Layer w7.9: H1$CBB13.3@9486.9,4592.2 9530.2,4635.4 R9$CBB13.2@9584.7,4635.4 9584.7,4680.7 U1$CBB13.8@9572.7,4692.6 9531.7,4692.6 9521.7,4702.6 9503.8,4702.6 R3$CBB13.2@9501.7,4700.6
$1I30\$1N1: Q3$CBB14.1 Q3$CBB14.3 Q4$CBB14.2 | length 210.9
  Bottom Layer w7.9: Q3$CBB14.1@10089.6,4449.8 10115.2,4475.4 Q3$CBB14.3@10161.3,4475.4 10161.3,4461.8 10173.3,4449.8 Q4$CBB14.2@10271.3,4449.8
$1I30\$1N2: Q1$CBB14.2 Q4$CBB14.1 Q4$CBB14.3 R10$CBB14.2 | length 250
  Bottom Layer w7.9: Q4$CBB14.3@10199.6,4475.4 10223.2,4475.4 10248.8,4501 Q4$CBB14.1@10271.3,4501 Q1$CBB14.2@10271.3,4539.8 10289.1,4539.8 10302,4552.6 10302,4610.9 R10$CBB14.2@10277.5,4635.4
$1I30\$1N3: Q2$CBB14.1 Q2$CBB14.3 Q3$CBB14.2 R2$CBB14.1 R9$CBB14.1 U1$CBB14.6 | length 439.9
  Bottom Layer w7.9: Q3$CBB14.2@10089.6,4501 Q2$CBB14.1@10089.6,4539.8 10135.7,4539.8 Q2$CBB14.3@10161.3,4565.4 10161.3,4593.5 10165.4,4597.6 10165.4,4632.4 R2$CBB14.1@10168.4,4635.4 ; R9$CBB14.1@10127.5,4635.4 R2$CBB14.1@10168.4,4635.4 ; U1$CBB14.6@10299.5,4742.6 10225.4,4742.6 10168.4,4685.6 R2$CBB14.1@10168.4,4635.4
$1I30\$1N4: Q1$CBB14.1 Q1$CBB14.3 Q2$CBB14.2 | length 362.2
  Bottom Layer w7.9: Q2$CBB14.2@10089.6,4591 10070.4,4571.8 10070.4,4552.9 10068.9,4551.4 10068.9,4489.4 10074.1,4484.2 10083.9,4484.2 10085.4,4482.6 10103.6,4482.6 10110.4,4489.4 10110.4,4492.6 10160.4,4542.6 10176.9,4542.6 Q1$CBB14.3@10199.6,4565.4 10225.2,4591 Q1$CBB14.1@10271.3,4591
$1I30\$1N9: R8$CBB14.2 U1$CBB14.1 U1$CBB14.2 U1$CBB14.5 U1$CBB14.12 | length 633.7
  Bottom Layer w7.9: R8$CBB14.2@10010.4,4829.7 10010.4,4872.6 10030.4,4892.6 U1$CBB14.12@10081.4,4892.6 10145.6,4892.6 ; U1$CBB14.5@10299.5,4792.6 10220.2,4792.6 10175.6,4837.2 10155.6,4837.2 10144.7,4848.1 10144.7,4891.7 10145.6,4892.6 ; U1$CBB14.1@10299.5,4992.6 U1$CBB14.2@10299.5,4942.6 10256.1,4942.6 10206.1,4892.6 10145.6,4892.6
$1I30\$1N10: R2$CBB14.2 R10$CBB14.1 R15$CBB14.1 U1$CBB14.7 | length 288.3
  Bottom Layer w7.9: R2$CBB14.2@10202.5,4635.4 R10$CBB14.1@10243.4,4635.4 10243.4,4675.6 10260.4,4692.6 U1$CBB14.7@10299.5,4692.6 10347.5,4692.6 R15$CBB14.1@10415.4,4760.6
$1I30\$1N13: R4$CBB14.1 R5$CBB14.2 U1$CBB14.3 | length 207.4
  Bottom Layer w7.9: U1$CBB14.3@10299.5,4892.6 10320.4,4892.6 10350.4,4922.6 10350.4,4932.6 10360.4,4942.6 10405.4,4942.6 10411,4937.1 10411,4921.2 R5$CBB14.2@10407.5,4917.6 10407.5,4900.6 10415.4,4892.6 R4$CBB14.1@10415.4,4874.7
$1I30\$1N15: R3$CBB14.1 R6$CBB14.1 U1$CBB14.9 | length 114.3
  Bottom Layer w7.9: R6$CBB14.1@9970.4,4734.7 R3$CBB14.1@10010.4,4734.7 10032.5,4734.7 10040.4,4742.6 U1$CBB14.9@10081.4,4742.6
$1I30\$1N16: R7$CBB14.1 R8$CBB14.1 U1$CBB14.10 | length 197.4
  Bottom Layer w7.9: R7$CBB14.1@9930.6,4719.2 9930.6,4742.6 9945.6,4757.6 9960.4,4757.6 9998.4,4795.6 R8$CBB14.1@10010.4,4795.6 10013.4,4792.6 U1$CBB14.10@10081.4,4792.6
$1I30\$1N22: R13$CBB14.1 R15$CBB14.2 U1$CBB14.13 | length 684.6
  Bottom Layer w7.9: R13$CBB14.1@10010.4,4950.6 10027.5,4950.6 10035.4,4942.6 U1$CBB14.13@10081.4,4942.6 10150.4,4942.6 10236.5,5028.7 10267.1,5028.7 10289.7,5051.3 10336.8,5051.3 10440.4,4947.6 10440.4,4819.7 R15$CBB14.2@10415.4,4794.7
$1I30\SIGM: H1$CBB14.1 R13$CBB14.2 U1$CBB14.14 | length 828.9
  Inner4 w7.9: H1$CBB14.1@9995.6,4392.2 10050.6,4447.2 10050.6,4845.2 10140.6,4935.2 v1(10140.6,4967.2)
  Bottom Layer w7.9: U1$CBB14.14@10081.4,4992.6 10040.4,4992.6 10040,4992.2 ; v1(10140.6,4967.2) 10115.6,4992.2 10040,4992.2 ; R13$CBB14.2@10013.4,4987.6 R13$CBB14.2@10010.4,4984.7 R13$CBB14.2@10013.4,4987.6 ; R13$CBB14.2@10013.4,4987.6 10018.9,4982.2 10030,4982.2 10040,4992.2
$1I30\SIGM_BYPAS: H1$CBB14.3 R3$CBB14.2 R9$CBB14.2 U1$CBB14.8 | length 253.8
  Bottom Layer w7.9: H1$CBB14.3@9995.6,4592.2 10038.9,4635.4 R9$CBB14.2@10093.4,4635.4 10093.4,4680.7 U1$CBB14.8@10081.4,4692.6 10040.4,4692.6 10030.4,4702.6 10012.5,4702.6 R3$CBB14.2@10010.4,4700.6
$1I33\$1I15\$1N1: R9$CBB16/CBB1.1 U6$CBB16/CBB1.15 | length 333.5
  Top Layer w7.9: R9$CBB16/CBB1.1@4800.8,8740.1 4918,8740.1 5011.3,8646.8 U6$CBB16/CBB1.15@5095.7,8646.8
$1I33\$1I15\$1N2: R8$CBB16/CBB1.1 U6$CBB16/CBB1.1 | length 77.5
  Top Layer w7.9: R8$CBB16/CBB1.1@4800.8,8695.1 4875.9,8695.1 U6$CBB16/CBB1.1@4877.6,8696.8
$1I33\$1I15\$1N3: R7$CBB16/CBB1.1 U6$CBB16/CBB1.2 | length 77.5
  Top Layer w7.9: R7$CBB16/CBB1.1@4800.8,8645.1 4875.9,8645.1 U6$CBB16/CBB1.2@4877.6,8646.8
$1I33\$1I15\$1N4: R6$CBB16/CBB1.1 U6$CBB16/CBB1.3 | length 77.5
  Top Layer w7.9: R6$CBB16/CBB1.1@4800.8,8595.1 4875.9,8595.1 U6$CBB16/CBB1.3@4877.6,8596.8
$1I33\$1I15\$1N5: R5$CBB16/CBB1.1 U6$CBB16/CBB1.4 | length 77.5
  Top Layer w7.9: R5$CBB16/CBB1.1@4800.8,8545.1 4875.9,8545.1 U6$CBB16/CBB1.4@4877.6,8546.8
$1I33\$1I15\$1N6: R4$CBB16/CBB1.1 U6$CBB16/CBB1.5 | length 77.5
  Top Layer w7.9: R4$CBB16/CBB1.1@4800.8,8495.1 4875.9,8495.1 U6$CBB16/CBB1.5@4877.6,8496.8
$1I33\$1I15\$1N7: R3$CBB16/CBB1.1 U6$CBB16/CBB1.6 | length 77.5
  Top Layer w7.9: R3$CBB16/CBB1.1@4800.8,8445.1 4875.9,8445.1 U6$CBB16/CBB1.6@4877.6,8446.8
$1I33\$1I15\$1N8: R1$CBB16/CBB1.1 U6$CBB16/CBB1.7 | length 77.5
  Top Layer w7.9: R1$CBB16/CBB1.1@4800.8,8395.1 4875.9,8395.1 U6$CBB16/CBB1.7@4877.6,8396.8
$1I33\$1I15\$1N11: R2$CBB16/CBB1.1 R8$CBB16/CBB1.2 R10$CBB16/CBB1.2 | length 99.6
  Top Layer w7.9: R2$CBB16/CBB1.1@4673.8,8683 4717.9,8683 R10$CBB16/CBB1.2@4718.8,8682.1 4719.9,8681 4732.1,8681 4746.2,8695.1 R8$CBB16/CBB1.2@4766.7,8695.1
$1I33\$1I15\$1N12: R6$CBB16/CBB1.2 R11$CBB16/CBB1.1 R12$CBB16/CBB1.2 | length 102.8
  Top Layer w7.9: R11$CBB16/CBB1.1@4673.8,8603 4690.1,8603 4706,8587.1 R12$CBB16/CBB1.2@4718.8,8587.1 4738.3,8587.1 4746.2,8595.1 R6$CBB16/CBB1.2@4766.7,8595.1
$1I33\$1I15\$1N13: R7$CBB16/CBB1.2 R10$CBB16/CBB1.1 R11$CBB16/CBB1.2 | length 98.6
  Top Layer w7.9: R11$CBB16/CBB1.2@4673.8,8637.1 4683.3,8637.1 4694.2,8648 R10$CBB16/CBB1.1@4718.8,8648 4763.8,8648 R7$CBB16/CBB1.2@4766.7,8645.1
$1I33\$1I15\$1N14: R4$CBB16/CBB1.2 R13$CBB16/CBB1.1 R14$CBB16/CBB1.2 | length 102.8
  Top Layer w7.9: R13$CBB16/CBB1.1@4673.8,8503 4690.1,8503 4706,8487.1 R14$CBB16/CBB1.2@4718.8,8487.1 4733.3,8487.1 4741.2,8495.1 R4$CBB16/CBB1.2@4766.7,8495.1
$1I33\$1I15\$1N15: R5$CBB16/CBB1.2 R12$CBB16/CBB1.1 R13$CBB16/CBB1.2 | length 102.8
  Top Layer w7.9: R13$CBB16/CBB1.2@4673.8,8537.1 4688.3,8537.1 4704.2,8553 R12$CBB16/CBB1.1@4718.8,8553 4735.1,8553 4743,8545.1 R5$CBB16/CBB1.2@4766.7,8545.1
$1I33\$1I15\$1N16: R1$CBB16/CBB1.2 R15$CBB16/CBB1.1 R16$CBB16/CBB1.2 | length 143.2
  Top Layer w7.9: R15$CBB16/CBB1.1@4673.8,8408 4705.1,8408 4718,8395.1 R1$CBB16/CBB1.2@4766.7,8395.1 R16$CBB16/CBB1.2@4766.7,8350.1
$1I33\$1I15\$1N17: R3$CBB16/CBB1.2 R14$CBB16/CBB1.1 R15$CBB16/CBB1.2 | length 100.7
  Top Layer w7.9: R15$CBB16/CBB1.2@4673.8,8442.1 4688.3,8442.1 4699.2,8453 R14$CBB16/CBB1.1@4718.8,8453 4740.1,8453 4747.1,8446 4765.8,8446 R3$CBB16/CBB1.2@4766.7,8445.1
$1I33\$1I15\DAC_LAD_OUT: R2$CBB16/CBB1.2 R9$CBB16/CBB1.2 R32$CBB16.1 R48$CBB16.2 U1$CBB16.3 | length 1608
  Top Layer w7.9: R2$CBB16/CBB1.2@4673.8,8717.1 4703.3,8717.1 v1(4717.1,8731) 4726.2,8740.1 R9$CBB16/CBB1.2@4766.7,8740.1 4766.6,8740.3 4766.6,8763.2 4772.1,8768.7 4922.1,8768.7 4952.1,8798.7 4952.1,8963.7 4962.1,8973.7 5177.1,8973.7 5209.2,9005.8 R48$CBB16.2@5209.2,9048.7 R32$CBB16.1@5209.2,9108.7
  Bottom Layer w7.9: v1(4717.1,8731) 4797.1,8651 4797.1,8343.7 4817.1,8323.7 4932.1,8323.7 4955.7,8300.1 U1$CBB16.3@5098.4,8300.1
$1I33\$1I19\$1N1: R9$CBB16/CBB2.1 U6$CBB16/CBB2.15 | length 333.5
  Top Layer w7.9: R9$CBB16/CBB2.1@4800.8,9192.8 4918,9192.8 5011.3,9099.6 U6$CBB16/CBB2.15@5095.7,9099.6
$1I33\$1I19\$1N2: R8$CBB16/CBB2.1 U6$CBB16/CBB2.1 | length 77.6
  Top Layer w7.9: R8$CBB16/CBB2.1@4800.8,9147.8 4875.9,9147.8 U6$CBB16/CBB2.1@4877.6,9149.6
$1I33\$1I19\$1N3: R7$CBB16/CBB2.1 U6$CBB16/CBB2.2 | length 77.6
  Top Layer w7.9: R7$CBB16/CBB2.1@4800.8,9097.8 4875.9,9097.8 U6$CBB16/CBB2.2@4877.6,9099.6
$1I33\$1I19\$1N4: R6$CBB16/CBB2.1 U6$CBB16/CBB2.3 | length 77.6
  Top Layer w7.9: R6$CBB16/CBB2.1@4800.8,9047.8 4875.9,9047.8 U6$CBB16/CBB2.3@4877.6,9049.6
$1I33\$1I19\$1N5: R5$CBB16/CBB2.1 U6$CBB16/CBB2.4 | length 77.6
  Top Layer w7.9: R5$CBB16/CBB2.1@4800.8,8997.8 4875.9,8997.8 U6$CBB16/CBB2.4@4877.6,8999.6
$1I33\$1I19\$1N6: R4$CBB16/CBB2.1 U6$CBB16/CBB2.5 | length 77.6
  Top Layer w7.9: R4$CBB16/CBB2.1@4800.8,8947.8 4875.9,8947.8 U6$CBB16/CBB2.5@4877.6,8949.6
$1I33\$1I19\$1N7: R3$CBB16/CBB2.1 U6$CBB16/CBB2.6 | length 77.6
  Top Layer w7.9: R3$CBB16/CBB2.1@4800.8,8897.8 4875.9,8897.8 U6$CBB16/CBB2.6@4877.6,8899.6
$1I33\$1I19\$1N8: R1$CBB16/CBB2.1 U6$CBB16/CBB2.7 | length 77.6
  Top Layer w7.9: R1$CBB16/CBB2.1@4800.8,8847.8 4875.9,8847.8 U6$CBB16/CBB2.7@4877.6,8849.6
$1I33\$1I19\$1N11: R2$CBB16/CBB2.1 R8$CBB16/CBB2.2 R10$CBB16/CBB2.2 | length 99.6
  Top Layer w7.9: R2$CBB16/CBB2.1@4673.8,9135.8 4717.9,9135.8 R10$CBB16/CBB2.2@4718.8,9134.9 4719.9,9133.7 4732.1,9133.7 4746.2,9147.8 R8$CBB16/CBB2.2@4766.7,9147.8
$1I33\$1I19\$1N12: R6$CBB16/CBB2.2 R11$CBB16/CBB2.1 R12$CBB16/CBB2.2 | length 102.8
  Top Layer w7.9: R11$CBB16/CBB2.1@4673.8,9055.8 4690.1,9055.8 4706,9039.9 R12$CBB16/CBB2.2@4718.8,9039.9 4738.3,9039.9 4746.2,9047.8 R6$CBB16/CBB2.2@4766.7,9047.8
$1I33\$1I19\$1N13: R7$CBB16/CBB2.2 R10$CBB16/CBB2.1 R11$CBB16/CBB2.2 | length 98.7
  Top Layer w7.9: R11$CBB16/CBB2.2@4673.8,9089.9 4683.3,9089.9 4694.2,9100.8 R10$CBB16/CBB2.1@4718.8,9100.8 4763.8,9100.8 R7$CBB16/CBB2.2@4766.7,9097.8
$1I33\$1I19\$1N14: R4$CBB16/CBB2.2 R13$CBB16/CBB2.1 R14$CBB16/CBB2.2 | length 102.8
  Top Layer w7.9: R13$CBB16/CBB2.1@4673.8,8955.8 4690.1,8955.8 4706,8939.9 R14$CBB16/CBB2.2@4718.8,8939.9 4733.3,8939.9 4741.2,8947.8 R4$CBB16/CBB2.2@4766.7,8947.8
$1I33\$1I19\$1N15: R5$CBB16/CBB2.2 R12$CBB16/CBB2.1 R13$CBB16/CBB2.2 | length 102.8
  Top Layer w7.9: R13$CBB16/CBB2.2@4673.8,8989.9 4688.3,8989.9 4704.2,9005.8 R12$CBB16/CBB2.1@4718.8,9005.8 4735.1,9005.8 4743,8997.8 R5$CBB16/CBB2.2@4766.7,8997.8
$1I33\$1I19\$1N16: R1$CBB16/CBB2.2 R15$CBB16/CBB2.1 R16$CBB16/CBB2.2 | length 143.3
  Top Layer w7.9: R15$CBB16/CBB2.1@4673.8,8860.8 4705.1,8860.8 4718,8847.8 R1$CBB16/CBB2.2@4766.7,8847.8 R16$CBB16/CBB2.2@4766.7,8802.8
$1I33\$1I19\$1N17: R3$CBB16/CBB2.2 R14$CBB16/CBB2.1 R15$CBB16/CBB2.2 | length 100.8
  Top Layer w7.9: R15$CBB16/CBB2.2@4673.8,8894.9 4688.3,8894.9 4699.2,8905.8 R14$CBB16/CBB2.1@4718.8,8905.8 4740.1,8905.8 4747.1,8898.7 4765.8,8898.7 R3$CBB16/CBB2.2@4766.7,8897.8
$1I33\$1I19\DAC_LAD_OUT: R2$CBB16/CBB2.2 R9$CBB16/CBB2.2 R98$CBB16.1 R99$CBB16.2 U1$CBB16.5 | length 1682
  Top Layer w7.9: R2$CBB16/CBB2.2@4673.8,9169.9 4703.3,9169.9 v1(4717.1,9183.7) 4726.2,9192.8 R9$CBB16/CBB2.2@4766.7,9192.8 4766.7,9208.4 4787.1,9228.7 5167.1,9228.7 5237.1,9158.7 5237.1,9056.3 5235.9,9055 5235.9,9040.3 5237.1,9039 5237.1,8998.7 5209.2,8970.8 R98$CBB16.1@5209.2,8654.2 R99$CBB16.2@5209.2,8596 ; v1(5203.4,8354.1) 5209.2,8359.9 R99$CBB16.2@5209.2,8594.2
  Bottom Layer w7.9: U1$CBB16.5@5098.4,8200.1 5168.5,8200.1 5192.1,8223.7 5192.1,8342.9 v1(5203.4,8354.1)
$1I33\$1I21\$1N1: R9$CBB16/CBB3.1 U6$CBB16/CBB3.15 | length 333.5
  Top Layer w7.9: R9$CBB16/CBB3.1@4800.8,8287.3 4918,8287.3 5011.3,8194.1 U6$CBB16/CBB3.15@5095.7,8194.1
$1I33\$1I21\$1N2: R8$CBB16/CBB3.1 U6$CBB16/CBB3.1 | length 77.6
  Top Layer w7.9: R8$CBB16/CBB3.1@4800.8,8242.3 4875.9,8242.3 U6$CBB16/CBB3.1@4877.6,8244.1
$1I33\$1I21\$1N3: R7$CBB16/CBB3.1 U6$CBB16/CBB3.2 | length 77.6
  Top Layer w7.9: R7$CBB16/CBB3.1@4800.8,8192.3 4875.9,8192.3 U6$CBB16/CBB3.2@4877.6,8194.1
$1I33\$1I21\$1N4: R6$CBB16/CBB3.1 U6$CBB16/CBB3.3 | length 77.6
  Top Layer w7.9: R6$CBB16/CBB3.1@4800.8,8142.3 4875.9,8142.3 U6$CBB16/CBB3.3@4877.6,8144.1
$1I33\$1I21\$1N5: R5$CBB16/CBB3.1 U6$CBB16/CBB3.4 | length 77.6
  Top Layer w7.9: R5$CBB16/CBB3.1@4800.8,8092.3 4875.9,8092.3 U6$CBB16/CBB3.4@4877.6,8094.1
$1I33\$1I21\$1N6: R4$CBB16/CBB3.1 U6$CBB16/CBB3.5 | length 77.6
  Top Layer w7.9: R4$CBB16/CBB3.1@4800.8,8042.3 4875.9,8042.3 U6$CBB16/CBB3.5@4877.6,8044.1
$1I33\$1I21\$1N7: R3$CBB16/CBB3.1 U6$CBB16/CBB3.6 | length 77.6
  Top Layer w7.9: R3$CBB16/CBB3.1@4800.8,7992.3 4875.9,7992.3 U6$CBB16/CBB3.6@4877.6,7994.1
$1I33\$1I21\$1N8: R1$CBB16/CBB3.1 U6$CBB16/CBB3.7 | length 77.6
  Top Layer w7.9: R1$CBB16/CBB3.1@4800.8,7942.3 4875.9,7942.3 U6$CBB16/CBB3.7@4877.6,7944.1
$1I33\$1I21\$1N11: R2$CBB16/CBB3.1 R8$CBB16/CBB3.2 R10$CBB16/CBB3.2 | length 99.6
  Top Layer w7.9: R2$CBB16/CBB3.1@4673.8,8230.3 4717.9,8230.3 R10$CBB16/CBB3.2@4718.8,8229.4 4719.9,8228.2 4732.1,8228.2 4746.2,8242.3 R8$CBB16/CBB3.2@4766.7,8242.3
$1I33\$1I21\$1N12: R6$CBB16/CBB3.2 R11$CBB16/CBB3.1 R12$CBB16/CBB3.2 | length 102.8
  Top Layer w7.9: R11$CBB16/CBB3.1@4673.8,8150.3 4690.1,8150.3 4706,8134.4 R12$CBB16/CBB3.2@4718.8,8134.4 4738.3,8134.4 4746.2,8142.3 R6$CBB16/CBB3.2@4766.7,8142.3
$1I33\$1I21\$1N13: R7$CBB16/CBB3.2 R10$CBB16/CBB3.1 R11$CBB16/CBB3.2 | length 98.7
  Top Layer w7.9: R11$CBB16/CBB3.2@4673.8,8184.4 4683.3,8184.4 4694.2,8195.3 R10$CBB16/CBB3.1@4718.8,8195.3 4763.8,8195.3 R7$CBB16/CBB3.2@4766.7,8192.3
$1I33\$1I21\$1N14: R4$CBB16/CBB3.2 R13$CBB16/CBB3.1 R14$CBB16/CBB3.2 | length 102.8
  Top Layer w7.9: R13$CBB16/CBB3.1@4673.8,8050.3 4690.1,8050.3 4706,8034.4 R14$CBB16/CBB3.2@4718.8,8034.4 4733.3,8034.4 4741.2,8042.3 R4$CBB16/CBB3.2@4766.7,8042.3
$1I33\$1I21\$1N15: R5$CBB16/CBB3.2 R12$CBB16/CBB3.1 R13$CBB16/CBB3.2 | length 102.8
  Top Layer w7.9: R13$CBB16/CBB3.2@4673.8,8084.4 4688.3,8084.4 4704.2,8100.3 R12$CBB16/CBB3.1@4718.8,8100.3 4735.1,8100.3 4743,8092.3 R5$CBB16/CBB3.2@4766.7,8092.3
$1I33\$1I21\$1N16: R1$CBB16/CBB3.2 R15$CBB16/CBB3.1 R16$CBB16/CBB3.2 | length 143.3
  Top Layer w7.9: R15$CBB16/CBB3.1@4673.8,7955.3 4705.1,7955.3 4718,7942.3 R1$CBB16/CBB3.2@4766.7,7942.3 R16$CBB16/CBB3.2@4766.7,7897.3
$1I33\$1I21\$1N17: R3$CBB16/CBB3.2 R14$CBB16/CBB3.1 R15$CBB16/CBB3.2 | length 100.8
  Top Layer w7.9: R15$CBB16/CBB3.2@4673.8,7989.4 4688.3,7989.4 4699.2,8000.3 R14$CBB16/CBB3.1@4718.8,8000.3 4740.1,8000.3 4747.1,7993.2 4765.8,7993.2 R3$CBB16/CBB3.2@4766.7,7992.3
$1I33\$1I21\DAC_LAD_OUT: R2$CBB16/CBB3.2 R9$CBB16/CBB3.2 R100$CBB16.1 R101$CBB16.2 U1$CBB16.10 | length 907.2
  Top Layer w7.9: R2$CBB16/CBB3.2@4673.8,8264.4 4703.3,8264.4 v1(4717.1,8278.2) 4726.2,8287.3 R9$CBB16/CBB3.2@4766.7,8287.3 4766.7,8303.9 4769.8,8306.9 5159.5,8306.9 5168.5,8297.9 5168.5,8282.9 5209.2,8242.2 R100$CBB16.1@5209.2,8199.2 R101$CBB16.2@5209.2,8143.2
  Bottom Layer w7.9: v1(4717.1,8278.2) 4717.1,8253.7 4770.7,8200.1 U1$CBB16.10@4880.3,8200.1
$1I33\$1I23\$1N1: R9$CBB16/CBB4.1 U6$CBB16/CBB4.15 | length 333.5
  Top Layer w7.9: R9$CBB16/CBB4.1@4800.8,7834.5 4918,7834.5 5011.3,7741.3 U6$CBB16/CBB4.15@5095.7,7741.3
$1I33\$1I23\$1N2: R8$CBB16/CBB4.1 U6$CBB16/CBB4.1 | length 77.6
  Top Layer w7.9: R8$CBB16/CBB4.1@4800.8,7789.5 4875.9,7789.5 U6$CBB16/CBB4.1@4877.6,7791.3
$1I33\$1I23\$1N3: R7$CBB16/CBB4.1 U6$CBB16/CBB4.2 | length 77.6
  Top Layer w7.9: R7$CBB16/CBB4.1@4800.8,7739.5 4875.9,7739.5 U6$CBB16/CBB4.2@4877.6,7741.3
$1I33\$1I23\$1N4: R6$CBB16/CBB4.1 U6$CBB16/CBB4.3 | length 77.6
  Top Layer w7.9: R6$CBB16/CBB4.1@4800.8,7689.5 4875.9,7689.5 U6$CBB16/CBB4.3@4877.6,7691.3
$1I33\$1I23\$1N5: R5$CBB16/CBB4.1 U6$CBB16/CBB4.4 | length 77.6
  Top Layer w7.9: R5$CBB16/CBB4.1@4800.8,7639.5 4875.9,7639.5 U6$CBB16/CBB4.4@4877.6,7641.3
$1I33\$1I23\$1N6: R4$CBB16/CBB4.1 U6$CBB16/CBB4.5 | length 77.6
  Top Layer w7.9: R4$CBB16/CBB4.1@4800.8,7589.5 4875.9,7589.5 U6$CBB16/CBB4.5@4877.6,7591.3
$1I33\$1I23\$1N7: R3$CBB16/CBB4.1 U6$CBB16/CBB4.6 | length 77.6
  Top Layer w7.9: R3$CBB16/CBB4.1@4800.8,7539.5 4875.9,7539.5 U6$CBB16/CBB4.6@4877.6,7541.3
$1I33\$1I23\$1N8: R1$CBB16/CBB4.1 U6$CBB16/CBB4.7 | length 77.6
  Top Layer w7.9: R1$CBB16/CBB4.1@4800.8,7489.5 4875.9,7489.5 U6$CBB16/CBB4.7@4877.6,7491.3
$1I33\$1I23\$1N11: R2$CBB16/CBB4.1 R8$CBB16/CBB4.2 R10$CBB16/CBB4.2 | length 99.5
  Top Layer w7.9: R2$CBB16/CBB4.1@4673.8,7777.5 4717.9,7777.5 R10$CBB16/CBB4.2@4718.8,7776.6 4719.9,7775.5 4732.1,7775.5 4746.2,7789.5 R8$CBB16/CBB4.2@4766.7,7789.5
$1I33\$1I23\$1N12: R6$CBB16/CBB4.2 R11$CBB16/CBB4.1 R12$CBB16/CBB4.2 | length 102.8
  Top Layer w7.9: R11$CBB16/CBB4.1@4673.8,7697.5 4690.1,7697.5 4706,7681.6 R12$CBB16/CBB4.2@4718.8,7681.6 4738.3,7681.6 4746.2,7689.5 R6$CBB16/CBB4.2@4766.7,7689.5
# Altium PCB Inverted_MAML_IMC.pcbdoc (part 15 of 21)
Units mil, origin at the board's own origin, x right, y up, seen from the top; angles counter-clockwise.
Board outline 7677.1 x 6771.6 mil, 6 copper layers (Top Layer, Inner1, Inner2, Inner3, Inner4, Bottom Layer), stack 60.7 mil thick; 2730 components, 1566 nets, 7761 pads, 3719 vias.

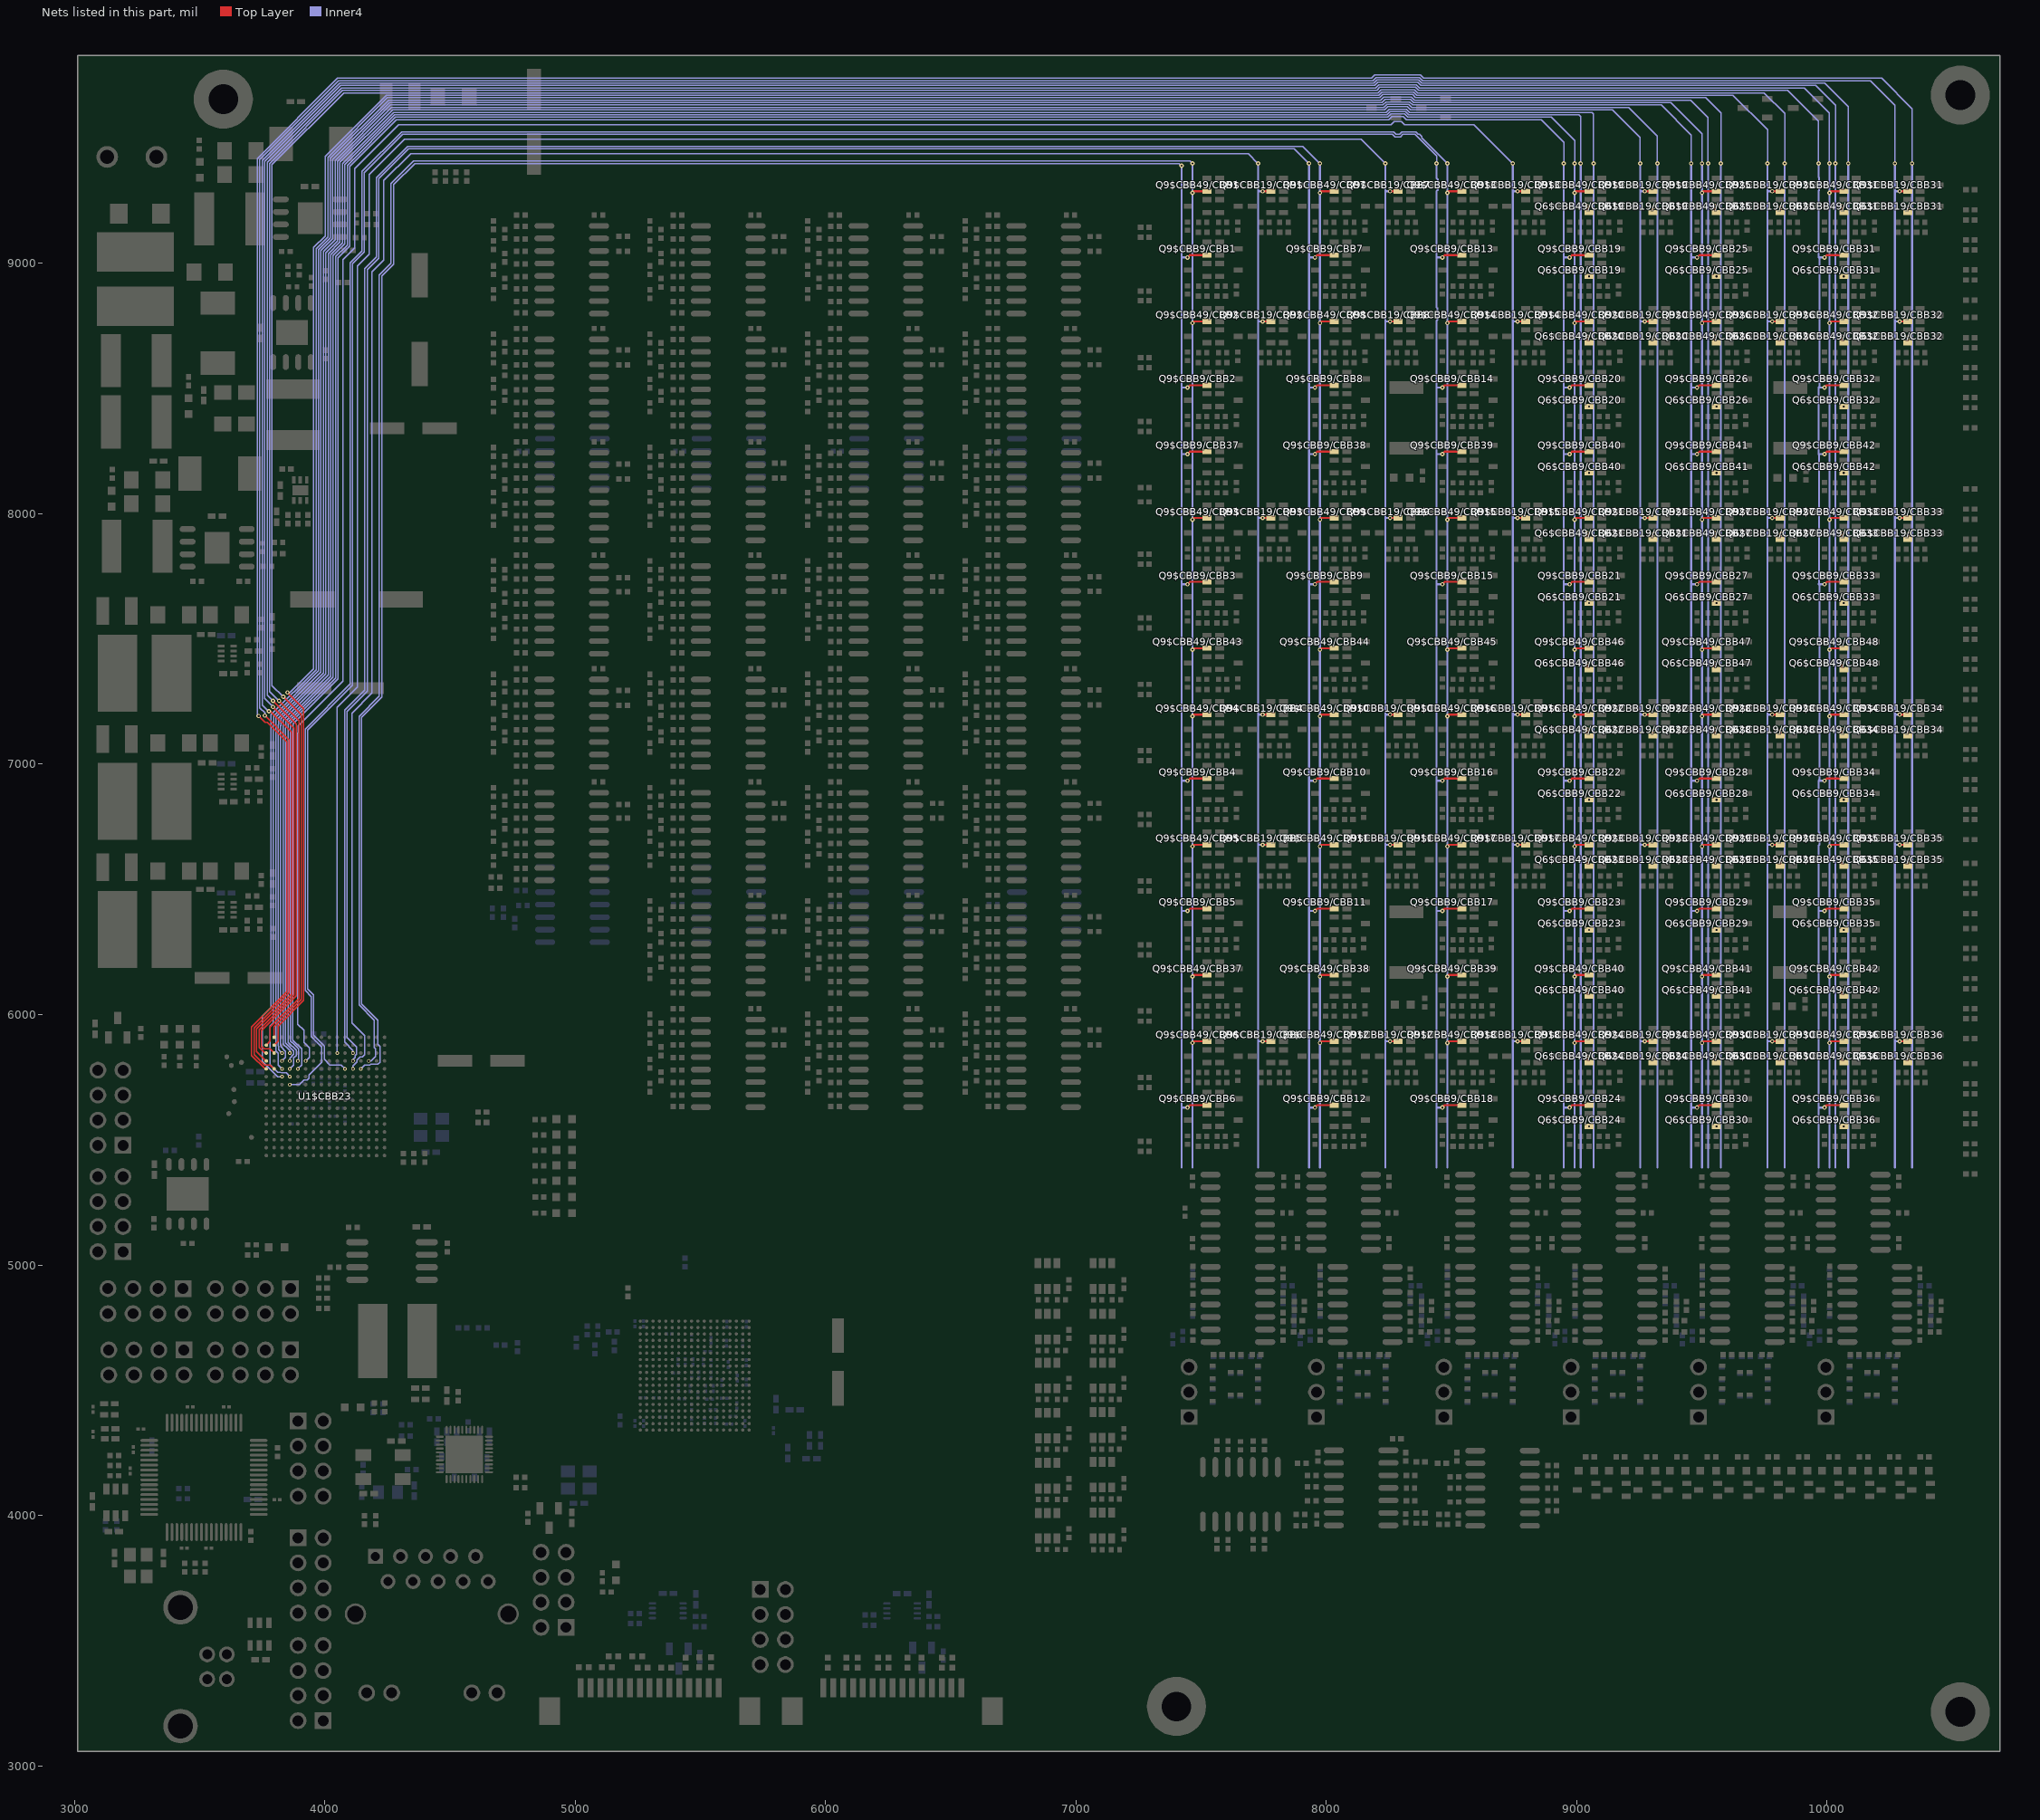
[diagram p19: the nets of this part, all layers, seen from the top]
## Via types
v1: diameter 17.7, hole 7.9, Top Layer to Bottom Layer, 3387 vias
v2: diameter 13.8, hole 7.9, Top Layer to Bottom Layer, 287 vias
v3: diameter 23.6, hole 11.8, Top Layer to Bottom Layer, 45 vias

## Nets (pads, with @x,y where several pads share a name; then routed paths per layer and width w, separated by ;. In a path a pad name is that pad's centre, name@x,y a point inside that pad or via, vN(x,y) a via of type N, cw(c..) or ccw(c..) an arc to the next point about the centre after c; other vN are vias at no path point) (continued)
G+4_MAT(3): Q6$CBB49/CBB19.1 Q6$CBB49/CBB20.1 Q6$CBB49/CBB21.1 Q6$CBB49/CBB22.1 Q6$CBB49/CBB23.1 Q6$CBB49/CBB24.1 Q6$CBB49/CBB40.1 Q6$CBB49/CBB46.1 U1$CBB23.E4 | length 13408
  Top Layer w7.9: v1(9042.3,5833.9) 9042.3,5815.5 Q6$CBB49/CBB24.1@9049.7,5808.1 ; v1(9042.3,6098.9) 9042.3,6080.5 Q6$CBB49/CBB40.1@9049.7,6073.1 ; v1(9042.3,6618.9) 9042.3,6600.5 Q6$CBB49/CBB23.1@9049.7,6593.1 ; v1(9042.3,7138.9) 9042.3,7120.5 Q6$CBB49/CBB22.1@9049.7,7113.1 ; v1(9042.3,7403.9) 9042.3,7385.5 Q6$CBB49/CBB46.1@9049.7,7378.1 ; v1(9042.3,7923.9) 9042.3,7905.5 Q6$CBB49/CBB21.1@9049.7,7898.1 ; v1(9042.3,8708.9) 9042.3,8690.5 Q6$CBB49/CBB20.1@9049.7,8683.1 ; v1(9042.3,9228.9) 9042.3,9210.5 Q6$CBB49/CBB19.1@9049.7,9203.1
  Inner4 w4.7: v2(3861.1,5783.4) 3876.3,5798.5 3876.3,5827 3886.3,5837.1 3886.3,5857.2 3854.5,5889 3854.5,5889.6 3853.5,5890.6 3853.5,7141.1 3854.4,7142 3854.4,7168.9 4033.8,7348.3 4033.8,9030.8 4080.6,9077.5 4080.6,9395.1 4279,9593.5 8242.1,9593.5 8254.7,9606.1 8316.4,9606.1 8329,9593.5 9009.5,9593.5 9016,9587.1 v1(9016,9398.7)
  Inner4 w7.9: 9016,5388.7 9016,5836.2 ; v1(9016,9398.7) 9016,9231.2 ; v1(9042.3,5833.9) 9018.2,5833.9 9016,5836.2 ; v1(9042.3,6098.9) 9018.2,6098.9 9016,6101.2 ; v1(9042.3,6618.9) 9018.2,6618.9 9016,6621.2 ; v1(9042.3,7138.9) 9018.2,7138.9 9016,7141.2 ; v1(9042.3,7403.9) 9018.2,7403.9 9016,7406.2 ; v1(9042.3,7923.9) 9018.2,7923.9 9016,7926.2 ; v1(9042.3,8708.9) 9018.2,8708.9 9016,8711.2 ; v1(9042.3,9228.9) 9018.2,9228.9 9016,9231.2 ; 9016,5836.2 9016,6101.2 ; 9016,6101.2 9016,6621.2 ; 9016,6621.2 9016,7141.2 ; 9016,7141.2 9016,7406.2 ; 9016,7406.2 9016,7926.2 ; 9016,7926.2 9016,8711.2 ; 9016,8711.2 9016,9231.2
G+4_MAT(8): Q6$CBB9/CBB19.1 Q6$CBB9/CBB20.1 Q6$CBB9/CBB21.1 Q6$CBB9/CBB22.1 Q6$CBB9/CBB23.1 Q6$CBB9/CBB24.1 Q6$CBB9/CBB40.1 U1$CBB23.D4 | length 13124.4
  Inner4 w4.7: v2(3861.1,5814.9) 3861.1,5826 3876.3,5841.1 3876.3,5854.4 3851.4,5879.3 3850.5,5879.3 3844.8,5884.9 3844.8,5885.6 3843.8,5886.5 3843.8,7145.1 3844.6,7146 3844.6,7172.9 4024.1,7352.4 4024.1,9034.8 4070.8,9081.6 4070.8,9399.1 4275,9603.3 8238,9603.3 8250.6,9615.9 8320.5,9615.9 8333.1,9603.3 9061.1,9603.3 9067.3,9597.1 v1(9067.3,9398.7)
  Inner4 w7.9: v1(9049.7,5553.1) 9067.1,5553.1 9067.3,5553 ; v1(9049.7,6338.1) 9067.1,6338.1 9067.3,6338 ; v1(9049.7,6858.1) 9067.1,6858.1 9067.3,6858 ; v1(9049.7,7643.1) 9067.1,7643.1 9067.3,7643 ; v1(9049.7,8163.1) 9067.1,8163.1 9067.3,8163 ; v1(9049.7,8428.1) 9067.1,8428.1 9067.3,8428 ; v1(9049.7,8948.1) 9067.1,8948.1 9067.3,8948 ; 9067.3,5388.7 9067.3,5553 ; v1(9067.3,9398.7) 9067.3,8948 ; 9067.3,5553 9067.3,6338 ; 9067.3,6338 9067.3,6858 ; 9067.3,6858 9067.3,7643 ; 9067.3,7643 9067.3,8163 ; 9067.3,8163 9067.3,8428 ; 9067.3,8428 9067.3,8948
G+4_MAT(33): Q6$CBB19/CBB19.1 Q6$CBB19/CBB20.1 Q6$CBB19/CBB21.1 Q6$CBB19/CBB22.1 Q6$CBB19/CBB23.1 Q6$CBB19/CBB24.1 U1$CBB23.D3 | length 13455.1
  Top Layer w7.9: Q6$CBB19/CBB24.1@9304.7,5808.1 9304.7,5826.1 v1@9307.3,5828.7 ; Q6$CBB19/CBB23.1@9304.7,6593.1 9304.7,6611.1 v1@9307.3,6613.7 ; Q6$CBB19/CBB22.1@9304.7,7113.1 9304.7,7131.1 v1@9307.3,7133.7 ; Q6$CBB19/CBB21.1@9304.7,7898.1 9304.7,7916.1 v1@9307.3,7918.7 ; Q6$CBB19/CBB20.1@9304.7,8683.1 9304.7,8701.1 v1@9307.3,8703.7 ; Q6$CBB19/CBB19.1@9304.7,9203.1 9304.7,9221.1 v1@9307.3,9223.7
  Inner4 w4.7: v2(3829.6,5814.9) 3844.1,5829.4 3844.1,5853.1 3825.3,5872 3825.3,5877.5 3824.3,5878.5 3824.3,7153.2 3825.2,7154.1 3825.2,7181 4004.6,7360.4 4004.6,9042.9 4051.4,9089.6 4051.4,9407.1 4267,9622.7 8230,9622.7 8242.6,9635.3 8328.5,9635.3 8341.1,9622.7 9207.5,9622.7 9322.3,9508 v1(9322.3,9398.7)
  Inner4 w7.9: v1(9308.1,5829.5) 9308.9,5828.7 9322.3,5828.7 ; v1(9308.1,6614.5) 9308.9,6613.7 9322.3,6613.7 ; v1(9308.1,7134.5) 9308.9,7133.7 9322.3,7133.7 ; v1(9308.1,7919.5) 9308.9,7918.7 9322.3,7918.7 ; v1(9308.1,8704.5) 9308.9,8703.7 9322.3,8703.7 ; v1(9308.1,9224.5) 9308.9,9223.7 9322.3,9223.7 ; 9322.3,5388.7 9322.3,5828.7 ; v1(9322.3,9398.7) 9322.3,9223.7 ; 9322.3,5828.7 9322.3,6613.7 ; 9322.3,6613.7 9322.3,7133.7 ; 9322.3,7133.7 9322.3,7918.7 ; 9322.3,7918.7 9322.3,8703.7 ; 9322.3,8703.7 9322.3,9223.7
G+5_MAT(3): Q6$CBB49/CBB25.1 Q6$CBB49/CBB26.1 Q6$CBB49/CBB27.1 Q6$CBB49/CBB28.1 Q6$CBB49/CBB29.1 Q6$CBB49/CBB30.1 Q6$CBB49/CBB41.1 Q6$CBB49/CBB47.1 U1$CBB23.F4 | length 14098.9
  Top Layer w7.9: v1(9551,5833.9) 9551,5815.5 Q6$CBB49/CBB30.1@9558.4,5808.1 ; v1(9551,6098.9) 9551,6080.5 Q6$CBB49/CBB41.1@9558.4,6073.1 ; v1(9551,6618.9) 9551,6600.5 Q6$CBB49/CBB29.1@9558.4,6593.1 ; v1(9551,7138.9) 9551,7120.5 Q6$CBB49/CBB28.1@9558.4,7113.1 ; v1(9551,7403.9) 9551,7385.5 Q6$CBB49/CBB47.1@9558.4,7378.1 ; v1(9551,7923.9) 9551,7905.5 Q6$CBB49/CBB27.1@9558.4,7898.1 ; v1(9551,8708.9) 9551,8690.5 Q6$CBB49/CBB26.1@9558.4,8683.1 ; v1(9551,9228.9) 9551,9210.5 Q6$CBB49/CBB25.1@9558.4,9203.1
  Inner4 w4.7: v2(3861.1,5751.9) 3846.3,5766.8 3827.6,5766.8 3824.3,5770 3812.8,5770 3781.9,5800.9 3781.9,5953.5 3795.2,5966.8 3795.2,7165.3 3796,7166.2 3796,7193.1 3975.4,7372.5 3975.4,9054.9 4022.2,9101.7 4022.2,9419.2 4254.9,9651.9 8217.9,9651.9 8230.5,9664.5 8340.6,9664.5 8353.2,9651.9 9456.3,9651.9 9524.7,9583.5 v1(9524.7,9398.7)
  Inner4 w7.9: 9524.7,5388.7 9524.7,5836.2 ; v1(9524.7,9398.7) 9524.7,9231.2 ; v1(9551,5833.9) 9526.9,5833.9 9524.7,5836.2 ; v1(9551,6098.9) 9526.9,6098.9 9524.7,6101.2 ; v1(9551,6618.9) 9526.9,6618.9 9524.7,6621.2 ; v1(9551,7138.9) 9526.9,7138.9 9524.7,7141.2 ; v1(9551,7403.9) 9526.9,7403.9 9524.7,7406.2 ; v1(9551,7923.9) 9526.9,7923.9 9524.7,7926.2 ; v1(9551,8708.9) 9526.9,8708.9 9524.7,8711.2 ; v1(9551,9228.9) 9526.9,9228.9 9524.7,9231.2 ; 9524.7,5836.2 9524.7,6101.2 ; 9524.7,6101.2 9524.7,6621.2 ; 9524.7,6621.2 9524.7,7141.2 ; 9524.7,7141.2 9524.7,7406.2 ; 9524.7,7406.2 9524.7,7926.2 ; 9524.7,7926.2 9524.7,8711.2 ; 9524.7,8711.2 9524.7,9231.2
G+5_MAT(8): Q6$CBB9/CBB25.1 Q6$CBB9/CBB26.1 Q6$CBB9/CBB27.1 Q6$CBB9/CBB28.1 Q6$CBB9/CBB29.1 Q6$CBB9/CBB30.1 Q6$CBB9/CBB41.1 U1$CBB23.F3 | length 13854.5
  Inner4 w4.7: v2(3829.6,5751.9) 3812.8,5751.9 3751.8,5813 3751.8,5993.7 3785.4,6027.4 3785.4,7169.3 3786.3,7170.2 3786.3,7197.1 3965.7,7376.5 3965.7,9059 4012.5,9105.7 4012.5,9423.2 4250.8,9661.6 8213.9,9661.6 8226.5,9674.2 8344.6,9674.2 8357.2,9661.6 9514.8,9661.6 9576,9600.5 v1(9576,9398.7)
  Inner4 w7.9: v1(9558.4,5553.1) 9575.8,5553.1 9576,5553 ; v1(9558.4,6338.1) 9575.8,6338.1 9576,6338 ; v1(9558.4,6858.1) 9575.8,6858.1 9576,6858 ; v1(9558.4,7643.1) 9575.8,7643.1 9576,7643 ; v1(9558.4,8163.1) 9575.8,8163.1 9576,8163 ; v1(9558.4,8428.1) 9575.8,8428.1 9576,8428 ; v1(9558.4,8948.1) 9575.8,8948.1 9576,8948 ; 9576,5388.7 9576,5553 ; v1(9576,9398.7) 9576,8948 ; 9576,5553 9576,6338 ; 9576,6338 9576,6858 ; 9576,6858 9576,7643 ; 9576,7643 9576,8163 ; 9576,8163 9576,8428 ; 9576,8428 9576,8948
G+5_MAT(33): Q6$CBB19/CBB25.1 Q6$CBB19/CBB26.1 Q6$CBB19/CBB27.1 Q6$CBB19/CBB28.1 Q6$CBB19/CBB29.1 Q6$CBB19/CBB30.1 U1$CBB23.A2 | length 14210.2
  Top Layer w4.7: U1$CBB23.A2@3798.2,5909.4 3798.2,5952 3906.7,6060.6 3906.7,7197.5 v1(3834.6,7269.6)
  Top Layer w7.9: Q6$CBB19/CBB30.1@9813.4,5808.1 9813.4,5826.1 v1@9816,5828.7 ; Q6$CBB19/CBB29.1@9813.4,6593.1 9813.4,6611.1 v1@9816,6613.7 ; Q6$CBB19/CBB28.1@9813.4,7113.1 9813.4,7131.1 v1@9816,7133.7 ; Q6$CBB19/CBB27.1@9813.4,7898.1 9813.4,7916.1 v1@9816,7918.7 ; Q6$CBB19/CBB26.1@9813.4,8683.1 9813.4,8701.1 v1@9816,8703.7 ; Q6$CBB19/CBB25.1@9813.4,9203.1 9813.4,9221.1 v1@9816,9223.7
  Inner4 w4.7: v1(3834.6,7269.6) 3789.9,7314.3 3789.9,9395 4075.9,9681.1 8205.8,9681.1 8218.4,9693.7 8352.7,9693.7 8365.3,9681.1 9748.4,9681.1 9831,9598.5 v1(9831,9398.7)
  Inner4 w7.9: v1(9816.8,5829.5) 9817.6,5828.7 9831,5828.7 ; v1(9816.8,6614.5) 9817.6,6613.7 9831,6613.7 ; v1(9816.8,7134.5) 9817.6,7133.7 9831,7133.7 ; v1(9816.8,7919.5) 9817.6,7918.7 9831,7918.7 ; v1(9816.8,8704.5) 9817.6,8703.7 9831,8703.7 ; v1(9816.8,9224.5) 9817.6,9223.7 9831,9223.7 ; 9831,5388.7 9831,5828.7 ; v1(9831,9398.7) 9831,9223.7 ; 9831,5828.7 9831,6613.7 ; 9831,6613.7 9831,7133.7 ; 9831,7133.7 9831,7918.7 ; 9831,7918.7 9831,8703.7 ; 9831,8703.7 9831,9223.7
G+6_MAT(3): Q6$CBB49/CBB31.1 Q6$CBB49/CBB32.1 Q6$CBB49/CBB33.1 Q6$CBB49/CBB34.1 Q6$CBB49/CBB35.1 Q6$CBB49/CBB36.1 Q6$CBB49/CBB42.1 Q6$CBB49/CBB48.1 U1$CBB23.C1 | length 14817.5
  Top Layer w4.7: U1$CBB23.C1@3766.7,5846.4 3763.9,5849.1 3757.8,5849.1 3737.7,5869.2 3737.7,5939.2 3877.5,6079 3877.5,7143 3793.8,7226.7 v1(3793.8,7228.7)
  Top Layer w7.9: v1(10059.7,5833.9) 10059.7,5815.5 Q6$CBB49/CBB36.1@10067.1,5808.1 ; v1(10059.7,6098.9) 10059.7,6080.5 Q6$CBB49/CBB42.1@10067.1,6073.1 ; v1(10059.7,6618.9) 10059.7,6600.5 Q6$CBB49/CBB35.1@10067.1,6593.1 ; v1(10059.7,7138.9) 10059.7,7120.5 Q6$CBB49/CBB34.1@10067.1,7113.1 ; v1(10059.7,7403.9) 10059.7,7385.5 Q6$CBB49/CBB48.1@10067.1,7378.1 ; v1(10059.7,7923.9) 10059.7,7905.5 Q6$CBB49/CBB33.1@10067.1,7898.1 ; v1(10059.7,8708.9) 10059.7,8690.5 Q6$CBB49/CBB32.1@10067.1,8683.1 ; v1(10059.7,9228.9) 10059.7,9210.5 Q6$CBB49/CBB31.1@10067.1,9203.1
  Inner4 w4.7: v1(3793.8,7228.7) 3793.8,7232.7 3790.3,7236.2 3787.4,7236.2 3760.4,7263.2 3760.4,9406.8 4063.9,9710.2 8193.7,9710.2 8206.3,9722.8 8364.8,9722.8 8377.4,9710.2 9954.1,9710.2 10033.4,9631 v1(10033.4,9398.7)
  Inner4 w7.9: 10033.4,5388.7 10033.4,5836.2 ; v1(10033.4,9398.7) 10033.4,9231.2 ; v1(10059.7,5833.9) 10035.6,5833.9 10033.4,5836.2 ; v1(10059.7,6098.9) 10035.6,6098.9 10033.4,6101.2 ; v1(10059.7,6618.9) 10035.6,6618.9 10033.4,6621.2 ; v1(10059.7,7138.9) 10035.6,7138.9 10033.4,7141.2 ; v1(10059.7,7403.9) 10035.6,7403.9 10033.4,7406.2 ; v1(10059.7,7923.9) 10035.6,7923.9 10033.4,7926.2 ; v1(10059.7,8708.9) 10035.6,8708.9 10033.4,8711.2 ; v1(10059.7,9228.9) 10035.6,9228.9 10033.4,9231.2 ; 10033.4,5836.2 10033.4,6101.2 ; 10033.4,6101.2 10033.4,6621.2 ; 10033.4,6621.2 10033.4,7141.2 ; 10033.4,7141.2 10033.4,7406.2 ; 10033.4,7406.2 10033.4,7926.2 ; 10033.4,7926.2 10033.4,8711.2 ; 10033.4,8711.2 10033.4,9231.2
G+6_MAT(8): Q6$CBB9/CBB31.1 Q6$CBB9/CBB32.1 Q6$CBB9/CBB33.1 Q6$CBB9/CBB34.1 Q6$CBB9/CBB35.1 Q6$CBB9/CBB36.1 Q6$CBB9/CBB42.1 U1$CBB23.D1 | length 14595.6
  Top Layer w4.7: U1$CBB23.D1@3766.7,5814.9 3765.9,5814.9 3728,5852.8 3728,5943.2 3867.8,6083 3867.8,7126.6 3782.4,7211.9 v1(3777,7211.9)
  Inner4 w4.7: v1(3777,7211.9) 3774.4,7211.9 3750.7,7235.6 3750.7,9410.8 4059.8,9720 8189.7,9720 8202.3,9732.6 8368.8,9732.6 8381.4,9720 9990.6,9720 10084.7,9625.9 v1(10084.7,9398.7)
  Inner4 w7.9: v1(10067.1,5553.1) 10084.5,5553.1 10084.7,5553 ; v1(10067.1,6338.1) 10084.5,6338.1 10084.7,6338 ; v1(10067.1,6858.1) 10084.5,6858.1 10084.7,6858 ; v1(10067.1,7643.1) 10084.5,7643.1 10084.7,7643 ; v1(10067.1,8163.1) 10084.5,8163.1 10084.7,8163 ; v1(10067.1,8428.1) 10084.5,8428.1 10084.7,8428 ; v1(10067.1,8948.1) 10084.5,8948.1 10084.7,8948 ; 10084.7,5388.7 10084.7,5553 ; v1(10084.7,9398.7) 10084.7,8948 ; 10084.7,5553 10084.7,6338 ; 10084.7,6338 10084.7,6858 ; 10084.7,6858 10084.7,7643 ; 10084.7,7643 10084.7,8163 ; 10084.7,8163 10084.7,8428 ; 10084.7,8428 10084.7,8948
G+6_MAT(33): Q6$CBB19/CBB31.1 Q6$CBB19/CBB32.1 Q6$CBB19/CBB33.1 Q6$CBB19/CBB34.1 Q6$CBB19/CBB35.1 Q6$CBB19/CBB36.1 U1$CBB23.E1 | length 15022.8
  Top Layer w4.7: v1(3736.4,7192.4) 3762.5,7166.3 3771.8,7166.3 3848.3,7089.8 3848.3,6091.1 3708.3,5951 3708.3,5836.7 3761.6,5783.4 U1$CBB23.E1@3766.7,5783.4
  Top Layer w7.9: Q6$CBB19/CBB36.1@10322.1,5808.1 10322.1,5826.1 v1@10324.7,5828.7 ; Q6$CBB19/CBB35.1@10322.1,6593.1 10322.1,6611.1 v1@10324.7,6613.7 ; Q6$CBB19/CBB34.1@10322.1,7113.1 10322.1,7131.1 v1@10324.7,7133.7 ; Q6$CBB19/CBB33.1@10322.1,7898.1 10322.1,7916.1 v1@10324.7,7918.7 ; Q6$CBB19/CBB32.1@10322.1,8683.1 10322.1,8701.1 v1@10324.7,8703.7 ; Q6$CBB19/CBB31.1@10322.1,9203.1 10322.1,9221.1 v1@10324.7,9223.7
  Inner4 w4.7: v1(3736.4,7192.4) 3731.3,7197.6 3731.3,9418.9 4051.8,9739.4 8181.6,9739.4 8194.2,9752 8376.9,9752 8389.5,9739.4 10218.1,9739.4 10339.7,9617.8 v1(10339.7,9398.7)
  Inner4 w7.9: v1(10325.5,5829.5) 10326.3,5828.7 10339.7,5828.7 ; v1(10325.5,6614.5) 10326.3,6613.7 10339.7,6613.7 ; v1(10325.5,7134.5) 10326.3,7133.7 10339.7,7133.7 ; v1(10325.5,7919.5) 10326.3,7918.7 10339.7,7918.7 ; v1(10325.5,8704.5) 10326.3,8703.7 10339.7,8703.7 ; v1(10325.5,9224.5) 10326.3,9223.7 10339.7,9223.7 ; 10339.7,5388.7 10339.7,5828.7 ; v1(10339.7,9398.7) 10339.7,9223.7 ; 10339.7,5828.7 10339.7,6613.7 ; 10339.7,6613.7 10339.7,7133.7 ; 10339.7,7133.7 10339.7,7918.7 ; 10339.7,7918.7 10339.7,8703.7 ; 10339.7,8703.7 10339.7,9223.7
G-1_MAT(3): Q9$CBB49/CBB1.1 Q9$CBB49/CBB2.1 Q9$CBB49/CBB3.1 Q9$CBB49/CBB4.1 Q9$CBB49/CBB5.1 Q9$CBB49/CBB6.1 Q9$CBB49/CBB37.1 Q9$CBB49/CBB43.1 U1$CBB23.D14 | length 11326.7
  Top Layer w7.9: v1@7466.2,5888.7 7470.6,5893.1 Q9$CBB49/CBB6.1@7523.6,5893.1 ; v1@7466.2,6153.7 7470.6,6158.1 Q9$CBB49/CBB37.1@7523.6,6158.1 ; v1@7466.2,6673.7 7470.6,6678.1 Q9$CBB49/CBB5.1@7523.6,6678.1 ; v1@7466.2,7193.7 7470.6,7198.1 Q9$CBB49/CBB4.1@7523.6,7198.1 ; v1@7466.2,7458.7 7470.6,7463.1 Q9$CBB49/CBB43.1@7523.6,7463.1 ; v1@7466.2,7978.7 7470.6,7983.1 Q9$CBB49/CBB3.1@7523.6,7983.1 ; v1@7466.2,8763.7 7470.6,8768.1 Q9$CBB49/CBB2.1@7523.6,8768.1 ; v1@7466.2,9283.7 7470.6,9288.1 Q9$CBB49/CBB1.1@7523.6,9288.1
  Inner4 w4.7: v2(4176.1,5814.9) 4185.4,5814.9 4203.5,5833.1 4203.5,5863.2 4198.5,5868.2 4198.5,5978 4137.7,6038.8 4137.7,7191 4218.5,7271.8 4218.5,8954.2 4265.3,9001 4265.3,9318.5 4355.6,9408.8 7456.1,9408.8 v1(7466.2,9398.7)
  Inner4 w7.9: 7466.2,5388.7 v1(7466.2,5886.8) v1(7466.2,6151.8) v1(7466.2,6671.8) v1(7466.2,7191.8) v1(7466.2,7456.8) v1(7466.2,7976.8) v1(7466.2,8761.8) v1(7466.2,9281.8) v1(7466.2,9398.7)
G-1_MAT(8): Q9$CBB9/CBB1.1 Q9$CBB9/CBB2.1 Q9$CBB9/CBB3.1 Q9$CBB9/CBB4.1 Q9$CBB9/CBB5.1 Q9$CBB9/CBB6.1 Q9$CBB9/CBB37.1 U1$CBB23.E13 | length 11600.2
  Top Layer w7.9: v1(7446.2,5628.7) 7455.6,5638.1 Q9$CBB9/CBB6.1@7523.6,5638.1 ; v1(7446.2,6413.7) 7455.6,6423.1 Q9$CBB9/CBB5.1@7523.6,6423.1 ; v1(7446.2,6933.7) 7455.6,6943.1 Q9$CBB9/CBB4.1@7523.6,6943.1 ; v1(7446.2,7718.7) 7455.6,7728.1 Q9$CBB9/CBB3.1@7523.6,7728.1 ; v1(7446.2,8238.7) 7455.6,8248.1 Q9$CBB9/CBB37.1@7523.6,8248.1 ; v1(7446.2,8503.7) 7455.6,8513.1 Q9$CBB9/CBB2.1@7523.6,8513.1 ; v1(7446.2,9023.7) 7455.6,9033.1 Q9$CBB9/CBB1.1@7523.6,9033.1
  Inner4 w4.7: v2(4144.6,5783.4) 4160.1,5798.9 4181.5,5798.9 4184.1,5801.5 4213.1,5801.5 4221.6,5810 4221.6,5873.2 4212.6,5882.3 4212.6,5977.8 4147.4,6042.9 4147.4,7186.9 4228.3,7267.8 4228.3,8950.2 4275,8997 4275,9314.5 4359.6,9399.1 7413.1,9399.1 v1(7422.5,9389.6)
  Inner4 w7.9: 7422.5,5388.7 7422.5,5629.3 ; v1(7422.5,9389.6) 7422.5,9024.3 ; v1(7446.2,5628.7) 7423.1,5628.7 7422.5,5629.3 ; v1(7446.2,6413.7) 7423.1,6413.7 7422.5,6414.3 ; v1(7446.2,6933.7) 7423.1,6933.7 7422.5,6934.3 ; v1(7446.2,7718.7) 7423.1,7718.7 7422.5,7719.3 ; v1(7446.2,8238.7) 7423.1,8238.7 7422.5,8239.3 ; v1(7446.2,8503.7) 7423.1,8503.7 7422.5,8504.3 ; v1(7446.2,9023.7) 7423.1,9023.7 7422.5,9024.3 ; 7422.5,5629.3 7422.5,6414.3 ; 7422.5,6414.3 7422.5,6934.3 ; 7422.5,6934.3 7422.5,7719.3 ; 7422.5,7719.3 7422.5,8239.3 ; 7422.5,8239.3 7422.5,8504.3 ; 7422.5,8504.3 7422.5,9024.3
G-1_MAT(33): Q9$CBB19/CBB1.1 Q9$CBB19/CBB2.1 Q9$CBB19/CBB3.1 Q9$CBB19/CBB4.1 Q9$CBB19/CBB5.1 Q9$CBB19/CBB6.1 U1$CBB23.E12 | length 11519.2
  Top Layer w7.9: v1(7746.2,5893.1) Q9$CBB19/CBB6.1@7778.6,5893.1 ; v1(7746.2,6678.1) Q9$CBB19/CBB5.1@7778.6,6678.1 ; v1(7746.2,7198.1) Q9$CBB19/CBB4.1@7778.6,7198.1 ; v1(7746.2,7983.1) Q9$CBB19/CBB3.1@7778.6,7983.1 ; v1(7746.2,8768.1) Q9$CBB19/CBB2.1@7778.6,8768.1 ; v1(7746.2,9288.1) Q9$CBB19/CBB1.1@7778.6,9288.1
  Inner4 w4.7: v2(4113.1,5783.4) 4113.1,5794.8 4129.3,5811 4129.3,5819 4141.3,5831.1 4151.3,5831.1 4159.4,5839.1 4159.4,5915.7 4108.5,5966.5 4108.5,7203.1 4189.4,7283.9 4189.4,8966.3 4236.1,9013.1 4236.1,9330.6 4343.5,9438 7688.3,9438 v1(7727.5,9398.7)
  Inner4 w7.9: 7727.5,5388.7 7727.5,5891.4 ; v1(7727.5,9398.7) 7727.5,9286.4 ; v1(7746.2,5893.1) 7729.2,5893.1 7727.5,5891.4 ; v1(7746.2,6678.1) 7729.2,6678.1 7727.5,6676.4 ; v1(7746.2,7198.1) 7729.2,7198.1 7727.5,7196.4 ; v1(7746.2,7983.1) 7729.2,7983.1 7727.5,7981.4 ; v1(7746.2,8768.1) 7729.2,8768.1 7727.5,8766.4 ; v1(7746.2,9288.1) 7729.2,9288.1 7727.5,9286.4 ; 7727.5,5891.4 7727.5,6676.4 ; 7727.5,6676.4 7727.5,7196.4 ; 7727.5,7196.4 7727.5,7981.4 ; 7727.5,7981.4 7727.5,8766.4 ; 7727.5,8766.4 7727.5,9286.4
G-2_MAT(3): Q9$CBB49/CBB7.1 Q9$CBB49/CBB8.1 Q9$CBB49/CBB9.1 Q9$CBB49/CBB10.1 Q9$CBB49/CBB11.1 Q9$CBB49/CBB12.1 Q9$CBB49/CBB38.1 Q9$CBB49/CBB44.1 U1$CBB23.C12 | length 11894.6
  Top Layer w7.9: v1@7974.9,5888.7 7979.3,5893.1 Q9$CBB49/CBB12.1@8032.3,5893.1 ; v1@7974.9,6153.7 7979.3,6158.1 Q9$CBB49/CBB38.1@8032.3,6158.1 ; v1@7974.9,6673.7 7979.3,6678.1 Q9$CBB49/CBB11.1@8032.3,6678.1 ; v1@7974.9,7193.7 7979.3,7198.1 Q9$CBB49/CBB10.1@8032.3,7198.1 ; v1@7974.9,7458.7 7979.3,7463.1 Q9$CBB49/CBB44.1@8032.3,7463.1 ; v1@7974.9,7978.7 7979.3,7983.1 Q9$CBB49/CBB9.1@8032.3,7983.1 ; v1@7974.9,8763.7 7979.3,8768.1 Q9$CBB49/CBB8.1@8032.3,8768.1 ; v1@7974.9,9283.7 7979.3,9288.1 Q9$CBB49/CBB7.1@8032.3,9288.1
  Inner4 w4.7: v2(4113.1,5846.4) 4113.1,5856.7 4079.4,5890.4 4079.4,7215.1 4160.2,7296 4160.2,8978.4 4207,9025.2 4207,9342.7 4331.4,9467.1 7906.5,9467.1 v1(7974.9,9398.7)
  Inner4 w7.9: 7974.9,5388.7 v1(7974.9,5886.8) v1(7974.9,6151.8) v1(7974.9,6671.8) v1(7974.9,7191.8) v1(7974.9,7456.8) v1(7974.9,7976.8) v1(7974.9,8761.8) v1(7974.9,9281.8) v1(7974.9,9398.7)
G-2_MAT(8): Q9$CBB9/CBB7.1 Q9$CBB9/CBB8.1 Q9$CBB9/CBB9.1 Q9$CBB9/CBB10.1 Q9$CBB9/CBB11.1 Q9$CBB9/CBB12.1 Q9$CBB9/CBB38.1 U1$CBB23.D12 | length 12133
  Top Layer w7.9: v1(7954.9,5628.7) 7964.3,5638.1 Q9$CBB9/CBB12.1@8032.3,5638.1 ; v1(7954.9,6413.7) 7964.3,6423.1 Q9$CBB9/CBB11.1@8032.3,6423.1 ; v1(7954.9,6933.7) 7964.3,6943.1 Q9$CBB9/CBB10.1@8032.3,6943.1 ; v1(7954.9,7718.7) 7964.3,7728.1 Q9$CBB9/CBB9.1@8032.3,7728.1 ; v1(7954.9,8238.7) 7964.3,8248.1 Q9$CBB9/CBB38.1@8032.3,8248.1 ; v1(7954.9,8503.7) 7964.3,8513.1 Q9$CBB9/CBB8.1@8032.3,8513.1 ; v1(7954.9,9023.7) 7964.3,9033.1 Q9$CBB9/CBB7.1@8032.3,9033.1
  Inner4 w4.7: v2(4113.1,5814.9) 4113.1,5819.7 4122.2,5828.7 4122.2,5836.5 4127.2,5841.6 4127.2,5871.2 4089.1,5909.4 4089.1,7211.1 4169.9,7291.9 4169.9,8974.4 4216.7,9021.1 4216.7,9338.7 4335.4,9457.4 7872.5,9457.4 v1(7931.2,9398.7)
  Inner4 w7.9: 7931.2,5388.7 7931.2,5629.3 ; v1(7931.2,9398.7) 7931.2,9024.3 ; v1(7954.9,5628.7) 7931.8,5628.7 7931.2,5629.3 ; v1(7954.9,6413.7) 7931.8,6413.7 7931.2,6414.3 ; v1(7954.9,6933.7) 7931.8,6933.7 7931.2,6934.3 ; v1(7954.9,7718.7) 7931.8,7718.7 7931.2,7719.3 ; v1(7954.9,8238.7) 7931.8,8238.7 7931.2,8239.3 ; v1(7954.9,8503.7) 7931.8,8503.7 7931.2,8504.3 ; v1(7954.9,9023.7) 7931.8,9023.7 7931.2,9024.3 ; 7931.2,5629.3 7931.2,6414.3 ; 7931.2,6414.3 7931.2,6934.3 ; 7931.2,6934.3 7931.2,7719.3 ; 7931.2,7719.3 7931.2,8239.3 ; 7931.2,8239.3 7931.2,8504.3 ; 7931.2,8504.3 7931.2,9024.3
G-2_MAT(33): Q9$CBB19/CBB7.1 Q9$CBB19/CBB8.1 Q9$CBB19/CBB9.1 Q9$CBB19/CBB10.1 Q9$CBB19/CBB11.1 Q9$CBB19/CBB12.1 U1$CBB23.C10 | length 12039.6
  Top Layer w7.9: v1(8254.9,5893.1) Q9$CBB19/CBB12.1@8287.3,5893.1 ; v1(8254.9,6678.1) Q9$CBB19/CBB11.1@8287.3,6678.1 ; v1(8254.9,7198.1) Q9$CBB19/CBB10.1@8287.3,7198.1 ; v1(8254.9,7983.1) Q9$CBB19/CBB9.1@8287.3,7983.1 ; v1(8254.9,8768.1) Q9$CBB19/CBB8.1@8287.3,8768.1 ; v1(8254.9,9288.1) Q9$CBB19/CBB7.1@8287.3,9288.1
  Inner4 w4.7: v2(4050.1,5846.4) 4050.2,5846.5 4050.2,7227.2 4131,7308 4131,8990.5 4177.8,9037.3 4177.8,9354.8 4319.3,9496.3 8138.6,9496.3 v1(8236.2,9398.7)
  Inner4 w7.9: 8236.2,5388.7 8236.2,5891.4 ; v1(8236.2,9398.7) 8236.2,9286.4 ; v1(8254.9,5893.1) 8237.9,5893.1 8236.2,5891.4 ; v1(8254.9,6678.1) 8237.9,6678.1 8236.2,6676.4 ; v1(8254.9,7198.1) 8237.9,7198.1 8236.2,7196.4 ; v1(8254.9,7983.1) 8237.9,7983.1 8236.2,7981.4 ; v1(8254.9,8768.1) 8237.9,8768.1 8236.2,8766.4 ; v1(8254.9,9288.1) 8237.9,9288.1 8236.2,9286.4 ; 8236.2,5891.4 8236.2,6676.4 ; 8236.2,6676.4 8236.2,7196.4 ; 8236.2,7196.4 8236.2,7981.4 ; 8236.2,7981.4 8236.2,8766.4 ; 8236.2,8766.4 8236.2,9286.4
G-3_MAT(3): Q9$CBB49/CBB13.1 Q9$CBB49/CBB14.1 Q9$CBB49/CBB15.1 Q9$CBB49/CBB16.1 Q9$CBB49/CBB17.1 Q9$CBB49/CBB18.1 Q9$CBB49/CBB39.1 Q9$CBB49/CBB45.1 U1$CBB23.G4 | length 12798.2
  Top Layer w7.9: v1@8483.6,5888.7 8488,5893.1 Q9$CBB49/CBB18.1@8541,5893.1 ; v1@8483.6,6153.7 8488,6158.1 Q9$CBB49/CBB39.1@8541,6158.1 ; v1@8483.6,6673.7 8488,6678.1 Q9$CBB49/CBB17.1@8541,6678.1 ; v1@8483.6,7193.7 8488,7198.1 Q9$CBB49/CBB16.1@8541,7198.1 ; v1@8483.6,7458.7 8488,7463.1 Q9$CBB49/CBB45.1@8541,7463.1 ; v1@8483.6,7978.7 8488,7983.1 Q9$CBB49/CBB15.1@8541,7983.1 ; v1@8483.6,8763.7 8488,8768.1 Q9$CBB49/CBB14.1@8541,8768.1 ; v1@8483.6,9283.7 8488,9288.1 Q9$CBB49/CBB13.1@8541,9288.1
  Inner4 w4.7: v2(3861.1,5720.4) 3900.2,5720.4 3918.3,5738.5 3929.7,5738.5 3937.5,5746.4 3937.5,5757.8 3988.7,5809 3988.7,5870.9 3946.5,5913.1 3946.5,6071.8 3922.4,6095.9 3922.4,7140.7 4101.9,7320.1 4101.9,9002.6 4148.6,9049.3 4148.6,9366.9 4307.2,9525.5 8269.3,9525.5 8269.3,9524.9 8278.8,9515.4 8292.3,9515.4 8301.8,9524.9 8301.8,9525.5 8358.3,9525.5 8368,9515.8 8372.6,9515.8 8382.1,9506.3 8382.1,9501.7 v1@8483.6,9400.2
  Inner4 w7.9: 8483.6,5388.7 8483.6,5886.8 v1(8483.6,6151.8) 8483.6,6671.8 8483.6,7191.8 v1(8483.6,7456.8) 8483.6,7976.8 8483.6,8761.8 8483.6,9281.8 v1(8483.6,9398.7)
  other v1: 8483.6,5886.7 8483.6,6671.7 8483.6,7191.7 8483.6,7976.7 8483.6,8761.7 8483.6,9281.7
G-3_MAT(8): Q9$CBB9/CBB13.1 Q9$CBB9/CBB14.1 Q9$CBB9/CBB15.1 Q9$CBB9/CBB16.1 Q9$CBB9/CBB17.1 Q9$CBB9/CBB18.1 Q9$CBB9/CBB39.1 U1$CBB23.E11 | length 12936.1
  Top Layer w7.9: v1(8463.6,5628.7) 8473,5638.1 Q9$CBB9/CBB18.1@8541,5638.1 ; v1(8463.6,6413.7) 8473,6423.1 Q9$CBB9/CBB17.1@8541,6423.1 ; v1(8463.6,6933.7) 8473,6943.1 Q9$CBB9/CBB16.1@8541,6943.1 ; v1(8463.6,7718.7) 8473,7728.1 Q9$CBB9/CBB15.1@8541,7728.1 ; v1(8463.6,8238.7) 8473,8248.1 Q9$CBB9/CBB39.1@8541,8248.1 ; v1(8463.6,8503.7) 8473,8513.1 Q9$CBB9/CBB14.1@8541,8513.1 ; v1(8463.6,9023.7) 8473,9033.1 Q9$CBB9/CBB13.1@8541,9033.1
  Inner4 w4.7: v2(4081.6,5783.4) 4066.1,5798.9 4020.8,5798.9 3998.7,5821 3998.7,5874.6 3956.3,5917.1 3956.3,6078.3 3932.2,6102.4 3932.2,7136.7 4111.6,7316.1 4111.6,8998.5 4158.3,9045.3 4158.3,9362.8 4311.3,9515.7 8264.7,9515.7 8274.8,9505.6 8296.3,9505.6 8306.4,9515.7 8354.3,9515.7 8440.6,9429.4 v1(8440.6,9398.7)
  Inner4 w7.9: 8439.9,5388.7 8439.9,5629.3 ; v1(8440.6,9398.7) 8440.6,9340.2 8445.7,9335.1 8445.7,9294.4 8439.9,9288.5 8439.9,9024.3 ; v1(8463.6,5628.7) 8440.5,5628.7 8439.9,5629.3 ; v1(8463.6,6413.7) 8440.5,6413.7 8439.9,6414.3 ; v1(8463.6,6933.7) 8440.5,6933.7 8439.9,6934.3 ; v1(8463.6,7718.7) 8440.5,7718.7 8439.9,7719.3 ; v1(8463.6,8238.7) 8440.5,8238.7 8439.9,8239.3 ; v1(8463.6,8503.7) 8440.5,8503.7 8439.9,8504.3 ; v1(8463.6,9023.7) 8440.5,9023.7 8439.9,9024.3 ; 8439.9,5629.3 8439.9,6414.3 ; 8439.9,6414.3 8439.9,6934.3 ; 8439.9,6934.3 8439.9,7719.3 ; 8439.9,7719.3 8439.9,8239.3 ; 8439.9,8239.3 8439.9,8504.3 ; 8439.9,8504.3 8439.9,8770.5 8443.7,8774.4 8443.7,8821 8439.9,8824.9 8439.9,9024.3
G-3_MAT(33): Q9$CBB19/CBB13.1 Q9$CBB19/CBB14.1 Q9$CBB19/CBB15.1 Q9$CBB19/CBB16.1 Q9$CBB19/CBB17.1 Q9$CBB19/CBB18.1 U1$CBB23.D6 | length 12777.2
  Top Layer w7.9: v1(8763.6,5893.1) Q9$CBB19/CBB18.1@8796,5893.1 ; v1(8763.6,6678.1) Q9$CBB19/CBB17.1@8796,6678.1 ; v1(8763.6,7198.1) Q9$CBB19/CBB16.1@8796,7198.1 ; v1(8763.6,7983.1) Q9$CBB19/CBB15.1@8796,7983.1 ; v1(8763.6,8768.1) Q9$CBB19/CBB14.1@8796,8768.1 ; v1(8763.6,9288.1) Q9$CBB19/CBB13.1@8796,9288.1
  Inner4 w4.7: v2(3924.1,5814.9) 3933.2,5824 3933.2,5824.2 3938.5,5829.5 3938.5,5867.2 3917,5888.7 3917,5936.9 3892.4,5961.5 3892.4,7125 3893.3,7125.9 3893.3,7152.8 4072.7,7332.2 4072.7,9014.7 4119.4,9061.4 4119.4,9378.9 4295.2,9554.6 8258.2,9554.6 8270.8,9567.2 8300.3,9567.2 8312.9,9554.6 8589,9554.6 v1(8744.9,9398.7)
  Inner4 w7.9: 8744.9,5388.7 8744.9,5891.4 ; v1(8744.9,9398.7) 8744.9,9286.4 ; v1(8763.6,5893.1) 8746.6,5893.1 8744.9,5891.4 ; v1(8763.6,6678.1) 8746.6,6678.1 8744.9,6676.4 ; v1(8763.6,7198.1) 8746.6,7198.1 8744.9,7196.4 ; v1(8763.6,7983.1) 8746.6,7983.1 8744.9,7981.4 ; v1(8763.6,8768.1) 8746.6,8768.1 8744.9,8766.4 ; v1(8763.6,9288.1) 8746.6,9288.1 8744.9,9286.4 ; 8744.9,5891.4 8744.9,6676.4 ; 8744.9,6676.4 8744.9,7196.4 ; 8744.9,7196.4 8744.9,7981.4 ; 8744.9,7981.4 8744.9,8766.4 ; 8744.9,8766.4 8744.9,9286.4
G-4_MAT(3): Q9$CBB49/CBB19.1 Q9$CBB49/CBB20.1 Q9$CBB49/CBB21.1 Q9$CBB49/CBB22.1 Q9$CBB49/CBB23.1 Q9$CBB49/CBB24.1 Q9$CBB49/CBB40.1 Q9$CBB49/CBB46.1 U1$CBB23.D5 | length 13291.4
  Top Layer w7.9: v1@8992.3,5888.7 8996.7,5893.1 Q9$CBB49/CBB24.1@9049.7,5893.1 ; v1@8992.3,6153.7 8996.7,6158.1 Q9$CBB49/CBB40.1@9049.7,6158.1 ; v1@8992.3,6673.7 8996.7,6678.1 Q9$CBB49/CBB23.1@9049.7,6678.1 ; v1@8992.3,7193.7 8996.7,7198.1 Q9$CBB49/CBB22.1@9049.7,7198.1 ; v1@8992.3,7458.7 8996.7,7463.1 Q9$CBB49/CBB46.1@9049.7,7463.1 ; v1@8992.3,7978.7 8996.7,7983.1 Q9$CBB49/CBB21.1@9049.7,7983.1 ; v1@8992.3,8763.7 8996.7,8768.1 Q9$CBB49/CBB20.1@9049.7,8768.1 ; v1@8992.3,9283.7 8996.7,9288.1 Q9$CBB49/CBB19.1@9049.7,9288.1
  Inner4 w4.7: v2(3892.6,5814.9) 3895.4,5817.6 3895.4,5863.4 3869.9,5888.9 3868.9,5888.9 3863.2,5894.6 3863.2,7137.1 3864.1,7138 3864.1,7164.9 4043.5,7344.3 4043.5,9026.7 4090.3,9073.5 4090.3,9391 4283.1,9583.8 8246.1,9583.8 8258.7,9596.4 8312.4,9596.4 8325,9583.8 8898.2,9583.8 8992.3,9489.8 v1(8992.3,9398.7)
  Inner4 w7.9: 8992.3,5388.7 v1(8992.3,5886.8) v1(8992.3,6151.8) v1(8992.3,6671.8) v1(8992.3,7191.8) v1(8992.3,7456.8) v1(8992.3,7976.8) v1(8992.3,8761.8) v1(8992.3,9281.8) v1(8992.3,9398.7)
G-4_MAT(8): Q9$CBB9/CBB19.1 Q9$CBB9/CBB20.1 Q9$CBB9/CBB21.1 Q9$CBB9/CBB22.1 Q9$CBB9/CBB23.1 Q9$CBB9/CBB24.1 Q9$CBB9/CBB40.1 U1$CBB23.E5 | length 13524.6
  Top Layer w7.9: v1(8972.3,5628.7) 8981.7,5638.1 Q9$CBB9/CBB24.1@9049.7,5638.1 ; v1(8972.3,6413.7) 8981.7,6423.1 Q9$CBB9/CBB23.1@9049.7,6423.1 ; v1(8972.3,6933.7) 8981.7,6943.1 Q9$CBB9/CBB22.1@9049.7,6943.1 ; v1(8972.3,7718.7) 8981.7,7728.1 Q9$CBB9/CBB21.1@9049.7,7728.1 ; v1(8972.3,8238.7) 8981.7,8248.1 Q9$CBB9/CBB40.1@9049.7,8248.1 ; v1(8972.3,8503.7) 8981.7,8513.1 Q9$CBB9/CBB20.1@9049.7,8513.1 ; v1(8972.3,9023.7) 8981.7,9033.1 Q9$CBB9/CBB19.1@9049.7,9033.1
  Inner4 w4.7: v2(3892.6,5783.4) 3908.4,5799.2 3908.4,5863.2 3873,5898.6 3873,7133.1 3873.8,7133.9 3873.8,7160.9 4053.2,7340.3 4053.2,9022.7 4100,9069.5 4100,9387 4287.1,9574.1 8250.1,9574.1 8262.7,9586.7 8308.4,9586.7 8321,9574.1 8858.4,9574.1 8948.6,9483.9 v1(8948.6,9398.7)
  Inner4 w7.9: 8948.6,5388.7 8948.6,5629.3 ; v1(8948.6,9398.7) 8948.6,9024.3 ; v1(8972.3,5628.7) 8949.2,5628.7 8948.6,5629.3 ; v1(8972.3,6413.7) 8949.2,6413.7 8948.6,6414.3 ; v1(8972.3,6933.7) 8949.2,6933.7 8948.6,6934.3 ; v1(8972.3,7718.7) 8949.2,7718.7 8948.6,7719.3 ; v1(8972.3,8238.7) 8949.2,8238.7 8948.6,8239.3 ; v1(8972.3,8503.7) 8949.2,8503.7 8948.6,8504.3 ; v1(8972.3,9023.7) 8949.2,9023.7 8948.6,9024.3 ; 8948.6,5629.3 8948.6,6414.3 ; 8948.6,6414.3 8948.6,6934.3 ; 8948.6,6934.3 8948.6,7719.3 ; 8948.6,7719.3 8948.6,8239.3 ; 8948.6,8239.3 8948.6,8504.3 ; 8948.6,8504.3 8948.6,9024.3
G-4_MAT(33): Q9$CBB19/CBB19.1 Q9$CBB19/CBB20.1 Q9$CBB19/CBB21.1 Q9$CBB19/CBB22.1 Q9$CBB19/CBB23.1 Q9$CBB19/CBB24.1 U1$CBB23.C4 | length 13423.2
  Top Layer w7.9: v1(9272.3,5893.1) Q9$CBB19/CBB24.1@9304.7,5893.1 ; v1(9272.3,6678.1) Q9$CBB19/CBB23.1@9304.7,6678.1 ; v1(9272.3,7198.1) Q9$CBB19/CBB22.1@9304.7,7198.1 ; v1(9272.3,7983.1) Q9$CBB19/CBB21.1@9304.7,7983.1 ; v1(9272.3,8768.1) Q9$CBB19/CBB20.1@9304.7,8768.1 ; v1(9272.3,9288.1) Q9$CBB19/CBB19.1@9304.7,9288.1
  Inner4 w4.7: v2(3861.1,5846.4) 3861.1,5856.7 3847.7,5870.2 3846.7,5870.2 3840.1,5876.8 3839.8,5876.8 3834.1,5882.5 3834.1,7149.2 3834.9,7150 3834.9,7177 4014.3,7356.4 4014.3,9038.8 4061.1,9085.6 4061.1,9403.1 4271,9613 8234,9613 8246.6,9625.6 8324.5,9625.6 8337.1,9613 9143.5,9613 9253.6,9503 v1(9253.6,9398.7)
  Inner4 w7.9: 9253.6,5388.7 9253.6,5891.4 ; v1(9253.6,9398.7) 9253.6,9286.4 ; v1(9272.3,5893.1) 9255.3,5893.1 9253.6,5891.4 ; v1(9272.3,6678.1) 9255.3,6678.1 9253.6,6676.4 ; v1(9272.3,7198.1) 9255.3,7198.1 9253.6,7196.4 ; v1(9272.3,7983.1) 9255.3,7983.1 9253.6,7981.4 ; v1(9272.3,8768.1) 9255.3,8768.1 9253.6,8766.4 ; v1(9272.3,9288.1) 9255.3,9288.1 9253.6,9286.4 ; 9253.6,5891.4 9253.6,6676.4 ; 9253.6,6676.4 9253.6,7196.4 ; 9253.6,7196.4 9253.6,7981.4 ; 9253.6,7981.4 9253.6,8766.4 ; 9253.6,8766.4 9253.6,9286.4
G-5_MAT(3): Q9$CBB49/CBB25.1 Q9$CBB49/CBB26.1 Q9$CBB49/CBB27.1 Q9$CBB49/CBB28.1 Q9$CBB49/CBB29.1 Q9$CBB49/CBB30.1 Q9$CBB49/CBB41.1 Q9$CBB49/CBB47.1 U1$CBB23.E3 | length 13964.1
  Top Layer w7.9: v1@9501,5888.7 9505.4,5893.1 Q9$CBB49/CBB30.1@9558.4,5893.1 ; v1@9501,6153.7 9505.4,6158.1 Q9$CBB49/CBB41.1@9558.4,6158.1 ; v1@9501,6673.7 9505.4,6678.1 Q9$CBB49/CBB29.1@9558.4,6678.1 ; v1@9501,7193.7 9505.4,7198.1 Q9$CBB49/CBB28.1@9558.4,7198.1 ; v1@9501,7458.7 9505.4,7463.1 Q9$CBB49/CBB47.1@9558.4,7463.1 ; v1@9501,7978.7 9505.4,7983.1 Q9$CBB49/CBB27.1@9558.4,7983.1 ; v1@9501,8763.7 9505.4,8768.1 Q9$CBB49/CBB26.1@9558.4,8768.1 ; v1@9501,9283.7 9505.4,9288.1 Q9$CBB49/CBB25.1@9558.4,9288.1
  Inner4 w4.7: v2(3829.6,5783.4) 3814,5799.1 3814,5845.1 3804.9,5854.3 3804.9,7161.3 3805.7,7162.1 3805.7,7189.1 3985.2,7368.5 3985.2,9050.9 4031.9,9097.7 4031.9,9415.2 4258.9,9642.2 8221.9,9642.2 8234.5,9654.8 8336.6,9654.8 8349.2,9642.2 9376.8,9642.2 9501,9518 v1(9501,9398.7)
  Inner4 w7.9: 9501,5388.7 v1(9501,5886.8) v1(9501,6151.8) v1(9501,6671.8) v1(9501,7191.8) v1(9501,7456.8) v1(9501,7976.8) v1(9501,8761.8) v1(9501,9281.8) v1(9501,9398.7)
G-5_MAT(8): Q9$CBB9/CBB25.1 Q9$CBB9/CBB26.1 Q9$CBB9/CBB27.1 Q9$CBB9/CBB28.1 Q9$CBB9/CBB29.1 Q9$CBB9/CBB30.1 Q9$CBB9/CBB41.1 U1$CBB23.C3 | length 14093.1
  Top Layer w7.9: v1(9481,5628.7) 9490.4,5638.1 Q9$CBB9/CBB30.1@9558.4,5638.1 ; v1(9481,6413.7) 9490.4,6423.1 Q9$CBB9/CBB29.1@9558.4,6423.1 ; v1(9481,6933.7) 9490.4,6943.1 Q9$CBB9/CBB28.1@9558.4,6943.1 ; v1(9481,7718.7) 9490.4,7728.1 Q9$CBB9/CBB27.1@9558.4,7728.1 ; v1(9481,8238.7) 9490.4,8248.1 Q9$CBB9/CBB41.1@9558.4,8248.1 ; v1(9481,8503.7) 9490.4,8513.1 Q9$CBB9/CBB26.1@9558.4,8513.1 ; v1(9481,9023.7) 9490.4,9033.1 Q9$CBB9/CBB25.1@9558.4,9033.1
  Inner4 w4.7: v2(3829.6,5846.4) 3815.6,5860.5 3815.6,5873.5 3814.6,5874.5 3814.6,7157.2 3815.5,7158.1 3815.5,7185 3994.9,7364.4 3994.9,9046.9 4041.7,9093.7 4041.7,9411.2 4262.9,9632.4 8226,9632.4 8238.6,9645 8332.5,9645 8345.1,9632.4 9337.8,9632.4 9457.3,9513 v1(9457.3,9398.7)
  Inner4 w7.9: 9457.3,5388.7 9457.3,5629.3 ; v1(9457.3,9398.7) 9457.3,9024.3 ; v1(9481,5628.7) 9457.9,5628.7 9457.3,5629.3 ; v1(9481,6413.7) 9457.9,6413.7 9457.3,6414.3 ; v1(9481,6933.7) 9457.9,6933.7 9457.3,6934.3 ; v1(9481,7718.7) 9457.9,7718.7 9457.3,7719.3 ; v1(9481,8238.7) 9457.9,8238.7 9457.3,8239.3 ; v1(9481,8503.7) 9457.9,8503.7 9457.3,8504.3 ; v1(9481,9023.7) 9457.9,9023.7 9457.3,9024.3 ; 9457.3,5629.3 9457.3,6414.3 ; 9457.3,6414.3 9457.3,6934.3 ; 9457.3,6934.3 9457.3,7719.3 ; 9457.3,7719.3 9457.3,8239.3 ; 9457.3,8239.3 9457.3,8504.3 ; 9457.3,8504.3 9457.3,9024.3
G-5_MAT(33): Q9$CBB19/CBB25.1 Q9$CBB19/CBB26.1 Q9$CBB19/CBB27.1 Q9$CBB19/CBB28.1 Q9$CBB19/CBB29.1 Q9$CBB19/CBB30.1 U1$CBB23.B2 | length 14077.4
  Top Layer w4.7: U1$CBB23.B2@3798.2,5877.9 3814,5893.8 3814,5954.1 3916.4,6056.6 3916.4,7221.3 v1(3851.4,7286.3)
  Top Layer w7.9: v1(9781,5893.1) Q9$CBB19/CBB30.1@9813.4,5893.1 ; v1(9781,6678.1) Q9$CBB19/CBB29.1@9813.4,6678.1 ; v1(9781,7198.1) Q9$CBB19/CBB28.1@9813.4,7198.1 ; v1(9781,7983.1) Q9$CBB19/CBB27.1@9813.4,7983.1 ; v1(9781,8768.1) Q9$CBB19/CBB26.1@9813.4,8768.1 ; v1(9781,9288.1) Q9$CBB19/CBB25.1@9813.4,9288.1
  Inner4 w4.7: v1(3851.4,7286.3) 3861.8,7286.3 3956,7380.6 3956,9063 4002.8,9109.8 4002.8,9427.3 4246.8,9671.3 8209.8,9671.3 8222.4,9683.9 8348.7,9683.9 8361.3,9671.3 9624,9671.3 9762.3,9533.1 v1(9762.3,9398.7)
  Inner4 w7.9: 9762.3,5388.7 9762.3,5891.4 ; v1(9762.3,9398.7) 9762.3,9286.4 ; v1(9781,5893.1) 9764,5893.1 9762.3,5891.4 ; v1(9781,6678.1) 9764,6678.1 9762.3,6676.4 ; v1(9781,7198.1) 9764,7198.1 9762.3,7196.4 ; v1(9781,7983.1) 9764,7983.1 9762.3,7981.4 ; v1(9781,8768.1) 9764,8768.1 9762.3,8766.4 ; v1(9781,9288.1) 9764,9288.1 9762.3,9286.4 ; 9762.3,5891.4 9762.3,6676.4 ; 9762.3,6676.4 9762.3,7196.4 ; 9762.3,7196.4 9762.3,7981.4 ; 9762.3,7981.4 9762.3,8766.4 ; 9762.3,8766.4 9762.3,9286.4
G-6_MAT(3): Q9$CBB49/CBB31.1 Q9$CBB49/CBB32.1 Q9$CBB49/CBB33.1 Q9$CBB49/CBB34.1 Q9$CBB49/CBB35.1 Q9$CBB49/CBB36.1 Q9$CBB49/CBB42.1 Q9$CBB49/CBB48.1 U1$CBB23.C2 | length 14798.1
  Top Layer w4.7: v1(3794.2,7252.4) 3795.3,7252.4 3887.2,7160.5 3887.2,6075 3747.8,5935.5 3747.8,5873.2 3757.8,5863.2 3781.4,5863.2 U1$CBB23.C2@3798.2,5846.4
  Top Layer w7.9: v1@10009.7,5888.7 10014.1,5893.1 Q9$CBB49/CBB36.1@10067.1,5893.1 ; v1@10009.7,6153.7 10014.1,6158.1 Q9$CBB49/CBB42.1@10067.1,6158.1 ; v1@10009.7,6673.7 10014.1,6678.1 Q9$CBB49/CBB35.1@10067.1,6678.1 ; v1@10009.7,7193.7 10014.1,7198.1 Q9$CBB49/CBB34.1@10067.1,7198.1 ; v1@10009.7,7458.7 10014.1,7463.1 Q9$CBB49/CBB48.1@10067.1,7463.1 ; v1@10009.7,7978.7 10014.1,7983.1 Q9$CBB49/CBB33.1@10067.1,7983.1 ; v1@10009.7,8763.7 10014.1,8768.1 Q9$CBB49/CBB32.1@10067.1,8768.1 ; v1@10009.7,9283.7 10014.1,9288.1 Q9$CBB49/CBB31.1@10067.1,9288.1
  Inner4 w4.7: v1(3794.2,7252.4) 3770.2,7276.4 3770.2,9402.8 4067.9,9700.5 8197.8,9700.5 8210.4,9713.1 8360.7,9713.1 8373.3,9700.5 9909.6,9700.5 10009.7,9600.5 v1(10009.7,9398.7)
  Inner4 w7.9: 10009.7,5388.7 v1(10009.7,5886.8) v1(10009.7,6151.8) v1(10009.7,6671.8) v1(10009.7,7191.8) v1(10009.7,7456.8) v1(10009.7,7976.8) v1(10009.7,8761.8) v1(10009.7,9281.8) v1(10009.7,9398.7)
G-6_MAT(8): Q9$CBB9/CBB31.1 Q9$CBB9/CBB32.1 Q9$CBB9/CBB33.1 Q9$CBB9/CBB34.1 Q9$CBB9/CBB35.1 Q9$CBB9/CBB36.1 Q9$CBB9/CBB42.1 U1$CBB23.B1 | length 14917
  Top Layer w4.7: U1$CBB23.B1@3766.7,5877.9 3782.5,5893.8 3782.5,5950.2 3897,6064.6 3897,7173.7 v1(3817.9,7252.8)
  Top Layer w7.9: v1(9989.7,5628.7) 9999.1,5638.1 Q9$CBB9/CBB36.1@10067.1,5638.1 ; v1(9989.7,6413.7) 9999.1,6423.1 Q9$CBB9/CBB35.1@10067.1,6423.1 ; v1(9989.7,6933.7) 9999.1,6943.1 Q9$CBB9/CBB34.1@10067.1,6943.1 ; v1(9989.7,7718.7) 9999.1,7728.1 Q9$CBB9/CBB33.1@10067.1,7728.1 ; v1(9989.7,8238.7) 9999.1,8248.1 Q9$CBB9/CBB42.1@10067.1,8248.1 ; v1(9989.7,8503.7) 9999.1,8513.1 Q9$CBB9/CBB32.1@10067.1,8513.1 ; v1(9989.7,9023.7) 9999.1,9033.1 Q9$CBB9/CBB31.1@10067.1,9033.1
  Inner4 w4.7: v1(3817.9,7252.8) 3779.9,7290.8 3779.9,9398.8 4071.9,9690.8 8201.8,9690.8 8214.4,9703.4 8356.7,9703.4 8369.3,9690.8 9843.1,9690.8 9966,9567.9 v1(9966,9398.7)
  Inner4 w7.9: 9966,5388.7 9966,5629.3 ; v1(9966,9398.7) 9966,9344.8 9967.7,9343.1 9967.7,9290.4 9966,9288.6 9966,9024.3 9966.6,9023.7 ; v1(9989.7,5628.7) 9966.6,5628.7 9966,5629.3 ; v1(9989.7,6413.7) 9966.6,6413.7 9966,6414.3 ; v1(9989.7,6933.7) 9966.6,6933.7 9966,6934.3 ; v1(9989.7,7718.7) 9966.6,7718.7 ; v1(9989.7,8238.7) 9966.6,8238.7 ; v1(9989.7,8503.7) 9966.6,8503.7 9966,8504.3 ; v1(9989.7,9023.7) 9966.6,9023.7 ; 9966,5629.3 9966,6414.3 ; 9966,6414.3 9966,6674.4 9969.7,6678.1 9969.7,6726.8 9966,6730.6 9966,6934.3 ; 9966,6934.3 9969.7,6938.1 9969.7,7715.6 9966.6,7718.7 ; 9966,8504.3 9966,8239.3 9966.6,8238.7 ; 9966,8504.3 9969.7,8508.1 9969.7,9020.6 9966.6,9023.7 ; 9966.6,7718.7 9966,7719.3 9967.7,7721 9967.7,8237.6 9966.6,8238.7
G-6_MAT(33): Q9$CBB19/CBB31.1 Q9$CBB19/CBB32.1 Q9$CBB19/CBB33.1 Q9$CBB19/CBB34.1 Q9$CBB19/CBB35.1 Q9$CBB19/CBB36.1 U1$CBB23.E2 | length 15050.3
  Top Layer w4.7: v1(3761.2,7194.3) 3858.1,7097.4 3858.1,6087 3718,5947 3718,5840.7 3759.8,5798.9 3782.6,5798.9 U1$CBB23.E2@3798.2,5783.4
  Top Layer w7.9: v1(10289.7,5893.1) Q9$CBB19/CBB36.1@10322.1,5893.1 ; v1(10289.7,6678.1) Q9$CBB19/CBB35.1@10322.1,6678.1 ; v1(10289.7,7198.1) Q9$CBB19/CBB34.1@10322.1,7198.1 ; v1(10289.7,7983.1) Q9$CBB19/CBB33.1@10322.1,7983.1 ; v1(10289.7,8768.1) Q9$CBB19/CBB32.1@10322.1,8768.1 ; v1(10289.7,9288.1) Q9$CBB19/CBB31.1@10322.1,9288.1
  Inner4 w4.7: v1(3761.2,7194.3) 3761.2,7204.8 3741,7225 3741,9414.9 4055.8,9729.7 8185.7,9729.7 8198.3,9742.3 8372.8,9742.3 8385.4,9729.7 10173.6,9729.7 10271,9632.3 v1(10271,9398.7)
  Inner4 w7.9: 10271,5388.7 10271,5891.4 ; v1(10271,9398.7) 10271,9286.4 ; v1(10289.7,5893.1) 10272.7,5893.1 10271,5891.4 ; v1(10289.7,6678.1) 10272.7,6678.1 10271,6676.4 ; v1(10289.7,7198.1) 10272.7,7198.1 10271,7196.4 ; v1(10289.7,7983.1) 10272.7,7983.1 10271,7981.4 ; v1(10289.7,8768.1) 10272.7,8768.1 10271,8766.4 ; v1(10289.7,9288.1) 10272.7,9288.1 10271,9286.4 ; 10271,5891.4 10271,6676.4 ; 10271,6676.4 10271,7196.4 ; 10271,7196.4 10271,7981.4 ; 10271,7981.4 10271,8766.4 ; 10271,8766.4 10271,9286.4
